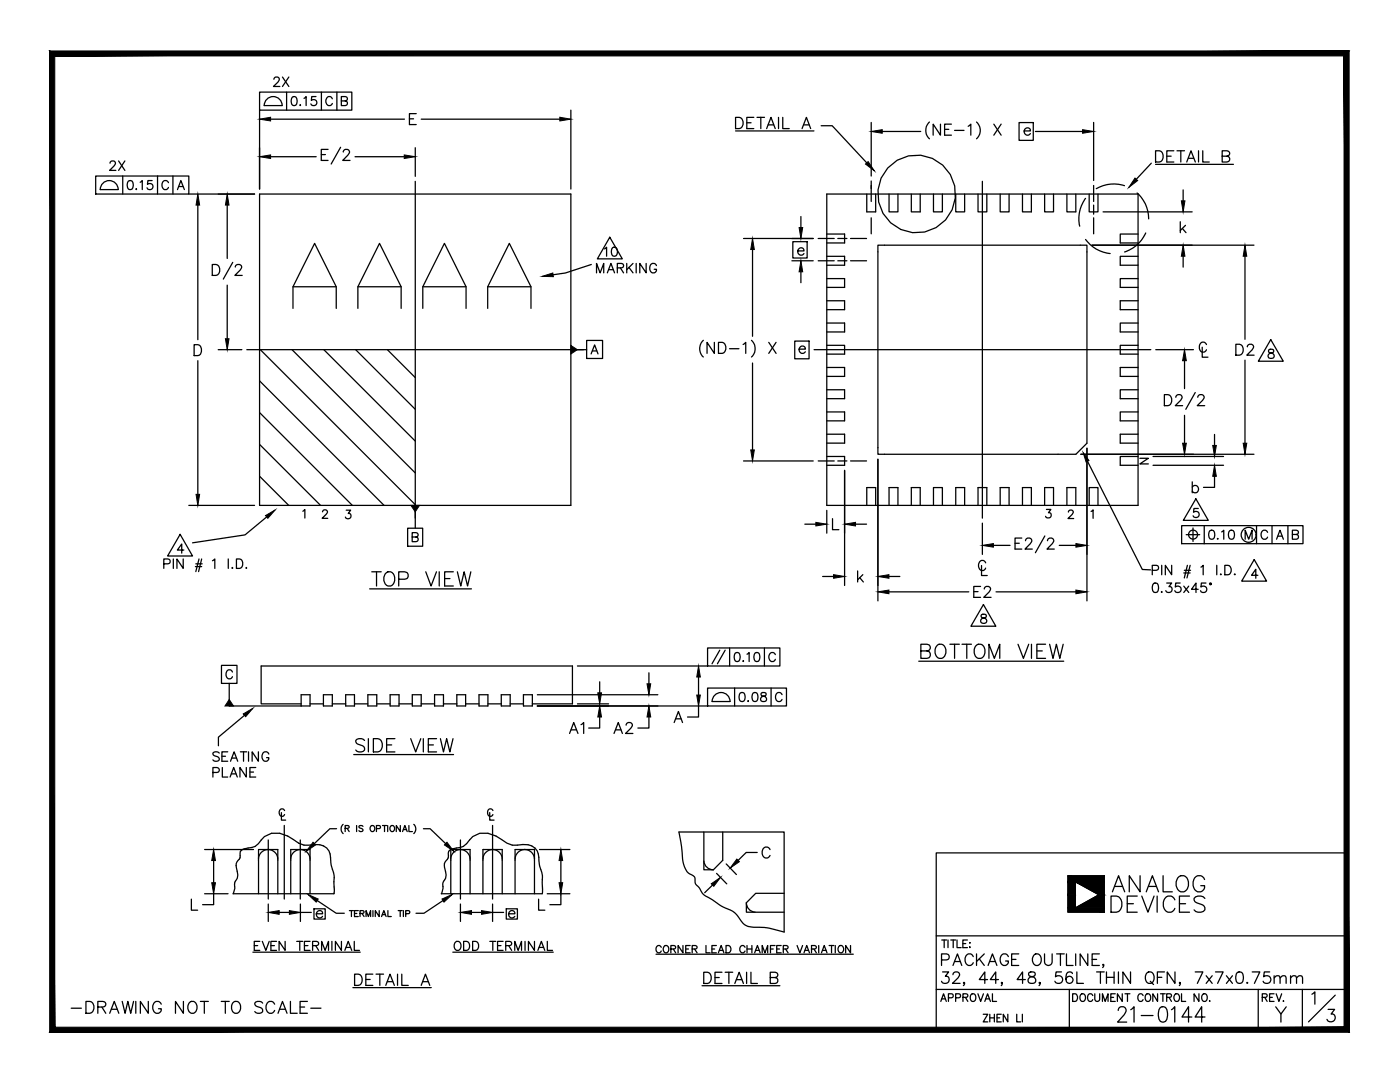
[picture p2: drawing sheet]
<svg xmlns="http://www.w3.org/2000/svg" width="279mm" height="216mm" viewBox="0 0 279 216" stroke-linecap="round" stroke-linejoin="round" font-family="sans-serif">
<defs><g id="words">
<text font-size="19" x="57.1" y="62.8">AAAA</text>
<g font-size="6.6">
<text x="220.8" y="179.2">ANALOG</text>
<text x="220.5" y="183.1">DEVICES</text>
<text x="221.9" y="205.3">21-0144</text>
</g>
<g font-size="5.7">
<text x="229.3" y="33.9">DETAIL B</text>
<text x="13.1" y="203.6">-DRAWING NOT TO SCALE-</text>
</g>
<text font-size="5.3" x="117.8" y="55.7">MARKING</text>
<g font-size="4.9">
<text x="53.3" y="18.3">2X</text>
<text x="20.8" y="35.3">2X</text>
<text x="119.2" y="52.2">10</text>
</g>
<text font-size="4.4" x="186.6" y="201.1">APPROVAL</text>
<text font-size="4" x="226.1" y="93.8">N</text>
</g></defs>
<!-- layer: 2 -->
<g fill="none" stroke="#000" stroke-width=".25">
<path d="M51.8 18.4h18.4v3.6h-18.4zM53.3 19.8a1.79 1.79 0 0 1 1.9-.4 1.79 1.79 0 0 1 1.1 1.7h-3.6l.1-.5zM57.2 18.4v3.6M58.4 19.4a.57 .57 0 0 1 .8 .2 .9 .9 0 0 1-.6 1.5 1.15 1.15 0 0 1-.2-1.7zM60.7 19.6l.4-.3v1.8M63.1 19.3h-.9l-.1 .8a.63 .63 0 0 1 1-.1 .63 .63 0 0 1-.1 1 .63 .63 0 0 1-1-.3M64.1 18.4v3.6M66.3 19.7a.66 .66 0 0 0-.7-.4 .66 .66 0 0 0-.6 .7 .74 .74 0 0 0 .3 .9 .74 .74 0 0 0 .9-.1l.1-.2M67.2 18.4v3.6M19.1 35.1h18.6v3.6h-18.6zM20.5 36.6a1.79 1.79 0 0 1 2-.4 1.79 1.79 0 0 1 1.1 1.6h-3.6l.1-.5zM24.5 35.1v3.6"/>
<path d="M25.6 36.1a.6 .6 0 0 1 .9 .3 .92 .92 0 0 1-.6 1.4 .98 .98 0 0 1-.4-1.4zM27.2 37.6l-.1 .1h.2M28 36.4l.4-.4v1.8M30.4 36h-.9l-.1 .8a.63 .63 0 0 1 1 0 .63 .63 0 0 1-.1 .9 .63 .63 0 0 1-1-.2M31.4 35.1v3.6M33.6 36.5a.67 .67 0 0 0-.7-.5 .67 .67 0 0 0-.6 .7v.4a.66 .66 0 0 0 .6 .7 .66 .66 0 0 0 .7-.4M34.5 35.1v3.6M35.4 37.8l.7-1.8 .7 1.8M35.7 37.2h.8M59.9 20.9v.2l.1-.1M68.1 20.1h1.1l.1-.3-.1-.4-.3-.1h-.8v1.8h.8a.47 .47 0 0 0 .4-.5 .47 .47 0 0 0-.4-.5M82.9 36.2v69.2"/>
<path d="M146.8 23.4h.7a1.19 1.19 0 0 1 .8 1.1 1.19 1.19 0 0 1-.8 1.2h-.7zM146.8 26.1h15.6M149 24.5h.9M150.4 23.4h-1.4v2.3h1.4M151.1 23.4h1.5M151.8 23.4v2.3M153 25.7l.9-2.3 .8 2.3M153.3 24.9h1.1M155.4 23.4v2.3M156.2 23.4v2.3h1.3M160.1 25.7l.8-2.3 .9 2.3M160.4 24.9h1.1"/>
<path d="M163.9 25.1h2.2l6.9 7.4M173.9 36.1v4.1M196.1 36.2v67.2M216.6 39.6a6.7 6.7 0 0 0-1.1 5.5M218.3 37v3.2M224.4 37a7 7 0 0 0-5.6 .6M226.9 38.5a6.8 6.8 0 0 1 2.3 5.2M229.8 32.6l-3 3.2M230.6 32.8h15.6M118 52.8l-5.2 1.7-2.4 .3M167.2 47.6h1.8M167.2 52h1.8"/>
<path d="M169.7 47.6h3.2M169.7 52h3.2M173.9 43.5v3.2M216.6 47.8a6.9 6.9 0 0 0 5 2.8M218.3 40.9v1.8M218.3 43.5v3.2M228.6 46.5a6.9 6.9 0 0 1-4.2 3.8M49.3 69.8h67.8M51.8 76l24.9 24.8M52 69.8l30.9 30.9M58.3 69.8l24.6 24.6M64.6 69.8l18.3 18.2"/>
<path d="M71 69.8l11.9 11.9M77.3 69.8l5.6 5.5M117.1 67.9h3.2v3.6h-3.2zM118 70.6l.7-1.8 .6 1.8M118.2 70h.9M158.6 68.1h2.9v3.5h-2.9zM162.5 69.8h67.2M239.9 69.3v2h1.2M240.8 68.8a.73 .73 0 0 0-.9-.5 .73 .73 0 0 0-.5 .7 .87 .87 0 0 0 .1 1 .87 .87 0 0 0 1 .2l.3-.4M253.2 69.8a.37 .37 0 0 0 .2 .6 .67 .67 0 0 1 .7 .2 .67 .67 0 0 1 .1 .7l-.7 .2a.52 .52 0 0 1-.4-.6 .52 .52 0 0 1 .5-.4l.3-.1a.37 .37 0 0 0 .2-.6zM253.6 67.8l2.5 4.3h-5zM51.8 95l5.8 5.8"/>
<path d="M51.8 88.7l12.2 12.1M51.8 82.3l18.5 18.5M163.3 92h3.2M167.2 92h1.8M169.7 92h3.2M217 92l11 21.6 1.6 .1M238.7 99.5l2.4 4.3h-4.9zM32.7 112.5h.8a.49 .49 0 0 0 .5-.5 .49 .49 0 0 0-.5-.5h-.8v1.9M34.6 111.5v1.9M35.9 106.6l2.5 4.3h-4.9zM36.6 111.5v1.9l-1.3-1.9v1.9M36.7 109.8h-1.3l.9-1.3v1.9"/>
<path d="M39 113.1h1.2M39.1 112.5h1.3M39.7 111.5l-.6 2.6M40.2 111.5l-.6 2.6M42.4 111.9l.5-.4v1.9M45.6 111.5v1.9M46.4 113.2v.2l.1-.1M47.2 111.5h.6a1 1 0 0 1 .7 1 1 1 0 0 1-.7 .9h-.6zM49.2 113.2l-.1 .1h.1M53.2 103.2l-4.3 3.5-10.5 1.6M60.4 102l.4-.3v1.7M64.4 102.1l.3-.4 .6 .2a.5 .5 0 0 1-.2 .7l-.8 .8h1.1"/>
<path d="M69.1 101.8h.9l-.5 .7a.57 .57 0 0 1 .4 .9 .57 .57 0 0 1-1-.2M73.8 117.5h20.3M74.2 114.1h1.9M75.1 114.1v2.8M76.9 114.5a1.04 1.04 0 0 1 1.2-.4 1.04 1.04 0 0 1 .7 1.1 1.25 1.25 0 0 1-.3 1.3 1.25 1.25 0 0 1-1.3 .3 1.75 1.75 0 0 1-.3-2.3zM79.6 115.6l1.6-.1a.76 .76 0 0 0 .3-.9 .76 .76 0 0 0-.7-.5h-1.2v2.8M81.4 105.4h3v3.6h-3zM82.3 107.2l1-.1 .1-.3-.1-.4-1-.1v1.8h.7a.47 .47 0 0 0 .5-.5 .47 .47 0 0 0-.5-.4M85 114.1l1 2.8 1.1-2.8M87.7 114.1v2.8M88.7 115.5h1.1M90.5 114.1h-1.8v2.8h1.8"/>
<path d="M91.3 114.1l.7 2.8 .6-2.8 .7 2.8 .7-2.8M195.9 112.8v2h1.1M196.7 112.3a.73 .73 0 0 0-.8-.5 .73 .73 0 0 0-.6 .8 .88 .88 0 0 0 .2 .9 .88 .88 0 0 0 .9 .2l.3-.3M208.8 101.6h.9l-.5 .7a.57 .57 0 0 1 .5 .9 .57 .57 0 0 1-1-.2M213.2 102.2l.4-.4 .5 .1a.52 .52 0 0 1-.1 .8l-.9 .8h1.2M217.7 102.1l.5-.4v1.7M230 113.8l1-.1 .2-.3-.1-.4-.3-.2h-.8v1.9M230.2 116.4a.61 .61 0 0 1 .9 .3 1.64 1.64 0 0 1-.1 1.4 .63 .63 0 0 1-1-.2 1.57 1.57 0 0 1 .2-1.5zM231.8 118v.1h.1M231.8 112.8v1.9M232.8 116.3h1l-.5 .8a.63 .63 0 0 1 .5 .9 .63 .63 0 0 1-1 0l-.2-.1M233.8 112.8v1.9l-1.2-1.9v1.9"/>
<path d="M235.5 116.3h-.9v.8a.67 .67 0 0 1 1 0 .67 .67 0 0 1-.2 1 .67 .67 0 0 1-1-.2M235.8 104.9h24.2v3.6h-24.2zM236.2 114.3h1.3M236.2 117l1 1.2M236.4 113.8h1.2M236.7 106.7h2.7M237 112.8l-.6 2.5M237.2 117l-1 1.2M237.5 112.8l-.6 2.5M238.1 105.4v2.6M239.1 117.6h-1.3l.9-1.3v1.9M239.1 101.5h-.8l-.1 .7a.64 .64 0 0 1 1 0 .64 .64 0 0 1-.2 1 .64 .64 0 0 1-.9-.3"/>
<path d="M239.7 113.2l.4-.4v1.9M240.3 104.9v3.6M240.7 116.3h-.9l-.1 .8a.66 .66 0 0 1 1 0 .66 .66 0 0 1-.1 1 .66 .66 0 0 1-1-.2M241.5 105.9a.6 .6 0 0 1 .8 .2 1.18 1.18 0 0 1-.4 1.5h-.1a.96 .96 0 0 1-.5-1.5zM242.8 112.8v1.9M243 107.4l-.1 .1h.2M243.6 114.5v.1h.1M243.8 106.1l.4-.3v1.8M244.4 112.8h.7a1 1 0 0 1 .6 .9 1 1 0 0 1-.6 1h-.7zM245.4 105.9a.58 .58 0 0 1 .9 .2 1.18 1.18 0 0 1-.4 1.5h-.2a1.12 1.12 0 0 1-.3-1.7zM246.4 114.5l-.1 .1h.2M248.5 107.6v-1.8l.7 1.8 .7-1.8v1.8"/>
<path d="M250.3 111.7l2.5 4.3h-5zM250.8 104.9v3.6M251 114.8h-1.2l.8-1.2v1.8M253 106.2a.67 .67 0 0 0-.8-.4 .67 .67 0 0 0-.5 .7 .75 .75 0 0 0 .2 .9 .75 .75 0 0 0 1-.1l.1-.1M253.9 104.9v3.6M254.8 107.6l.6-1.8 .7 1.8M255 107h.9M257 104.9v3.6M257.9 106.6h1.1l.1-.3-.1-.3-.3-.2h-.8v1.8h.8a.48 .48 0 0 0 .4-.5 .48 .48 0 0 0-.4-.5M44.2 132.8h3.1v3.6h-3.1zM45.7 136.4v4.5h14.4M46.4 134.1a.65 .65 0 0 0-.8-.4 .65 .65 0 0 0-.5 .7v.4a.65 .65 0 0 0 .5 .7 .65 .65 0 0 0 .8-.5"/>
<path d="M141.2 129.3h14.4v3.6h-14.4zM141.2 137.3h15.8v3.6h-15.8zM142.1 140h3.6M142.1 140a1.79 1.79 0 0 1 1.8-1.8 1.79 1.79 0 0 1 1.8 1.8M143.6 129.7l-1.5 2.7M144.7 129.7l-1.5 2.7M145.6 129.3v3.6M146.6 137.3v3.6M146.8 130.3a.58 .58 0 0 1 .8 .2 .92 .92 0 0 1-.6 1.5 1.16 1.16 0 0 1-.2-1.7zM147.8 138.3a.6 .6 0 0 1 .8 .2 .9 .9 0 0 1-.6 1.5 1.15 1.15 0 0 1-.2-1.7zM148.3 131.8l-.1 .1h.2M149.1 130.5l.4-.3v1.8"/>
<path d="M149.3 139.8l-.1 .1h.2M150.3 138.3a.58 .58 0 0 1 .9 .2 .91 .91 0 0 1-.6 1.5 1.15 1.15 0 0 1-.3-1.7zM150.7 130.3a.58 .58 0 0 1 .9 .2 .92 .92 0 0 1-.6 1.5 1.16 1.16 0 0 1-.3-1.7zM152 138.3a.36 .36 0 0 0 .1 .6 .65 .65 0 0 1 .7 .2 .65 .65 0 0 1 0 .8l-.6 .1a.52 .52 0 0 1-.4-.6 .52 .52 0 0 1 .5-.5h.3a.36 .36 0 0 0 .2-.6zM152.6 129.3v3.6M153.9 137.3v3.6M154.7 130.6a.67 .67 0 0 0-.7-.4 .67 .67 0 0 0-.6 .7v.4a.66 .66 0 0 0 .6 .7 .66 .66 0 0 0 .7-.4M156.1 138.6a.67 .67 0 0 0-.8-.4 .67 .67 0 0 0-.5 .7v.4a.67 .67 0 0 0 .5 .7 .67 .67 0 0 0 .8-.4M183.4 131.9h28.9M183.8 129.9l1.6-.1a.68 .68 0 0 0 0-1.1l-1.6-.1v2.8h1.2a.74 .74 0 0 0 .7-.8 .74 .74 0 0 0-.7-.7M187.1 128.7a1.3 1.3 0 0 1 1.5 .4 1.3 1.3 0 0 1 0 1.6 1.03 1.03 0 0 1-1.2 .7 1.03 1.03 0 0 1-.8-1.1 1.67 1.67 0 0 1 .5-1.6zM189.6 128.6h1.9"/>
<path d="M190.5 128.6v2.8M192 128.6h1.9M192.9 128.6v2.8M195 128.7a1.07 1.07 0 0 1 1.6 .9 1.24 1.24 0 0 1-.3 1.4 1.24 1.24 0 0 1-1.3 .2 1.74 1.74 0 0 1 0-2.5zM195.9 122.6a.37 .37 0 0 0 .2 .7 .64 .64 0 0 1 .7 .2 .64 .64 0 0 1 0 .8 .71 .71 0 0 1-1.1-.3 .89 .89 0 0 1 1.1-.8v-.4a.69 .69 0 0 0-.9-.2zM196.3 120.6l2.4 4.4h-4.9zM197.4 131.4v-2.8l1 2.8 1.1-2.8v2.8M203.2 128.6l1 2.8 1.1-2.8M205.9 128.6v2.8M206.9 129.9h1.1M208.7 128.6h-1.8v2.8h1.8M209.5 128.6l.6 2.8 .7-2.8 .7 2.8 .7-2.8"/>
<path d="M42.5 154.1h.8a.49 .49 0 0 0 .5-.3 .49 .49 0 0 0-.2-.5l-1.1-.2v2M43.8 150.3a.73 .73 0 0 0-1.3 .2l.3 .3a.99 .99 0 0 1 1 .5v.3a.84 .84 0 0 1-1.3 0M44.3 150.9h.7M44.4 153.1v2h1.1M45.5 150h-1.2v1.9h1.2M45.9 155.1l.7-2 .8 2M46 151.9l.7-1.9 .7 1.9M46.2 154.4h.9M46.3 151.3h.9M48 150h1.2M48.6 150v1.9M48.8 142.7l-5.2 4.4v1.7"/>
<path d="M49.2 153.1v2l-1.3-2v2M49.6 150v1.9M49.9 154.1h.7M51 153.1h-1.1v2h1.1M51.6 150v1.9l-1.3-1.9v1.9M53.6 150.5a.7 .7 0 0 0-.8-.5 .7 .7 0 0 0-.5 .7v.5a.68 .68 0 0 0 .7 .7 .68 .68 0 0 0 .6-.7h-.4M70.6 150.6h19.9M72.8 147.8a1.19 1.19 0 0 0-1.8 0 .69 .69 0 0 0 .5 .7l.7 .3a.65 .65 0 0 1 .5 .5 .65 .65 0 0 1-.2 .6 1.19 1.19 0 0 1-1.5-.2M73.5 147.4v2.6M74.5 147.4h.9a1.41 1.41 0 0 1 .9 1.3 1.41 1.41 0 0 1-.9 1.3h-.9zM77.2 148.6h1M78.8 147.4h-1.6v2.6h1.6"/>
<path d="M82 147.4l1 2.6 1-2.6M84.5 147.4v2.6M85.5 148.6h1M87.1 147.4h-1.6v2.6h1.6M87.9 147.4l.6 2.6 .6-2.6 .7 2.6 .6-2.6M51.6 171.4a1.93 1.93 0 0 1 1.9-1.9 1.93 1.93 0 0 1 1.9 1.9M53.5 167.6v11.8M56.2 162.1v1.5h.8M56.7 164.7v14.7M56.8 161.7a.56 .56 0 0 0-.6-.3 .56 .56 0 0 0-.5 .6v.3a.56 .56 0 0 0 .5 .6 .56 .56 0 0 0 .6-.4M58 171.4a1.94 1.94 0 0 1 1.9-1.9 1.94 1.94 0 0 1 2 1.9M59.9 167.6v11.8"/>
<path d="M63.3 179.7l3.8 2.5h1.6M66.7 178.2v-1.6a8.1 8.1 0 0 0-.6-4.1l-.1-.7a2.77 2.77 0 0 0-3.3-3.3 4.1 4.1 0 0 1-4.1-1 4.9 4.9 0 0 0-5.8-.6l-.7 .7a2.78 2.78 0 0 1-2.6 1.6 1.44 1.44 0 0 0-1.6 1.1 1.51 1.51 0 0 1-.6 1.7 2.41 2.41 0 0 0 0 1.8 1.83 1.83 0 0 1-.3 2.1l-.2 .6a2.44 2.44 0 0 1-.3 1.8M67.2 165.4h-1.4l-3.1 2.9M68.5 164.5a1.24 1.24 0 0 0 0 1.8M68.9 165.3l.7-.1v-.4l-.7-.1v1.2M69.3 165.3l.4 .6M71.2 164.7v1.2M72.4 164.9l-.3-.2-.4 .1v.3l.6 .3 .1 .3-.3 .2-.5-.2M74.1 164.8a.57 .57 0 0 1 .7 .5 .57 .57 0 0 1-.7 .6l-.2-.4zM75.1 165.3h.7l.1-.2v-.3l-.8-.1v1.2M76.3 164.7h.8M76.7 164.7v1.2"/>
<path d="M77.4 164.7v1.2M78 164.8a.57 .57 0 0 1 .8 .5 .57 .57 0 0 1-.8 .6l-.2-.4zM79.9 164.7v1.2l-.8-1.2v1.2M80.3 165.9l.5-1.2 .5 1.2M80.5 165.5h.6M81.6 164.7v1.2h.7M82.6 164.5a1.24 1.24 0 0 1 0 1.8M84.5 165.4h1.3l3.1 2.9M88.4 179.7l-3.8 2.5h-1.6M89.9 171.4a1.94 1.94 0 0 1 2-1.9 1.94 1.94 0 0 1 1.9 1.9M91.9 167.6v11.8M96.4 171.4a1.93 1.93 0 0 1 1.9-1.9 1.93 1.93 0 0 1 1.9 1.9"/>
<path d="M97.7 162.1v1.5h.9M98.3 164.7v14.7M98.4 161.7a.55 .55 0 0 0-.7-.3 .55 .55 0 0 0-.4 .6v.3a.54 .54 0 0 0 .4 .6 .54 .54 0 0 0 .7-.4M102.8 171.4a1.94 1.94 0 0 1 1.9-1.9 1.94 1.94 0 0 1 2 1.9M108.2 178.3v-1.7a8.8 8.8 0 0 0-.6-4.1v-.7a2.74 2.74 0 0 0-3.3-3.3 4.2 4.2 0 0 1-4.2-1 4.8 4.8 0 0 0-5.8-.6l-.6 .7a2.83 2.83 0 0 1-2.6 1.6 1.44 1.44 0 0 0-1.6 1.1 1.51 1.51 0 0 1-.7 1.7 2.31 2.31 0 0 0 .1 1.8 2.35 2.35 0 0 1-.5 2.4v.3a2.44 2.44 0 0 1-.3 1.8M135.5 166l.6 4a5.8 5.8 0 0 0 1.3 4.3 1.45 1.45 0 0 1 1.3 1.3v.3a1.37 1.37 0 0 0 .8 1.2 3.6 3.6 0 0 0 2.3 2.2 14.8 14.8 0 0 0 4.4 2.5 6.8 6.8 0 0 1 2 2.4 2.87 2.87 0 0 0 2.2 .8l2.7 .1 3.4 .9M140.5 171.8a1.87 1.87 0 0 0 1.9 1.8M50.5 190h21.4M50.7 188.7h.7M51.8 187.8h-1.1v1.8h1.1M52.4 187.8l.7 1.8 .6-1.8M54.1 188.7h.7"/>
<path d="M55.2 187.8h-1.1v1.8h1.1M56.9 187.8v1.8l-1.2-1.8v1.8M59.2 187.8h1.2M59.8 187.8v1.8M60.8 188.7h.7M61.9 187.8h-1.1v1.8h1.1M62.4 188.7l1-.1 .2-.3-.1-.3-.3-.2h-.8v1.8M63 188.7l.6 .9M64.2 189.6v-1.8l.7 1.8 .7-1.8v1.8M66.2 187.8v1.8M68.1 187.8v1.8l-1.2-1.8v1.8M68.8 189.6l.7-1.8 .7 1.8"/>
<path d="M69.1 189h.8M69.7 181.7h.8M70.1 181.7v1.2M70.4 197.1h15.7M70.7 187.8v1.8h1M70.7 182.3h.5M70.8 194.4h.7a1.19 1.19 0 0 1 .8 1.1 1.19 1.19 0 0 1-.8 1.1h-.7zM71.5 181.7h-.8v1.2h.8M71.8 182.3l.7-.1 .2-.3-.2-.2h-.7v1.2M72.2 182.3l.5 .6M73 195.4h.9M73.1 182.9v-1.2l.4 1.2 .5-1.2v1.2"/>
<path d="M74.4 194.4h-1.4v2.2h1.4M74.4 181.7v1.2M75 194.4h1.5M75.7 181.7v1.2l-.8-1.2v1.2M75.8 194.4v2.2M76.1 182.9l.5-1.2 .5 1.2M76.3 182.5h.6M77 196.6l.8-2.2 .9 2.2M77.3 195.9h1.1M77.4 181.7v1.2h.7M79.3 194.4v2.2M79.5 181.7h.8"/>
<path d="M79.9 181.7v1.2M80.2 194.4v2.2h1.3M80.5 181.7v1.2M81 182.3h.6l.2-.4-.2-.2h-.6v1.2M84.1 196.6l.8-2.2 .9 2.2M84.4 195.9h1M90.4 190h20M90.8 188.1a.66 .66 0 0 1 .8-.2 .66 .66 0 0 1 .4 .6v.5a.68 .68 0 0 1-.7 .7 .68 .68 0 0 1-.7-.7zM92.5 187.8h.6a.96 .96 0 0 1 .6 .9 .96 .96 0 0 1-.6 .9h-.6zM94.3 187.8h.6a.96 .96 0 0 1 .6 .9 .96 .96 0 0 1-.6 .9h-.6zM97.8 187.8h1.1M98.3 187.8v1.8"/>
<path d="M99.3 188.7h.7M100.4 187.8h-1.1v1.8h1.1M100.9 188.7l1-.1 .2-.3-.1-.3-.3-.2h-.8v1.8M101.5 188.7l.6 .9M102.7 189.6v-1.8l.7 1.8 .7-1.8v1.8M104.8 187.8v1.8M106.7 187.8v1.8l-1.2-1.8v1.8M107.3 189.6l.7-1.8 .7 1.8M107.6 189h.9M109.2 187.8v1.8h1.1M130.9 190.4h39.4M132 189a.53 .53 0 0 0-.6-.3 .53 .53 0 0 0-.5 .5v.4a.53 .53 0 0 0 .5 .5 .53 .53 0 0 0 .6-.3"/>
<path d="M132.5 188.9l.1-.1a.55 .55 0 0 1 .9 .4v.4a.55 .55 0 0 1-.6 .5 .55 .55 0 0 1-.5-.5zM133.9 189.4l.8-.1 .1-.5-.3-.1h-.6v1.4M134.4 189.4l.4 .7M136.3 188.7v1.4l-1-1.4v1.4M136.8 189.4h.6M137.7 188.7h-.9v1.4h.9M138.1 189.4l.9-.1 .1-.2v-.3l-.3-.1h-.7v1.4M138.6 189.4l.5 .7M140.1 196.7h15.5M140.4 194h.8a1.2 1.2 0 0 1 .8 1.1 1.2 1.2 0 0 1-.8 1.1h-.8zM140.9 188.7v1.4h.8M142.1 189.4h.5"/>
<path d="M142.7 195.1h.8M143 188.7h-.9v1.4h.9M143.4 190.1l.5-1.4 .6 1.4M143.6 189.6h.7M144.1 194h-1.4v2.2h1.4M144.7 194h1.5M144.9 188.7h.5a.78 .78 0 0 1 .5 .7 .78 .78 0 0 1-.5 .7h-.5zM145.5 194v2.2M146.6 196.2l.9-2.2 .9 2.2M147 195.5h1M148.7 189a.53 .53 0 0 0-.6-.3 .53 .53 0 0 0-.5 .5v.4a.53 .53 0 0 0 .5 .5 .53 .53 0 0 0 .6-.3M149 180.1a1.87 1.87 0 0 0 1.7 1.9"/>
<path d="M149 194v2.2M149.1 189.4h1M149.1 188.7v1.4M149.9 194v2.2h1.3M150.1 188.7v1.4M150.6 190.1l.6-1.4 .5 1.4M150.8 189.6h.7M152.1 190.1v-1.4l.6 1.4 .5-1.4v1.4M153.7 195.1l1.3-.1a.51 .51 0 0 0 0-.9l-1.3-.1v2.2h1a.59 .59 0 0 0 .5-.5 .59 .59 0 0 0-.5-.6M153.8 189.4h.5M154.7 188.7h-.9v1.4M155 189.4h.6"/>
<path d="M155.9 188.7h-.9v1.4h.9M156.3 189.4l.8-.1 .1-.5-.3-.1h-.6v1.4M156.8 189.4l.5 .7M159.1 188.7l.5 1.4 .6-1.4M160.5 190.1l.5-1.4 .6 1.4M160.6 189.6h.7M162 189.4l.8-.1 .1-.4-.3-.2h-.6v1.4M162.4 189.4l.5 .7M163.4 188.7v1.4M163.9 190.1l.6-1.4 .5 1.4M164.2 189.6h.7M165.5 188.7h.9"/>
<path d="M166 188.7v1.4M166.7 188.7v1.4M167.4 188.9a.54 .54 0 0 1 .6-.2 .54 .54 0 0 1 .4 .5v.4a.56 .56 0 0 1-.6 .5 .56 .56 0 0 1-.6-.5zM169.7 188.7v1.4l-.9-1.4v1.4"/>
<circle cx="182.9" cy="38.7" r="7.8"/>
<circle cx="238.1" cy="106.7" r=".9"/>
<circle cx="241.6" cy="116.5" r=".18"/>
<circle cx="249.2" cy="106.7" r="1.49"/>
</g>
<path d="M172.7 32.7l.6-.5 1.2 1.9zM226.5 35.5l.5 .5-1.7 1.4zM113.9 68.9l1.3 .9-1.3 .8zM216.2 90.3l1.1 1.6-.5 .3zM53 102.9l1.9-1.1-1.4 1.6zM82 100.8h1.7l-.8 1.3zM45.7 139.6l.9 1.3h-1.7zM48.5 142.5l2-1.2-1.5 1.7zM62.5 168.1l.5 .5-1.9 1.2zM89.2 168.1l1.3 1.7-1.8-1.2zM61.5 178.5l2 .9-.4 .6zM88.2 179.4l2-.9-1.6 1.5z" fill="#000" stroke="#000" stroke-width=".2"/>
<!-- layer: 1 -->
<g fill="none" stroke="#000" stroke-width=".25">
<path d="M51.8 38.7h62.1v62.1h-62.1zM165 38.7h62.1v62.1h-62.1zM173 38.7v3.6h1.8v-3.6M177.4 38.7v3.6h1.8v-3.6M181.9 38.7v3.6h1.7v-3.6M186.3 38.7v3.6h1.8v-3.6M190.7 38.7v3.6h1.8v-3.6M195.2 38.7v3.6h1.7v-3.6M199.6 38.7v3.6h1.8v-3.6M204.1 38.7v3.6h1.7v-3.6M208.5 38.7v3.6h1.8v-3.6M212.9 38.7v3.6h1.8v-3.6"/>
<path d="M217.4 38.7v3.6h1.7v-3.6M165 46.7h3.6v1.8h-3.6M165 51.1h3.6v1.8h-3.6M165 55.6h3.6v1.7h-3.6M175.2 48.9h41.7v39.5l-2.2 2.2h-39.5zM227.1 46.7h-3.5v1.8h3.5M227.1 55.6h-3.5v1.7h3.5M227.1 51.1h-3.5v1.8h3.5M165 68.9h3.6v1.8h-3.6M165 60h3.6v1.8h-3.6M165 64.5h3.6v1.7h-3.6M165 73.3h3.6v1.8h-3.6"/>
<path d="M165 77.8h3.6v1.8h-3.6M227.1 68.9h-3.5v1.8h3.5M227.1 64.5h-3.5v1.7h3.5M227.1 77.8h-3.5v1.8h3.5M227.1 60h-3.5v1.8h3.5M227.1 73.3h-3.5v1.8h3.5M165 82.2h3.6v1.8h-3.6M165 86.6h3.6v1.8h-3.6M165 91.1h3.6v1.7h-3.6M227.1 82.2h-3.5v1.8h3.5M227.1 91.1h-3.5v1.7h3.5M227.1 86.6h-3.5v1.8h3.5"/>
<path d="M173 100.8v-3.5h1.8v3.5M177.4 100.8v-3.5h1.8v3.5M181.9 100.8v-3.5h1.7v3.5M186.3 100.8v-3.5h1.8v3.5M190.7 100.8v-3.5h1.8v3.5M195.2 100.8v-3.5h1.7v3.5M199.6 100.8v-3.5h1.8v3.5M204.1 100.8v-3.5h1.7v3.5M208.5 100.8v-3.5h1.8v3.5M212.9 100.8v-3.5h1.8v3.5M217.4 100.8v-3.5h1.7v3.5M60.1 138.6h1.8v2.3h-1.8z"/>
<path d="M64.5 138.6h1.8v2.3h-1.8zM69 138.6h1.7v2.3h-1.7zM73.4 138.6h1.8v2.3h-1.8zM77.9 138.6h1.7v2.3h-1.7zM82.3 138.6h1.8v2.3h-1.8zM86.7 138.6h1.8v2.3h-1.8zM91.2 138.6h1.7v2.3h-1.7zM95.6 138.6h1.8v2.3h-1.8zM100 138.6h1.8v2.3h-1.8zM104.5 138.6h1.7v2.3h-1.7zM60.1 140.4h-8v-7.5h62.1v7.5h-8M61.9 140.4h2.6"/>
<path d="M66.3 140.4h2.7M70.7 140.4h2.7M75.2 140.4h2.7M79.6 140.4h2.7M84.1 140.4h2.6M88.5 140.4h2.7M92.9 140.4h2.7M97.4 140.4h2.6M101.8 140.4h2.7M55.4 178.3v-8.8h-3.8v8.8M61.9 178.3v-8.8h-3.9v8.8M66.7 178.2l-.1 .1h-20.1"/>
<path d="M88.1 178.3h20.1M93.8 178.3v-8.8h-3.8v8.8M100.2 178.3v-8.8h-3.8v8.8M102.8 169.5v8.8M102.8 169.5h3.9v8.8M135.5 166h21v20M140.5 166v7.6h1.9M144.2 166v5.7l-1.8 1.9M156.5 178.3h-5.7l-1.8 1.8v1.9h7.5"/>
</g>
<!-- layer: DIM -->
<g fill="none" stroke="#000" stroke-width=".25">
<path d="M37.7 38.7h13.1M51.8 22v15.7M54 31.3h9.1M54 23.8h26.7M64.1 30.8h.8M65.5 29.8h-1.4v2.2h1.4M68 29.4l-1.9 3.3M68.5 30.3l.1-.3 .3-.2 .6 .1a.49 .49 0 0 1 .1 .7l-1.2 1.4h1.5M70.9 31.3h9.8M81.7 23.7h.8M82.9 29.5v5.7M83.1 22.7h-1.4v2.2h1.4"/>
<path d="M84.1 23.8h27.6M113.9 22v15.7M173.9 24.4v10.7M176.1 26.2h7.7M185.5 24.3a2.28 2.28 0 0 0 0 3.4M187.7 24.8v2.2l-1.5-2.2v2.2M188.5 25.8h.9M189.9 24.8h-1.4v2.2h1.4M190.5 26h1.9M193.2 25.2l.5-.4v2.2M194.9 24.3a2.24 2.24 0 0 1 0 3.4M198.3 24.8l1.5 2.2"/>
<path d="M199.8 24.8l-1.5 2.2M203.4 24.5h2.8v3.5h-2.8zM204.4 26.1h1.2a.67 .67 0 0 0-.9-.5 .67 .67 0 0 0-.2 1.1 .66 .66 0 0 0 1.1 0M206.6 26.2h9.5M218.3 24.4v11.6M236.1 37.9v2.2M39.5 40.9v26.9M42.4 52.8h.7a1.16 1.16 0 0 1 .8 1.1 1.16 1.16 0 0 1-.8 1.1h-.7zM45.3 40.9v10.7M45.3 56.9v10.7M46.4 52.4l-1.8 3.3M47 53.3l.1-.3a.74 .74 0 0 1 1 0 .69 .69 0 0 1-.2 .9l-1 1.1h1.4"/>
<path d="M148.4 47.6h13.9M150.2 49.8v17.3M158 52h4.3M158.2 48.2h2.9v3.3h-2.9zM159.2 50.1h1.3a.67 .67 0 0 0-1-.6 .67 .67 0 0 0-.2 1.1 .66 .66 0 0 0 1.2 0M159.8 43.2v2.2M159.8 54.2v2.2M163.3 47.6h3.2M163.3 52h3.2M217.9 48.9h32.4M220.1 42.3h17.8M235.5 44.2v2.2"/>
<path d="M236 45.6l.7 .8M236.1 51.1v2.2M236.6 45l-1.1 1M248.5 51.1v16.6M38.7 68.8h.8a1.17 1.17 0 0 1 .7 1.1 1.17 1.17 0 0 1-.7 1.1h-.8zM39.5 72v26.6M43.5 69.8h4.8M140.4 67.9a2.26 2.26 0 0 0 0 3.3M142.6 68.3v2.2l-1.5-2.2v2.2M143.4 68.3h.7a1.18 1.18 0 0 1 .8 1.1 1.18 1.18 0 0 1-.8 1.1h-.7zM145.6 69.6h1.9M148.3 68.7l.5-.4v2.2"/>
<path d="M150 67.9a2.26 2.26 0 0 1 0 3.3M150.2 72.4v17.4M153.4 68.3l1.5 2.2M154.9 68.3l-1.5 2.2M159.5 69.7h1.2a.67 .67 0 0 0-.9-.6 .67 .67 0 0 0-.2 1.1 .65 .65 0 0 0 1.1 0M230.7 69.8h7.5M232.4 78.7h.7a1.17 1.17 0 0 1 .8 1.1 1.17 1.17 0 0 1-.8 1.1h-.7zM234.7 79.3l.1-.3 .3-.3 .6 .2a.51 .51 0 0 1 .1 .7l-1.2 1.3h1.4M236.4 72v5.5M238.5 78.3l-1.8 3.4M239 79.3l.1-.3 .4-.3 .6 .2a.49 .49 0 0 1 .1 .7l-1.3 1.3h1.5M246.6 68.7h.8a1.16 1.16 0 0 1 .7 1.1 1.16 1.16 0 0 1-.7 1.1h-.8z"/>
<path d="M248.5 71.9v16.5M248.9 69.2l.1-.3 .4-.2 .6 .1a.48 .48 0 0 1 .1 .7l-1.3 1.4h1.5M148.4 92h13.9M168.6 93.9v22.9M175.2 91.6v28.3M215.7 90.6h34.6M216.9 89.4v30.5M230.1 91.1h14.1M230.1 92.8h14.1M236.4 82.9v5.5M237.9 97.2a.7 .7 0 0 1 1.1-.1 .7 .7 0 0 1 0 1 .7 .7 0 0 1-1.1-.1M237.9 96.1v2.2"/>
<path d="M242.4 95v2.2h-2.2M242.4 86.7v2.2M37.7 100.8h13.1M160.6 104.6h2.2M164.2 115h2.2M165 101.8v4.6M166.1 103.5v2.2h1.3M170.7 104.6h2.2M171.2 113.9v2.2M171.6 115.3l.7 .8M172.2 114.7l-1 1M177.4 115h2.2"/>
<path d="M177.4 118.1h15.9M194.3 118.1h.9M195.7 117h-1.4v2.2h1.4M196.1 104.4v6.2M196.4 117.5l.2-.4a.72 .72 0 0 1 1 .1 .69 .69 0 0 1-.2 1l-1.1 1h1.5M198.3 108.8h3.3M198.8 118.1h15.9M202.6 108.4h.8M203.9 107.4h-1.3v2.2h1.3M204.7 107.9l.1-.3 .3-.2 .6 .1a.49 .49 0 0 1 .1 .7l-1.2 1.4h1.4M208.5 106.9l-1.9 3.4M209 107.9l.2-.3 .3-.2 .6 .1a.49 .49 0 0 1 .1 .7l-1.3 1.4h1.5"/>
<path d="M211.4 108.8h3.3M107.2 138.6h24.1M115.2 132.9h26M119.7 136v2.2M129.5 134.2v2.2M139.4 135.1v3.6M107.2 140.9h34M113.7 146.4l.8-2.2 .8 2.2M114 145.6h1M115.2 140.4h6.3M116 144.6l.5-.4v2.2M119.7 143.1v2.2h-2.2"/>
<path d="M122.5 146.4l.9-2.2 .8 2.2M122.9 145.6h1M125 144.7l.1-.3 .3-.2 .6 .1a.49 .49 0 0 1 .1 .7l-1.3 1.4h1.5M129.5 143.1v2.2h-2.2M134.5 144.2l.9-2.2 .8 2.2M134.9 143.4h1M139.4 140.9v2.2h-2.2M38.2 179.4v2.2h1.2M40.8 178.3h4.7M40.8 169.5h9.8M42.6 178.3v2.2h-2.2M42.6 171.7v4.4"/>
<path d="M107.5 179.4v2.2h1.2M107.7 169.5h6M109.2 178.3h4.5M111.9 178.3v2.2h-2.2M111.9 171.7v4.4M142.2 176.6l-1.6 1.5M143 174.3l2 2.1M144.9 172.4l2.1 2.1M151.1 170.1h-2.2l-1.6 1.6M153.7 169.5a.81 .81 0 0 0-.9-.5 .81 .81 0 0 0-.7 .8 .96 .96 0 0 0 .2 1.1 .96 .96 0 0 0 1.1 .2l.3-.4M53.5 180.4v3.5M55.7 182.1h2"/>
<path d="M60 180.4v3.5M60 182.1h2.1M62.7 181.3h2.2v2.1h-2.2zM63.1 182.3h1.3a.67 .67 0 0 0-1-.5 .67 .67 0 0 0-.2 1 .66 .66 0 0 0 1.2 0M91.9 180.4v3.5M94.1 182.1h2M98.3 182.1h2.2M98.3 180.4v3.5M101 181.3h2.3v2.1h-2.3zM101.5 182.3h1.3a.67 .67 0 0 0-1-.5 .67 .67 0 0 0-.2 1 .65 .65 0 0 0 1.2 0"/>
</g>
<g fill="#000" stroke="#000" stroke-width=".2">
<path d="M51.8 31.3l2.2-.4v.7zM51.8 23.8l2.2-.4v.7zM80.7 30.9l2.2 .4-2.2 .3zM111.7 23.4l2.2 .4-2.2 .3zM173.9 26.2l2.2-.3v.7zM216.1 25.9l2.2 .3-2.2 .4zM39.5 38.7l.3 2.2h-.7zM45.3 38.7l.4 2.2h-.7zM150.2 47.6l.3 2.2h-.7zM159.5 45.4h.7l-.4 2.2zM159.8 52l.4 2.2h-.7zM236.1 48.9l.4 2.2h-.7z"/>
<path d="M235.8 40.1h.7l-.4 2.2zM248.5 48.9l.3 2.2h-.7zM45 67.6h.7l-.4 2.2zM236.4 69.8l.4 2.2h-.8zM39.1 98.6h.7l-.3 2.2zM149.8 89.8h.7l-.3 2.2zM236 88.4h.8l-.4 2.2zM242 88.9h.7l-.3 2.2zM242.4 92.8l.3 2.2h-.7zM248.1 88.4h.7l-.3 2.2zM162.8 104.2l2.2 .4-2.2 .4zM166.4 114.7l2.2 .3-2.2 .4z"/>
<path d="M168.6 104.6l2.1-.4v.8zM175.2 115l2.2-.3v.7zM175.2 118.1l2.2-.4v.8zM196.1 108.8l2.2-.3v.7zM214.7 108.5l2.2 .3-2.2 .4zM214.7 117.7l2.2 .4-2.2 .4zM119.3 138.2h.7l-.3 2.2zM129.1 136.4h.8l-.4 2.2zM139.4 132.9l.4 2.2h-.7zM139.1 138.7h.7l-.4 2.2zM119.7 140.9l.3 2.2h-.7zM129.5 140.9l.4 2.2h-.8z"/>
<path d="M42.6 169.5l.4 2.2h-.7zM42.3 176.1h.7l-.4 2.2zM111.9 169.5l.4 2.2h-.7zM111.6 176.1h.7l-.4 2.2zM142 176.3l1.8-1.2-1.3 1.8zM147.1 171.4l.5 .5-1.9 1.3zM53.5 182.1l2.2-.4v.7zM57.7 181.7l2.3 .4-2.3 .3zM91.9 182.1l2.2-.4v.7zM96.1 181.7l2.2 .4-2.2 .3z"/>
</g>
<!-- layer: 1 -->
<path d="M91.9 169.5h.1" fill="none" stroke="#000" stroke-width=".2"/>
<!-- layer: 0 -->
<g fill="#000" stroke="#000" stroke-width=".2">
<path d="M9.9 10.2l1 1 258.3-1zM10.9 11.2l258.3-1-1 1z"/>
<path d="M268.2 11.2l1 194.8v-195.8zM268.2 11.2l1 194.8-1-1zM9.9 206h259.3l-1-1zM9.9 206l1-1h257.3zM9.9 10.2v195.8l1-1zM9.9 10.2l1 1v193.8zM9.9 10.2l1 1z"/>
<path d="M213.1 176l1.5 2.5v-2.5zM213.1 176l1.5 2.5h-1.5z"/>
<path d="M213.1 178.5l1.5 2.6v-2.6zM213.1 178.5l1.5 2.6h-1.5z"/>
<path d="M213.1 174.7l7.3 1.3v-1.3zM213.1 174.7l7.3 1.3h-7.3z"/>
<path d="M214.6 176l5.8 2.5v-2.5zM214.6 176l5.8 2.5h-1.1z"/>
<path d="M219.3 178.5l1.1 2.6v-2.6zM214.6 181.1l4.7-2.6 1.1 2.6z"/>
<path d="M213.1 181.1l7.3 .9v-.9zM213.1 181.1l7.3 .9h-7.3z"/>
</g>
<g fill="none" stroke="#000" stroke-width=".25">
<path d="M268.7 170.2h-81.9v35.3M186.8 186.7h81.9M186.8 197.4h81.9M187.9 191.5l1.3-.1a.62 .62 0 0 0 .2-.6 .62 .62 0 0 0-.5-.5h-1v2.3M187.9 187.6h1M188.1 193.9h1.2l-.6 .9a.73 .73 0 0 1 .7 .8 .73 .73 0 0 1-.9 .6l-.4-.1-.2-.3M188.4 187.6v1.5M189.2 187.6v1.5M189.7 187.6h1M190.2 192.6l.9-2.3 .8 2.3M190.2 194.5l.1-.4a.76 .76 0 0 1 1-.1 .53 .53 0 0 1 .1 .8l-1.3 1.4h1.5M190.2 187.6v1.5"/>
<path d="M190.5 191.9h1.1M191 187.6v1.5h.8M192.2 188.3h.5M192.5 196.1l-.1 .1-.1-.1 .1-.1 .1 .1-.2 .6M193.1 187.6h-.9v1.5h.9M193.6 188.1v.1zM193.6 188.9v.2zM194.2 190.9a.84 .84 0 0 0-.9-.6 .84 .84 0 0 0-.7 .9 1 1 0 0 0 .2 1.1 1 1 0 0 0 1.1 .2l.3-.4M194.9 190.3v2.3M195.4 191.3l1 1.3M196.4 190.3l-1.5 1.6M197.1 195.5h-1.7l1.1-1.6v2.3"/>
<path d="M197.2 192.6l.9-2.3 .9 2.3M197.5 191.9h1.1M199.3 195.5h-1.7l1.1-1.6v2.3M200 196.1l-.1 .1-.1-.1 .1-.1 .1 .1-.2 .6M201.2 190.9a.84 .84 0 0 0-.9-.6 .84 .84 0 0 0-.7 .9 1 1 0 0 0 .2 1.1 1 1 0 0 0 1.1 .2l.3-.4v-.3h-.5M201.9 191.4h.9M203.3 190.3h-1.4v2.3h1.4M204.6 195.5h-1.6l1.1-1.6v2.3M205.4 194a.46 .46 0 0 0 .2 .8 .93 .93 0 0 1 1.1 1 .8 .8 0 0 1-.9 .4 .8 .8 0 0 1-.6-.7 1.06 1.06 0 0 1 1.1-.7 .46 .46 0 0 0 .2-.8l-.3-.1zM206.5 190.4a1.06 1.06 0 0 1 1.2 .4 1.06 1.06 0 0 1 0 1.3 .85 .85 0 0 1-1 .5 .85 .85 0 0 1-.7-.8 1.51 1.51 0 0 1 .5-1.4zM207.6 196.1l-.1 .1-.1-.1 .1-.1 .1 .1-.2 .6M208.5 190.3v1.7a.77 .77 0 0 0 .7 .7 .77 .77 0 0 0 .8-.7v-1.7"/>
<path d="M210.9 190.3h1.5M211.6 190.3v2.3M211.8 193.9h-1l-.2 1a.82 .82 0 0 1 1.3 0 .82 .82 0 0 1-.2 1.2 .82 .82 0 0 1-1.2-.3M212.8 190.3v2.3h1.4M213.4 197.4v8.1M214 194.3a.65 .65 0 0 0-.6-.4 .65 .65 0 0 0-.6 .5 1.7 1.7 0 0 0 .2 1.7 .71 .71 0 0 0 1.1-.3 .71 .71 0 0 0-.5-1 .71 .71 0 0 0-.9 .7M214.1 198.3a.83 .83 0 0 1 .9 .4 .83 .83 0 0 1-.2 1.1h-.7zM214.7 190.3v2.3M214.9 193.9v2.3h1.3M215.7 198.5a.54 .54 0 0 1 .6-.2 .54 .54 0 0 1 .3 .6v.3a.55 .55 0 0 1-.5 .6 .55 .55 0 0 1-.6-.6zM217.1 190.3v2.3l-1.5-2.3v2.3M218 191.4h.8"/>
<path d="M218.1 198.7a.53 .53 0 0 0-.6-.4 .53 .53 0 0 0-.4 .6v.3a.53 .53 0 0 0 .4 .6 .53 .53 0 0 0 .6-.3M218.5 198.3v1.1a.49 .49 0 0 0 .5 .4 .49 .49 0 0 0 .5-.4v-1.1M218.8 193.9h1.6M219.4 190.3h-1.4v2.3h1.4M219.6 193.9v2.3M220.3 192.5l-.1 .1-.1-.1 .1-.1a.43 .43 0 0 1-.1 .7M220.8 193.9v2.3M220.8 195h1.5M222.3 193.9v2.3M223.2 193.9v2.3M225.6 193.9v2.3l-1.5-2.3v2.3M228.8 194.3a.85 .85 0 0 1 1-.3 .85 .85 0 0 1 .5 .8 1 1 0 0 1-.2 1.1 1 1 0 0 1-1.1 .2 1.46 1.46 0 0 1-.2-1.8z"/>
<path d="M229.6 195.8l.6 .7M231 195h.9M232.4 193.9h-1.4v2.3M234.5 193.9v2.3l-1.6-2.3v2.3M235.6 196.1l-.1 .1-.1-.1 .1-.1 .1 .1-.2 .6M238.5 193.9h1.6l-1.1 2.3M240.7 194.7l1.2 1.5M241.9 194.7l-1.2 1.5M242.6 193.9h1.5l-1.1 2.3M244.8 194.7l1.2 1.5M246 194.7l-1.2 1.5M246.9 194a.77 .77 0 0 1 1.1 .4 1.96 1.96 0 0 1-.2 1.7 .77 .77 0 0 1-1.1-.3 1.96 1.96 0 0 1 .2-1.8z"/>
<path d="M248.9 196l-.1 .1 .1 .1 .1-.1M249.9 193.9h1.5l-1.1 2.3M251.1 197.4v8.1M251.9 199h.8l.2-.3-.1-.3-.3-.1h-.6v1.5M252.4 199l.5 .8M253.4 199h.5M253.4 193.9h-1.1l-.1 1a.82 .82 0 0 1 1.2 0 .82 .82 0 0 1-.1 1.2 .82 .82 0 0 1-1.2-.3M254.3 198.3h-.9v1.5h.9M254.3 195.1l.5-.4 .6 .1 .1 1.4M254.3 194.7v1.5M254.7 198.3l.5 1.5 .6-1.5M255.5 195.1l.5-.4 .6 .1 .1 1.4"/>
<path d="M256.1 199.7v.1h.1M257.6 195.1l.5-.4 .5 .1 .1 1.4M257.6 194.7v1.5M258.7 195.1l.6-.4 .5 .1 .2 1.4M259.9 197.4v8.1M261.8 198.4l.6-.5v2.5M266.5 198.6l-5.4 5.3M196.2 202.4h.9l-.9 1.5h.9M197.5 202.4v1.5M197.5 203.1h.9M198.4 202.4v1.5M199 203.1h.5"/>
<path d="M199.8 202.4h-.8v1.5h.8M201.1 202.4v1.5l-.9-1.5v1.5M202.9 202.4v1.5h.8M204 202.4v1.5M254.6 200.9l1 1.4 1.1-1.4M255.6 202.3v1.6M265.1 201.4h1.2l-.7 .9a.8 .8 0 0 1 .9 1 .8 .8 0 0 1-1.1 .6l-.3-.1-.3-.4"/>
</g>
<path d="M213.1 174.7h7.3v7.3h-7.3zM214.6 176l4.7 2.5-4.7 2.6z" fill="none" stroke="#000" stroke-width=".2"/>
<use href="#words"/>
</svg>
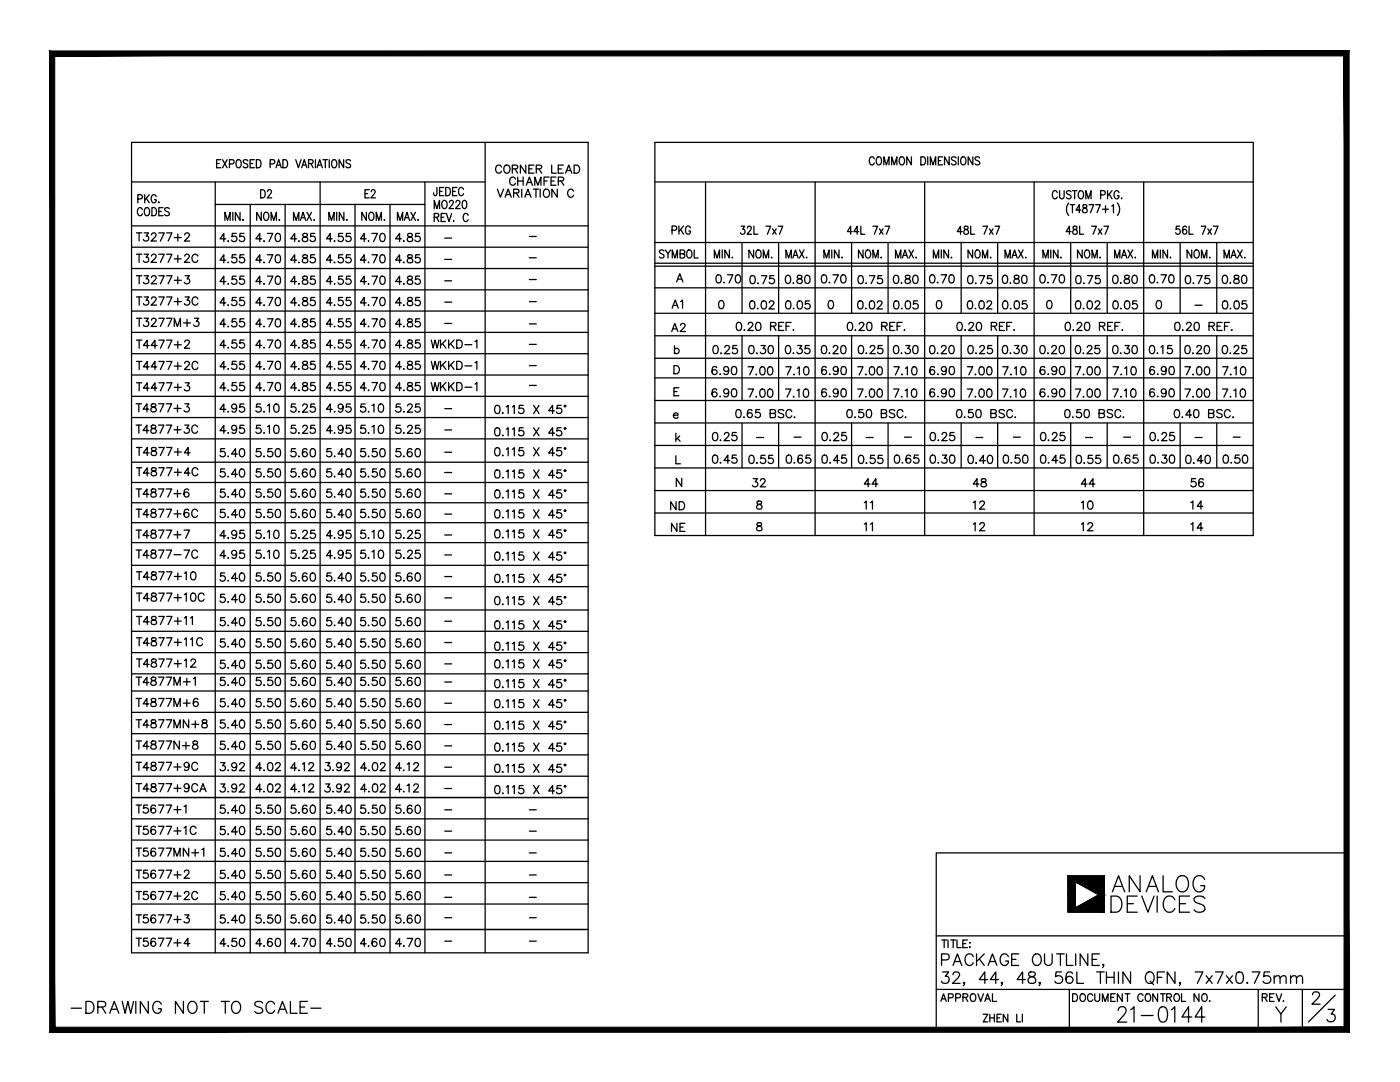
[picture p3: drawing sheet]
<svg xmlns="http://www.w3.org/2000/svg" width="279mm" height="216mm" viewBox="0 0 279 216" stroke-linecap="round" stroke-linejoin="round" font-family="sans-serif">
<defs><g id="words">
<g font-size="6.6">
<text x="220.8" y="179.2">ANALOG</text>
<text x="220.5" y="183.1">DEVICES</text>
<text x="221.9" y="205.3">21-0144</text>
</g>
<text font-size="5.7" x="13.1" y="203.6">-DRAWING NOT TO SCALE-</text>
<g font-size="4.9">
<text x="133" y="48">PKG</text>
<text x="26.1" y="49.4">T3277+2</text>
<text x="26.1" y="53.6">T3277+2C</text>
<text x="26.1" y="57.9">T3277+3</text>
<text x="141.8" y="57.9">0.70</text>
<text x="148.5" y="57.9">0.75</text>
<text x="155.6" y="57.9">0.80</text>
<text x="162.6" y="57.9">0.70</text>
<text x="170" y="57.9">0.75</text>
<text x="177.1" y="57.9">0.80</text>
<text x="184.1" y="57.9">0.70</text>
<text x="191.9" y="57.9">0.75</text>
<text x="199" y="57.9">0.80</text>
<text x="206.4" y="57.9">0.70</text>
<text x="213.4" y="57.9">0.75</text>
<text x="220.8" y="57.9">0.80</text>
<text x="228.2" y="57.9">0.70</text>
<text x="235.3" y="57.9">0.75</text>
<text x="242.7" y="57.9">0.80</text>
<text x="26.1" y="62.1">T3277+3C</text>
<text x="133" y="62.8">A1</text>
<text x="133" y="67.4">A2</text>
<text x="141.1" y="72">0.25</text>
<text x="148.2" y="72">0.30</text>
<text x="155.6" y="72">0.35</text>
<text x="162.6" y="72">0.20</text>
<text x="170" y="72">0.25</text>
<text x="177.1" y="72">0.30</text>
<text x="184.1" y="72">0.20</text>
<text x="191.9" y="72">0.25</text>
<text x="199" y="72">0.30</text>
<text x="206.4" y="72">0.20</text>
<text x="213.4" y="72">0.25</text>
<text x="220.8" y="72">0.30</text>
<text x="235.3" y="72">0.20</text>
<text x="242.7" y="72">0.25</text>
<text x="148.2" y="76.2">7.00</text>
<text x="170" y="76.2">7.00</text>
<text x="191.9" y="76.2">7.00</text>
<text x="213.4" y="76.2">7.00</text>
<text x="235.3" y="76.2">7.00</text>
<text x="26.1" y="79.4">T4477+3</text>
<text x="42.7" y="83.6">4.95</text>
<text x="56.8" y="83.6">5.25</text>
<text x="63.9" y="83.6">4.95</text>
<text x="70.6" y="83.6">5.10</text>
<text x="77.6" y="83.6">5.25</text>
<text x="140.8" y="80.4">6.90</text>
<text x="162.6" y="80.4">6.90</text>
<text x="184.1" y="80.4">6.90</text>
<text x="206.4" y="80.4">6.90</text>
<text x="228.2" y="80.4">6.90</text>
<text x="26.1" y="87.8">T4877+3C</text>
<text x="42.7" y="87.8">4.95</text>
<text x="56.8" y="87.8">5.25</text>
<text x="63.9" y="87.8">4.95</text>
<text x="70.6" y="87.8">5.10</text>
<text x="77.6" y="87.8">5.25</text>
<text x="141.1" y="89.3">0.25</text>
<text x="162.6" y="89.3">0.25</text>
<text x="184.5" y="89.3">0.25</text>
<text x="206.4" y="89.3">0.25</text>
<text x="228.2" y="89.3">0.25</text>
<text x="42.7" y="92.4">5.40</text>
<text x="49.7" y="92.4">5.50</text>
<text x="56.8" y="92.4">5.60</text>
<text x="63.9" y="92.4">5.40</text>
<text x="70.6" y="92.4">5.50</text>
<text x="77.6" y="92.4">5.60</text>
<text x="148.2" y="93.8">0.55</text>
<text x="170" y="93.8">0.55</text>
<text x="191.9" y="93.8">0.40</text>
<text x="213.4" y="93.8">0.55</text>
<text x="235.3" y="93.8">0.40</text>
<text x="26.1" y="96.3">T4877+4C</text>
<text x="26.1" y="100.5">T4877+6</text>
<text x="42.7" y="100.5">5.40</text>
<text x="49.7" y="100.5">5.50</text>
<text x="56.8" y="100.5">5.60</text>
<text x="63.9" y="100.5">5.40</text>
<text x="70.6" y="100.5">5.50</text>
<text x="77.6" y="100.5">5.60</text>
<text x="148.9" y="98.4">32</text>
<text x="171.1" y="98.4">44</text>
<text x="193" y="98.4">48</text>
<text x="214.5" y="98.4">44</text>
<text x="236.4" y="98.4">56</text>
<text x="132.6" y="107.2">NE</text>
<text x="132.6" y="103">ND</text>
<text x="171.1" y="107.2">11</text>
<text x="193" y="107.2">12</text>
<text x="214.5" y="107.2">12</text>
<text x="236.4" y="107.2">14</text>
<text x="26.1" y="108.7">T4877+7</text>
<text x="42.7" y="108.7">4.95</text>
<text x="56.8" y="108.7">5.25</text>
<text x="63.9" y="108.7">4.95</text>
<text x="70.6" y="108.7">5.10</text>
<text x="77.6" y="108.7">5.25</text>
<text x="42.7" y="130.5">5.40</text>
<text x="49.7" y="130.5">5.50</text>
<text x="56.8" y="130.5">5.60</text>
<text x="63.9" y="130.5">5.40</text>
<text x="70.6" y="130.5">5.50</text>
<text x="77.6" y="130.5">5.60</text>
<text x="42.7" y="134.8">5.40</text>
<text x="49.7" y="134.8">5.50</text>
<text x="56.8" y="134.8">5.60</text>
<text x="70.6" y="134.8">5.50</text>
<text x="77.6" y="134.8">5.60</text>
<text x="42.7" y="163.7">5.40</text>
<text x="42.7" y="167.9">5.40</text>
<text x="49.7" y="163.7">5.50</text>
<text x="49.7" y="167.9">5.50</text>
<text x="56.8" y="163.7">5.60</text>
<text x="56.8" y="167.9">5.60</text>
<text x="63.9" y="163.7">5.40</text>
<text x="63.9" y="167.9">5.40</text>
<text x="70.6" y="163.7">5.50</text>
<text x="70.6" y="167.9">5.50</text>
<text x="77.6" y="163.7">5.60</text>
<text x="77.6" y="167.9">5.60</text>
<text x="42.7" y="172.2">5.40</text>
<text x="49.7" y="172.2">5.50</text>
<text x="56.8" y="172.2">5.60</text>
<text x="63.9" y="172.2">5.40</text>
<text x="70.6" y="172.2">5.50</text>
<text x="77.6" y="172.2">5.60</text>
<text x="26.1" y="185.6">T5677+3</text>
<text x="42.7" y="185.6">5.40</text>
<text x="49.7" y="185.6">5.50</text>
<text x="56.8" y="185.6">5.60</text>
<text x="63.9" y="185.6">5.40</text>
<text x="70.6" y="185.6">5.50</text>
<text x="77.6" y="185.6">5.60</text>
<text x="26.1" y="190.1">T5677+4</text>
<text x="42.7" y="190.1">4.50</text>
<text x="49.7" y="190.1">4.60</text>
<text x="56.8" y="190.1">4.70</text>
<text x="63.9" y="190.1">4.50</text>
<text x="70.6" y="190.1">4.60</text>
<text x="77.6" y="190.1">4.70</text>
</g>
<g font-size="4.4">
<text x="97.7" y="35.6">CORNER LEAD</text>
<text x="26.1" y="41.6">PKG.</text>
<text x="50.8" y="40.6">D2</text>
<text x="71.6" y="40.6">E2</text>
<text x="85.4" y="40.2">JEDEC</text>
<text x="100.5" y="38.1">CHAMFER</text>
<text x="50.1" y="45.2">NOM.</text>
<text x="70.9" y="45.2">NOM.</text>
<text x="78" y="45.2">MAX.</text>
<text x="85.4" y="42.7">MO220</text>
<text x="42.7" y="49.4">4.55</text>
<text x="42.7" y="53.6">4.55</text>
<text x="49.7" y="49.4">4.70</text>
<text x="49.7" y="53.6">4.70</text>
<text x="56.8" y="49.4">4.85</text>
<text x="56.8" y="53.6">4.85</text>
<text x="63.9" y="49.4">4.55</text>
<text x="63.9" y="53.6">4.55</text>
<text x="70.6" y="49.4">4.70</text>
<text x="70.6" y="53.6">4.70</text>
<text x="77.6" y="49.4">4.85</text>
<text x="77.6" y="53.6">4.85</text>
<text x="130.5" y="52.6">SYMBOL</text>
<text x="148.2" y="52.6">NOM.</text>
<text x="155.6" y="52.6">MAX.</text>
<text x="170" y="52.6">NOM.</text>
<text x="177.4" y="52.6">MAX.</text>
<text x="191.9" y="52.6">NOM.</text>
<text x="199.3" y="52.6">MAX.</text>
<text x="213.8" y="52.6">NOM.</text>
<text x="221.2" y="52.6">MAX.</text>
<text x="235.7" y="52.6">NOM.</text>
<text x="243.1" y="52.6">MAX.</text>
<text x="42.7" y="57.9">4.55</text>
<text x="49.7" y="57.9">4.70</text>
<text x="56.8" y="57.9">4.85</text>
<text x="63.9" y="57.9">4.55</text>
<text x="70.6" y="57.9">4.70</text>
<text x="77.6" y="57.9">4.85</text>
<text x="42.7" y="62.1">4.55</text>
<text x="49.7" y="62.1">4.70</text>
<text x="56.8" y="62.1">4.85</text>
<text x="63.9" y="62.1">4.55</text>
<text x="70.6" y="62.1">4.70</text>
<text x="77.6" y="62.1">4.85</text>
<text x="148.5" y="62.8">0.02</text>
<text x="155.6" y="62.8">0.05</text>
<text x="170" y="62.8">0.02</text>
<text x="177.1" y="62.8">0.05</text>
<text x="191.9" y="62.8">0.02</text>
<text x="199" y="62.8">0.05</text>
<text x="213.4" y="62.8">0.02</text>
<text x="220.8" y="62.8">0.05</text>
<text x="242.7" y="62.8">0.05</text>
<text x="26.1" y="70.6">T4477+2</text>
<text x="26.1" y="66.3">T3277M+3</text>
<text x="42.7" y="70.6">4.55</text>
<text x="42.7" y="66.3">4.55</text>
<text x="49.7" y="70.6">4.70</text>
<text x="49.7" y="66.3">4.70</text>
<text x="56.8" y="70.6">4.85</text>
<text x="56.8" y="66.3">4.85</text>
<text x="63.9" y="70.6">4.55</text>
<text x="63.9" y="66.3">4.55</text>
<text x="70.6" y="70.6">4.70</text>
<text x="70.6" y="66.3">4.70</text>
<text x="77.6" y="70.6">4.85</text>
<text x="77.6" y="66.3">4.85</text>
<text x="84.7" y="70.6">WKKD-1</text>
<text x="26.1" y="74.8">T4477+2C</text>
<text x="42.7" y="74.8">4.55</text>
<text x="49.7" y="74.8">4.70</text>
<text x="56.8" y="74.8">4.85</text>
<text x="63.9" y="74.8">4.55</text>
<text x="70.6" y="74.8">4.70</text>
<text x="77.6" y="74.8">4.85</text>
<text x="84.7" y="74.8">WKKD-1</text>
<text x="140.8" y="75.8">6.90</text>
<text x="162.6" y="75.8">6.90</text>
<text x="184.1" y="75.8">6.90</text>
<text x="206.4" y="75.8">6.90</text>
<text x="228.2" y="75.8">6.90</text>
<text x="26.1" y="83.3">T4877+3</text>
<text x="42.7" y="79">4.55</text>
<text x="49.7" y="79">4.70</text>
<text x="56.8" y="79">4.85</text>
<text x="63.9" y="79">4.55</text>
<text x="70.6" y="79">4.70</text>
<text x="77.6" y="79">4.85</text>
<text x="84.7" y="79">WKKD-1</text>
<text x="148.2" y="80.4">7.00</text>
<text x="155.6" y="80.4">7.10</text>
<text x="170" y="80.4">7.00</text>
<text x="177.1" y="80.4">7.10</text>
<text x="191.9" y="80.4">7.00</text>
<text x="199" y="80.4">7.10</text>
<text x="213.4" y="80.4">7.00</text>
<text x="220.8" y="80.4">7.10</text>
<text x="235.3" y="80.4">7.00</text>
<text x="242.7" y="80.4">7.10</text>
<text x="26.1" y="92.1">T4877+4</text>
<text x="141.1" y="93.5">0.45</text>
<text x="155.6" y="93.5">0.65</text>
<text x="162.6" y="93.5">0.45</text>
<text x="177.1" y="93.5">0.65</text>
<text x="184.5" y="93.5">0.30</text>
<text x="199" y="93.5">0.50</text>
<text x="206.4" y="93.5">0.45</text>
<text x="220.8" y="93.5">0.65</text>
<text x="228.2" y="93.5">0.30</text>
<text x="242.7" y="93.5">0.50</text>
<text x="42.7" y="96.3">5.40</text>
<text x="49.7" y="96.3">5.50</text>
<text x="56.8" y="96.3">5.60</text>
<text x="63.9" y="96.3">5.40</text>
<text x="70.6" y="96.3">5.50</text>
<text x="77.6" y="96.3">5.60</text>
<text x="26.1" y="104.4">T4877+6C</text>
<text x="42.7" y="104.4">5.40</text>
<text x="49.7" y="104.4">5.50</text>
<text x="56.8" y="104.4">5.60</text>
<text x="63.9" y="104.4">5.40</text>
<text x="70.6" y="104.4">5.50</text>
<text x="77.6" y="104.4">5.60</text>
<text x="171.1" y="102.7">11</text>
<text x="193" y="102.7">12</text>
<text x="214.5" y="102.7">10</text>
<text x="236.4" y="102.7">14</text>
<text x="26.1" y="112.5">T4877-7C</text>
<text x="42.7" y="112.5">4.95</text>
<text x="49.7" y="112.5">5.10</text>
<text x="56.8" y="112.5">5.25</text>
<text x="63.9" y="112.5">4.95</text>
<text x="70.6" y="112.5">5.10</text>
<text x="77.6" y="112.5">5.25</text>
<text x="26.1" y="116.8">T4877+10</text>
<text x="42.7" y="117.1">5.40</text>
<text x="49.7" y="117.1">5.50</text>
<text x="56.8" y="117.1">5.60</text>
<text x="63.9" y="117.1">5.40</text>
<text x="70.6" y="117.1">5.50</text>
<text x="77.6" y="117.1">5.60</text>
<text x="42.7" y="121.4">5.40</text>
<text x="42.7" y="125.9">5.40</text>
<text x="49.7" y="121.4">5.50</text>
<text x="49.7" y="125.9">5.50</text>
<text x="56.8" y="121.4">5.60</text>
<text x="56.8" y="125.9">5.60</text>
<text x="63.9" y="121.4">5.40</text>
<text x="63.9" y="125.9">5.40</text>
<text x="70.6" y="121.4">5.50</text>
<text x="70.6" y="125.9">5.50</text>
<text x="77.6" y="121.4">5.60</text>
<text x="77.6" y="125.9">5.60</text>
<text x="42.7" y="137.9">5.40</text>
<text x="49.7" y="137.9">5.50</text>
<text x="56.8" y="137.9">5.60</text>
<text x="63.9" y="137.9">5.40</text>
<text x="70.6" y="137.9">5.50</text>
<text x="77.6" y="137.9">5.60</text>
<text x="26.1" y="142.2">T4877M+6</text>
<text x="42.7" y="142.2">5.40</text>
<text x="49.7" y="142.2">5.50</text>
<text x="56.8" y="142.2">5.60</text>
<text x="63.9" y="142.2">5.40</text>
<text x="70.6" y="142.2">5.50</text>
<text x="77.6" y="142.2">5.60</text>
<text x="26.1" y="146.4">T4877MN+8</text>
<text x="42.7" y="146.4">5.40</text>
<text x="49.7" y="146.4">5.50</text>
<text x="56.8" y="146.4">5.60</text>
<text x="63.9" y="146.4">5.40</text>
<text x="70.6" y="146.4">5.50</text>
<text x="77.6" y="146.4">5.60</text>
<text x="26.1" y="150.6">T4877N+8</text>
<text x="26.1" y="154.9">T4877+9C</text>
<text x="42.7" y="150.6">5.40</text>
<text x="42.7" y="154.9">3.92</text>
<text x="49.7" y="150.6">5.50</text>
<text x="49.7" y="154.9">4.02</text>
<text x="56.8" y="150.6">5.60</text>
<text x="56.8" y="154.9">4.12</text>
<text x="63.5" y="154.9">3.92</text>
<text x="63.9" y="150.6">5.40</text>
<text x="70.6" y="150.6">5.50</text>
<text x="70.9" y="154.9">4.02</text>
<text x="77.6" y="150.6">5.60</text>
<text x="77.6" y="154.9">4.12</text>
<text x="26.1" y="159.1">T4877+9CA</text>
<text x="42.7" y="159.1">3.92</text>
<text x="49.7" y="159.1">4.02</text>
<text x="56.8" y="159.1">4.12</text>
<text x="63.5" y="159.1">3.92</text>
<text x="70.9" y="159.1">4.02</text>
<text x="77.6" y="159.1">4.12</text>
<text x="26.1" y="163.3">T5677+1</text>
<text x="26.1" y="167.6">T5677+1C</text>
<text x="26.1" y="176.4">T5677+2</text>
<text x="42.7" y="176.4">5.40</text>
<text x="49.7" y="176.4">5.50</text>
<text x="56.8" y="176.4">5.60</text>
<text x="63.9" y="176.4">5.40</text>
<text x="70.6" y="176.4">5.50</text>
<text x="77.6" y="176.4">5.60</text>
<text x="26.1" y="180.6">T5677+2C</text>
<text x="42.7" y="180.6">5.40</text>
<text x="49.7" y="180.6">5.50</text>
<text x="56.8" y="180.6">5.60</text>
<text x="63.9" y="180.6">5.40</text>
<text x="70.6" y="180.6">5.50</text>
<text x="77.6" y="180.6">5.60</text>
<text x="186.6" y="201.1">APPROVAL</text>
</g>
<text font-size="4" x="133" y="84.7">e</text>
<g font-size="2.6">
<text x="87.5" y="48.7">-</text>
<text x="87.5" y="52.9">-</text>
<text x="104.4" y="48.3">-</text>
<text x="104.4" y="52.6">-</text>
<text x="87.5" y="57.2">-</text>
<text x="104.4" y="57.2">-</text>
<text x="87.5" y="65.6">-</text>
<text x="87.5" y="61.4">-</text>
<text x="104.4" y="61.4">-</text>
<text x="104.4" y="66">-</text>
<text x="237.4" y="62.1">-</text>
<text x="104.4" y="69.8">-</text>
<text x="104.4" y="74.1">-</text>
<text x="104.4" y="78">-</text>
<text x="87.5" y="82.9">-</text>
<text x="87.5" y="87.1">-</text>
<text x="149.9" y="88.5">-</text>
<text x="157.3" y="88.5">-</text>
<text x="171.8" y="88.5">-</text>
<text x="179.2" y="88.5">-</text>
<text x="193.7" y="88.5">-</text>
<text x="201.1" y="88.5">-</text>
<text x="215.5" y="88.5">-</text>
<text x="223" y="88.5">-</text>
<text x="237.4" y="88.5">-</text>
<text x="244.8" y="88.5">-</text>
<text x="87.5" y="95.6">-</text>
<text x="87.5" y="91.4">-</text>
<text x="87.5" y="99.8">-</text>
<text x="87.5" y="107.9">-</text>
<text x="87.5" y="103.7">-</text>
<text x="87.5" y="111.8">-</text>
<text x="87.5" y="116.4">-</text>
<text x="87.5" y="120.6">-</text>
<text x="87.5" y="125.2">-</text>
<text x="87.5" y="129.5">-</text>
<text x="87.5" y="137.2">-</text>
<text x="87.5" y="133.7">-</text>
<text x="87.5" y="141.5">-</text>
<text x="87.5" y="145.7">-</text>
<text x="87.5" y="149.9">-</text>
<text x="87.5" y="154.2">-</text>
<text x="87.5" y="158.4">-</text>
<text x="87.5" y="163">-</text>
<text x="87.5" y="167.2">-</text>
<text x="104.4" y="163">-</text>
<text x="104.4" y="167.2">-</text>
<text x="87.5" y="171.4">-</text>
<text x="104.4" y="171.4">-</text>
<text x="87.5" y="175.7">-</text>
<text x="104.4" y="175.7">-</text>
<text x="87.5" y="180.3">-</text>
<text x="87.5" y="184.5">-</text>
<text x="104.4" y="180.3">-</text>
<text x="104.4" y="184.5">-</text>
<text x="87.5" y="189.1">-</text>
<text x="104.4" y="189.1">-</text>
</g>
</g></defs>
<!-- layer: 0 -->
<g fill="none" stroke="#000" stroke-width=".25">
<path d="M26.3 36.3h70.5M26.3 28.4h91.1v161.7h-91.1zM43 36.3v153.8M43.2 32.6h.6M44.1 31.9h-.9v1.6h.9M44.4 31.9l.9 1.6M45.3 31.9l-.9 1.6M45.8 32.7h.6a.44 .44 0 0 0 .3-.4 .44 .44 0 0 0-.3-.4h-.6v1.6M47.4 31.9a.72 .72 0 0 1 .7 .3 .72 .72 0 0 1 0 .9 .5 .5 0 0 1-.6 .4 .5 .5 0 0 1-.4-.6v-.4zM49.5 32.1a.49 .49 0 0 0-.6-.3 .49 .49 0 0 0-.4 .4l.2 .3 .6 .3 .2 .4a.54 .54 0 0 1-1 0M49.9 32.6h.5M50.8 31.9h-.9v1.6h.9"/>
<path d="M51.2 31.9a.87 .87 0 0 1 .9 .5 .87 .87 0 0 1-.3 1l-.6 .1zM53.9 32.7h.6a.44 .44 0 0 0 .3-.4 .44 .44 0 0 0-.3-.4h-.6v1.6M55.1 33.5l.5-1.6 .5 1.6M55.3 32.9h.7M56.5 31.9a.82 .82 0 0 1 .9 .8 .82 .82 0 0 1-.9 .8zM59 31.9l.5 1.6 .6-1.6M60.2 33.5l.5-1.6 .5 1.6M60.4 32.9h.7M61.6 32.6h.8l.1-.3-.1-.4h-.8v1.6M62 32.6l.5 .9M63 31.9v1.6M63.3 33.5l.5-1.6 .5 1.6"/>
<path d="M63.5 32.9h.6M63.9 36.3v153.8M64.5 31.9h.9M64.9 31.9v1.6M65.7 31.9v1.6M66.4 31.9a.72 .72 0 0 1 .8 .3 .72 .72 0 0 1-.1 .9 .5 .5 0 0 1-.6 .4 .5 .5 0 0 1-.3-.6v-.4zM68.6 31.9v1.6l-.9-1.6v1.6M70 32.1a.49 .49 0 0 0-.5-.3 .49 .49 0 0 0-.4 .4l.1 .3 .6 .3 .2 .4a.54 .54 0 0 1-.9 0M84.8 36.3v153.8M96.8 28.4v161.7M130.7 28.4h119.4v78.5h-119.4zM130.7 36.3h119.4"/>
<path d="M140.8 36.3v70.6M162.7 36.3v70.6M174.5 31.7a.51 .51 0 0 0-.6-.4 .51 .51 0 0 0-.4 .6v.4a.51 .51 0 0 0 .4 .6 .51 .51 0 0 0 .6-.4M175.1 31.4a.72 .72 0 0 1 .8 .3 .72 .72 0 0 1 0 .8 .51 .51 0 0 1-.7 .4 .51 .51 0 0 1-.3-.6v-.6zM176.4 32.9v-1.6l.5 1.6 .5-1.6v1.6M178 32.9v-1.6l.5 1.6 .5-1.6v1.6M179.7 31.4a.76 .76 0 0 1 .8 .4 .76 .76 0 0 1-.1 .9l-.2 .1a.72 .72 0 0 1-.7-.3 .72 .72 0 0 1 0-.8zM181.9 31.3v1.6l-.9-1.6v1.6M183.8 31.3a.82 .82 0 0 1 .9 .8 .82 .82 0 0 1-.9 .8zM184.5 36.3v70.6M185.2 31.3v1.6M185.7 32.9v-1.6l.5 1.6 .5-1.6v1.6"/>
<path d="M187.3 32.1h.5M188.1 31.3h-.8v1.6h.8M189.4 31.3v1.6l-.9-1.6v1.6M190.8 31.5a.46 .46 0 0 0-.6-.2 .46 .46 0 0 0-.3 .5l.8 .4 .1 .5a.56 .56 0 0 1-.9 0M191.2 31.3v1.6M192 31.4a.76 .76 0 0 1 .8 .4 .76 .76 0 0 1-.2 .9l-.1 .1a.72 .72 0 0 1-.8-.3 .72 .72 0 0 1 .1-.8zM194.1 31.3v1.6l-.9-1.6v1.6M195.5 31.5a.46 .46 0 0 0-.5-.2 .46 .46 0 0 0-.3 .5l.7 .4a.39 .39 0 0 1 .1 .4 .39 .39 0 0 1-.3 .3l-.5-.1-.1-.1M206.4 36.3v70.6M211 38.4a.46 .46 0 0 0-.7-.3 .9 .9 0 0 0 .4 1.6l.3-.4M211.5 38v1.2a.46 .46 0 0 0 .4 .5 .46 .46 0 0 0 .5-.5v-1.2M213.7 38.3a.48 .48 0 0 0-.5-.3 .48 .48 0 0 0-.4 .4l.2 .3 .6 .3 .1 .4a.54 .54 0 0 1-.9 0"/>
<path d="M214 38h.9M214.5 38v1.7M215.5 38.1l.1-.1a.83 .83 0 0 1 .7 .9 .83 .83 0 0 1-.7 .8 1.02 1.02 0 0 1-.1-1.6zM216.7 39.7v-1.7l.5 1.7 .5-1.7v1.7M219.7 38.9l.7-.1 .2-.2-.2-.5-.7-.1v1.7M221 38v1.7M221.3 38.7l.6 1M221.9 38l-.9 1.1M223.3 38.4a.46 .46 0 0 0-.7-.3 .9 .9 0 0 0 .4 1.6l.3-.4v-.2h-.3M223.8 39.6h.1zM228.2 36.3v70.6M26.3 45.1h91.1"/>
<path d="M26.3 49.3h91.1M26.3 57.8h91.1M26.3 53.6h91.1M43 40.8h41.8M44.9 44v-1.6l.5 1.6 .5-1.6v1.6M46.5 42.4v1.6M47.9 42.4v1.6l-.9-1.6v1.6M48.4 43.9h.2zM49.9 40.8v149.3M56.9 40.8v149.3M58.6 44v-1.6l.5 1.6 .5-1.6v1.6M60 44l.5-1.6 .5 1.6"/>
<path d="M60.1 43.4h.7M61.3 42.4l.9 1.6M62.2 42.4l-.9 1.6M62.7 43.8v.2zM65.6 44v-1.6l.6 1.6 .5-1.6v1.6M67.2 42.4v1.6M68.6 42.4v1.6l-.9-1.6v1.6M69.2 43.8v.2zM70.9 40.8v149.3M77.8 40.8v149.3M130.7 57.4h119.4M130.7 53.1h119.4"/>
<path d="M130.7 52.5h119.4M130.7 48.4h119.4M135 56.2l.7-1.6 .6 1.6M135.3 55.7h.7M142.6 51.5v-1.6l.5 1.6 .5-1.6v1.6M144.1 49.9v1.6M145.6 49.9v1.6l-.9-1.6v1.6M146.2 51.3v.2zM147.9 45.1h.7l-.4 .6a.49 .49 0 0 1 .4 .8 .49 .49 0 0 1-.8-.1M148.1 48.4v14.1M149.1 45.5l.3-.4 .4 .1 .1 .2-.2 .6-.6 .7h.9M150.5 45.1v1.6h.7"/>
<path d="M152.9 45.1h.9l-.7 1.6M154.2 45.7l.7 1M154.9 45.7l-.7 1M155.3 45.1h.9l-.6 1.6M155.4 48.4v14.1M164.4 51.5v-1.6l.5 1.6 .6-1.6v1.6M166 49.9v1.6M167.4 49.9v1.6l-.9-1.6v1.6M168 51.3v.2zM170 48.4v14.1M170.1 46.2h-1l.7-1.1v1.6M171.4 46.2h-1l.7-1.1v1.6"/>
<path d="M171.8 45.1v1.6h.8M174.2 45.1h.9l-.6 1.6M175.5 45.7l.7 1M176.2 45.7l-.7 1M176.6 45.1h1l-.7 1.6M177.2 48.4v14.1M186.3 51.5v-1.6l.5 1.6 .5-1.6v1.6M187.9 49.9v1.6M189.3 49.9v1.6l-.9-1.6v1.6M189.8 51.4h.2zM191.8 48.4v14.1M192 46.2h-1l.7-1.1v1.6"/>
<path d="M192.5 45.2a.34 .34 0 0 0 .1 .5 .52 .52 0 0 1 .7 .7 .52 .52 0 0 1-.9 .2l-.1-.2a.76 .76 0 0 1 .8-.7l.1-.3a.49 .49 0 0 0-.7-.2zM193.7 45.1v1.6h.8M196.2 45.1h.9l-.7 1.6M197.5 45.7l.7 1M198.2 45.7l-.7 1M198.6 45.1h.9l-.7 1.6M199.1 48.4v14.1M208.1 51.5v-1.6l.6 1.6 .5-1.6v1.6M209.7 49.9v1.6M211.1 49.9v1.6l-.9-1.6v1.6M211.7 51.3v.2zM213.3 40.5a1.93 1.93 0 0 0 0 2.5"/>
<path d="M213.6 40.8h.9M213.7 48.4v14.1M213.7 46.2h-.9l.6-1.1v1.6M214 40.8v1.6M214.2 45.2v.5a.65 .65 0 0 1 .7 .3 .65 .65 0 0 1 0 .7 .53 .53 0 0 1-.8-.4 .53 .53 0 0 1 .6-.6l.2-.3a.49 .49 0 0 0-.7-.2zM215.5 45.1v1.6h.7M215.7 41.9h-1l.7-1.1v1.6M216.2 40.9v.5a.64 .64 0 0 1 .6 .2 .64 .64 0 0 1 0 .8 .52 .52 0 0 1-.8-.4 .52 .52 0 0 1 .7-.5l.2-.5a.51 .51 0 0 0-.7-.1zM217.3 40.8h1l-.7 1.6M217.9 45.1h.9l-.6 1.6M218.7 40.8h.9l-.7 1.6M219.2 45.7l.7 1"/>
<path d="M219.9 45.7l-.7 1M220 41.7h1.2M220.3 45.1h.9l-.6 1.6M220.6 41v1.4M221 48.4v14.1M221.9 41.1l.3-.3v1.6M223 40.5a1.93 1.93 0 0 1 0 2.5M230 51.5v-1.6l.5 1.6 .5-1.6v1.6M231.6 49.9v1.6M233 49.9v1.6l-.9-1.6v1.6M233.6 51.3v.2zM235.4 45.1h-.6l-.1 .7a.51 .51 0 0 1 .7 .1 .51 .51 0 0 1-.1 .7 .51 .51 0 0 1-.7-.2"/>
<path d="M235.5 48.4v14.1M236.8 45.4l-.1-.2-.3-.1a.91 .91 0 0 0 .1 1.6 .46 .46 0 0 0 .4-.4 .46 .46 0 0 0-.4-.5 .46 .46 0 0 0-.5 .4M237.3 45.1v1.6h.8M239.7 45.1h1l-.7 1.6M241.1 45.7l.7 1M241.8 45.7l-.7 1M242.2 45.1h.9l-.7 1.6M242.8 48.4v14.1M26.3 74.8h91.1M26.3 79.1h91.1M26.3 70.6h91.1M26.3 66.3h91.1"/>
<path d="M26.3 62.1h91.1M130.7 67h119.4M130.7 75.4h119.4M130.7 71.5h119.4M130.7 79.9h119.4M130.7 62.5h119.4M134.5 72.9h.5a.87 .87 0 0 1 .6 .9 .87 .87 0 0 1-.6 .8h-.5zM134.5 78.1h.6M134.6 69.7a.52 .52 0 0 1 .8 0 .52 .52 0 0 1 0 .7 .52 .52 0 0 1-.8-.1M134.6 69v1.6M135.5 77.4h-1v1.6h1M143.6 60.1a.5 .5 0 0 1 .8 .2 .76 .76 0 0 1 .1 .9 .76 .76 0 0 1-.9 .3l-.2-.6 .1-.6z"/>
<path d="M147.2 64.4a.54 .54 0 0 1 .7 .2 .81 .81 0 0 1-.5 1.3 1.03 1.03 0 0 1-.2-1.5zM148.1 67v12.9M148.6 65.8l-.1 .1h.1M149.3 64.7l.3-.4 .6 .2a.49 .49 0 0 1-.2 .7l-.8 .7h1.1M151 64.4a.57 .57 0 0 1 .8 .2v1a.51 .51 0 0 1-.5 .3 .51 .51 0 0 1-.4-.3 1.32 1.32 0 0 1 .1-1.2zM153.8 65.1l.9-.1 .2-.2-.1-.3-.3-.2h-.7v1.6M154.3 65.1l.6 .8M155.4 67v12.9M155.4 65.1h.6M156.4 64.3h-1v1.6h1M156.8 73.2h1.1l-.8 1.6M156.9 65.1h.6"/>
<path d="M157.9 64.3h-1v1.6M158.3 65.8v.1h.1M158.4 74.6v.1h.1M159.1 73.5l.4-.3v1.6M160.6 73.3a.5 .5 0 0 1 .8 .2 .76 .76 0 0 1 0 .9 .76 .76 0 0 1-.8 .3 1.24 1.24 0 0 1 0-1.4zM165.5 60.1a.5 .5 0 0 1 .8 .2 .76 .76 0 0 1 0 .9 .76 .76 0 0 1-.8 .3l-.2-.6v-.6zM169.3 64.4a.56 .56 0 0 1 .8 .2l.1 .4a.71 .71 0 0 1-.5 .9h-.1a1.03 1.03 0 0 1-.3-1.5zM170 67v12.9M170.7 65.8l-.1 .1h.2M171.5 64.7l.3-.4 .5 .2a.49 .49 0 0 1-.1 .7l-.8 .7h1.1M173.2 64.4a.56 .56 0 0 1 .8 .2v.4a.71 .71 0 0 1-.4 .9h-.2a.87 .87 0 0 1-.4-1.3zM176 65.1l.9-.1 .1-.4-.1-.2-.9-.1v1.6"/>
<path d="M176.5 65.1l.5 .8M177.2 67v12.9M177.6 65.1h.6M178.4 73.2h1.1l-.8 1.6M178.6 64.3h-1v1.6h1M179 65.1h.6M180 74.6l-.1 .1h.2M180.1 64.3h-1.1v1.6M180.5 65.8v.1h.1M180.7 73.5l.4-.3v1.6M182.2 73.3a.5 .5 0 0 1 .7 .2 .76 .76 0 0 1 .1 .9 .76 .76 0 0 1-.8 .3 1.24 1.24 0 0 1 0-1.4zM187.1 60.1a.5 .5 0 0 1 .8 .2 .76 .76 0 0 1 0 .9 .76 .76 0 0 1-.8 .3l-.2-.6v-.6z"/>
<path d="M191.2 64.4a.54 .54 0 0 1 .8 .2 .81 .81 0 0 1-.6 1.3 1.03 1.03 0 0 1-.2-1.5zM191.8 67v12.9M192.6 65.8l-.1 .1h.2M193.4 64.7l.3-.4 .5 .2a.49 .49 0 0 1-.1 .7l-.8 .7h1.1M195.1 64.4a.54 .54 0 0 1 .7 .2 .81 .81 0 0 1-.5 1.3 1.03 1.03 0 0 1-.2-1.5zM197.8 65.1l1-.1 .1-.2-.1-.3-.3-.2h-.7v1.6M198.4 65.1l.5 .8M199.1 67v12.9M199.5 65.1h.6M200.1 73.2h1.1l-.8 1.6M200.5 64.3h-1v1.6h1M200.9 65.1h.6"/>
<path d="M201.7 74.6v.1h.1M201.9 64.3h-1v1.6M202.4 65.8l-.1 .1h.2M202.4 73.5l.4-.3v1.6M203.9 73.3a.5 .5 0 0 1 .8 .2 .76 .76 0 0 1 0 .9 .76 .76 0 0 1-.8 .3 1.24 1.24 0 0 1 0-1.4zM209.1 60.1a.5 .5 0 0 1 .8 .2 .76 .76 0 0 1 0 .9 .76 .76 0 0 1-.8 .3l-.2-.6v-.6zM212.8 64.4a.54 .54 0 0 1 .8 .2 .81 .81 0 0 1-.6 1.3 1.03 1.03 0 0 1-.2-1.5zM213.7 67v12.9M214.2 65.8l-.1 .1h.2M215 64.7l.3-.4 .5 .2a.49 .49 0 0 1-.1 .7l-.8 .7h1M216.6 64.4a.57 .57 0 0 1 .8 .2v1a.51 .51 0 0 1-.4 .3 .51 .51 0 0 1-.5-.3 1.32 1.32 0 0 1 .1-1.2zM219.4 65.1l1-.1 .1-.2-.1-.3-.3-.2h-.7v1.6"/>
<path d="M220 65.1l.5 .8M221 67v12.9M221.1 65.1h.6M222 64.3h-.9v1.6h.9M222.1 73.2h1.1l-.8 1.6M222.5 65.1h.6M223.5 64.3h-1v1.6M223.8 74.6l-.1 .1h.1M224 65.8l-.1 .1h.2M224.5 73.5l.3-.3v1.6M225.9 73.3a.5 .5 0 0 1 .8 .2 .76 .76 0 0 1 .1 .9 .76 .76 0 0 1-.9 .3 1.24 1.24 0 0 1 0-1.4zM229.6 69a.53 .53 0 0 1 .8 .3v.3a.69 .69 0 0 1-.6 1 1.03 1.03 0 0 1-.2-1.6z"/>
<path d="M231 60.1a.52 .52 0 0 1 .7 .2l.1 .4a.69 .69 0 0 1-.6 .9 1.03 1.03 0 0 1-.2-1.5zM231 70.4l-.1 .1h.2M231.7 69.3l.4-.4v1.7M233.9 68.9h-.8l-.1 .7a.57 .57 0 0 1 .9 0 .57 .57 0 0 1-.1 .9 .57 .57 0 0 1-.9-.2M234.7 64.4a.54 .54 0 0 1 .7 .2 .81 .81 0 0 1-.5 1.3l-.4-.3-.1-.4 .1-.6zM235.5 67v12.9M236 65.8v.1h.1M236.8 64.7l.3-.4 .5 .1 .1 .2-.2 .6-.8 .7h1.1M238.5 64.4a.54 .54 0 0 1 .8 .2 .81 .81 0 0 1-.6 1.3 1.03 1.03 0 0 1-.2-1.5zM241.3 65.1l.9-.1 .2-.4-.2-.2-.9-.1v1.6M241.8 65.1l.6 .8M242.8 67v12.9"/>
<path d="M242.9 65.1h.6M243.9 64.3h-1v1.6h1M244 73.2h1.1l-.8 1.6M244.4 65.1h.6M245.4 64.3h-1v1.6M245.6 74.6l-.1 .1h.2M245.8 65.8v.1h.1M246.3 73.5l.4-.3v1.6M247.8 73.3a.5 .5 0 0 1 .7 .2 .76 .76 0 0 1 .1 .9 .76 .76 0 0 1-.8 .3l-.2-.6v-.6zM26.3 96.3h91.1M26.3 83.3h91.1M26.3 92.2h91.1"/>
<path d="M26.3 87.6h91.1M52 80.6h-.8l-.1 .7a.57 .57 0 0 1 .9 0 .57 .57 0 0 1-.1 .9 .57 .57 0 0 1-.8-.3M52 84.9h-.8l-.1 .7a.57 .57 0 0 1 .9 0 .57 .57 0 0 1-.1 .8 .57 .57 0 0 1-.8-.2M52.7 82.1l-.1 .1h.2M52.7 86.3l-.1 .1h.2M53.4 80.9l.4-.3v1.6M53.4 85.2l.4-.3v1.6M54.8 80.7a.5 .5 0 0 1 .8 .2 .76 .76 0 0 1 .1 .9 .76 .76 0 0 1-.9 .4 1.24 1.24 0 0 1 0-1.5zM54.8 84.9a.54 .54 0 0 1 .8 .3 .81 .81 0 0 1-.5 1.3 1.03 1.03 0 0 1-.3-1.6zM98.9 89.4a.52 .52 0 0 1 .8 .2l.1 .4a.69 .69 0 0 1-.6 1 1.03 1.03 0 0 1-.3-1.6zM98.9 93.8a.56 .56 0 0 1 .8 .3v1a.51 .51 0 0 1-.4 .3 .51 .51 0 0 1-.5-.3 1.34 1.34 0 0 1 .1-1.3zM98.9 85.4a.53 .53 0 0 1 .8 .2l.1 .4a.7 .7 0 0 1-.5 1h-.1a1.01 1.01 0 0 1-.3-1.6z"/>
<path d="M98.9 97.8a.52 .52 0 0 1 .8 .3l.1 .4a.69 .69 0 0 1-.6 .9 1.03 1.03 0 0 1-.3-1.6zM98.9 81a.52 .52 0 0 1 .8 .2l.1 .4a.69 .69 0 0 1-.6 .9 1.03 1.03 0 0 1-.3-1.5zM100.3 90.8v.1h.1M100.3 95.2v.1h.1M100.3 86.8v.1h.1M100.3 99.2v.1h.1M100.3 82.3v.1h.1M101 89.6l.4-.3v1.7M101 94.1l.4-.3v1.6M101 85.6l.4-.2v1.6M101 98.1l.4-.3v1.6M101 81.2l.4-.3v1.6"/>
<path d="M102.3 89.6l.3-.3v1.7M102.3 94.1l.3-.3v1.6M102.3 85.6l.3-.2v1.6M102.3 98.1l.3-.3v1.6M102.3 81.2l.3-.3v1.6M104.4 89.3h-.7l-.1 .7a.57 .57 0 0 1 .8 0 .57 .57 0 0 1-.1 .9 .57 .57 0 0 1-.8-.3M104.4 93.8h-.7l-.1 .7a.57 .57 0 0 1 .8 0 .57 .57 0 0 1-.1 .8 .57 .57 0 0 1-.8-.2M104.4 85.4h-.7l-.1 .6a.57 .57 0 0 1 .8 0 .57 .57 0 0 1-.1 .9 .57 .57 0 0 1-.8-.2M104.4 97.8h-.7l-.1 .7a.57 .57 0 0 1 .8 0 .57 .57 0 0 1-.1 .8 .57 .57 0 0 1-.8-.2M104.4 80.9h-.7l-.1 .7a.57 .57 0 0 1 .8 0 .57 .57 0 0 1-.1 .8 .57 .57 0 0 1-.8-.2M106.5 89.3l1.1 1.7M106.5 93.8l1.1 1.6"/>
<path d="M106.5 85.4l1.1 1.6M106.5 97.8l1.1 1.6M106.5 80.9l1.1 1.6M107.6 89.3l-1.1 1.7M107.6 93.8l-1.1 1.6M107.6 85.4l-1.1 1.6M107.6 97.8l-1.1 1.6M107.6 80.9l-1.1 1.6M110.7 90.4h-1.2l.8-1.1v1.7M110.7 94.9h-1.2l.8-1.1v1.6M110.7 86.4h-1.2l.8-1v1.6M110.7 98.8h-1.2l.8-1v1.6"/>
<path d="M110.7 82h-1.2l.8-1.1v1.6M112 89.3h-.8l-.1 .7a.57 .57 0 0 1 .9 0 .57 .57 0 0 1-.1 .9 .57 .57 0 0 1-.9-.3M112 93.8h-.8l-.1 .7a.57 .57 0 0 1 .9 0 .57 .57 0 0 1-.1 .8 .57 .57 0 0 1-.9-.2M112 85.4h-.8l-.1 .6a.57 .57 0 0 1 .9 0 .57 .57 0 0 1-.1 .9 .57 .57 0 0 1-.9-.2M112 97.8h-.8l-.1 .7a.57 .57 0 0 1 .9 0 .57 .57 0 0 1-.1 .8 .57 .57 0 0 1-.9-.2M112 80.9h-.8l-.1 .7a.57 .57 0 0 1 .9 0 .57 .57 0 0 1-.1 .8 .57 .57 0 0 1-.9-.2M130.7 88.9h119.4M130.7 84.4h119.4M130.7 93.4h119.4M130.7 97.9h119.4M134.9 90.9v1.6h.9M134.9 86.5v1.6"/>
<path d="M135.2 87.4l.5 .7M135.6 87l-.7 .8M136 95.4v1.7l-1-1.7v1.7M147.1 81.8a.57 .57 0 0 1 .8 .2v1a.51 .51 0 0 1-.5 .3 .51 .51 0 0 1-.5-.3 1.32 1.32 0 0 1 .2-1.2zM148.1 84.4v9M148.5 83.2l-.1 .1h.1M150.1 82a.46 .46 0 0 0-.5-.3 .46 .46 0 0 0-.4 .3 .93 .93 0 0 0 .4 1.3 .5 .5 0 0 0 .6-.4 .5 .5 0 0 0-.5-.6 .5 .5 0 0 0-.6 .5M151.6 81.7h-.7l-.1 .7a.57 .57 0 0 1 .8 0 .57 .57 0 0 1-.1 .9 .57 .57 0 0 1-.8-.3M153.7 82.5l.9-.1 .2-.2-.1-.3-.3-.2h-.7v1.6h.7l.3-.1v-.6l-.3-.1M155.4 84.4v9M156.4 82a.61 .61 0 0 0-.6-.3 .61 .61 0 0 0-.5 .4l.2 .2 .8 .3a.38 .38 0 0 1 0 .7 .73 .73 0 0 1-1-.2M158 82.1a.59 .59 0 0 0-.7-.4 .59 .59 0 0 0-.4 .6v.4a.59 .59 0 0 0 .4 .6 .59 .59 0 0 0 .7-.3"/>
<path d="M158.6 83.2l-.1 .1h.1M169.2 81.8a.56 .56 0 0 1 .8 .2l.1 .4a.71 .71 0 0 1-.5 .9h-.1a1.03 1.03 0 0 1-.3-1.5zM170 84.4v9M170.6 83.2v.1h.1M172.2 81.7h-.7l-.1 .7a.58 .58 0 0 1 .9 0 .58 .58 0 0 1-.1 .8 .58 .58 0 0 1-.9-.2M173.1 81.8a.54 .54 0 0 1 .8 .2 .81 .81 0 0 1-.6 1.3 1.05 1.05 0 0 1-.2-1.5zM175.9 82.5l1-.2 .1-.3-.2-.2-.9-.1v1.6h.7l.4-.3a.43 .43 0 0 0-.4-.5M177.2 84.4v9M178.6 82a.61 .61 0 0 0-.6-.3 .61 .61 0 0 0-.5 .4l.1 .2 .8 .3a.38 .38 0 0 1 0 .7 .73 .73 0 0 1-.9-.2M180.2 82.1a.6 .6 0 0 0-.7-.4 .6 .6 0 0 0-.5 .6v.4a.6 .6 0 0 0 .5 .6 .6 .6 0 0 0 .7-.3M180.7 83.2v.1h.1M191.1 81.8a.54 .54 0 0 1 .8 .2 .81 .81 0 0 1-.5 1.3 1.03 1.03 0 0 1-.3-1.5z"/>
<path d="M191.8 84.4v9M192.5 83.2l-.1 .1h.2M194.1 81.7h-.7l-.1 .7a.57 .57 0 0 1 .8 0 .57 .57 0 0 1-.1 .9 .57 .57 0 0 1-.8-.3M195 81.8a.57 .57 0 0 1 .8 .2v1a.51 .51 0 0 1-.5 .3 .51 .51 0 0 1-.5-.3 1.32 1.32 0 0 1 .2-1.2zM197.7 82.5l1-.1 .1-.2v-.3l-.4-.2h-.7v1.6h.7l.4-.1v-.6l-.4-.1M199.1 84.4v9M200.5 82a.61 .61 0 0 0-.6-.3 .61 .61 0 0 0-.5 .4l.1 .2 .8 .3 .2 .5a.71 .71 0 0 1-1.1 0M202.1 82.1a.59 .59 0 0 0-.7-.4 .59 .59 0 0 0-.5 .6v.4a.59 .59 0 0 0 .5 .6 .59 .59 0 0 0 .7-.3M202.6 83.2l-.1 .1h.2M212.7 81.8a.54 .54 0 0 1 .8 .2 .81 .81 0 0 1-.6 1.3 1.03 1.03 0 0 1-.2-1.5zM213.7 84.4v9M214.1 83.2l-.1 .1h.2"/>
<path d="M215.7 81.7h-.7l-.1 .7a.57 .57 0 0 1 .8 0 .57 .57 0 0 1-.1 .9 .57 .57 0 0 1-.8-.3M216.6 81.8a.57 .57 0 0 1 .7 .2v1a.51 .51 0 0 1-.4 .3 .51 .51 0 0 1-.5-.3 1.32 1.32 0 0 1 .2-1.2zM219.3 82.5l1-.1 .1-.2v-.3l-.4-.2h-.7v1.6h.7l.4-.1v-.6l-.4-.1M221 84.4v9M222 82a.61 .61 0 0 0-.5-.3 .61 .61 0 0 0-.5 .4l.1 .2 .8 .3 .1 .5a.71 .71 0 0 1-1 0M223.7 82.1a.59 .59 0 0 0-.7-.4 .59 .59 0 0 0-.5 .6v.4a.59 .59 0 0 0 .5 .6 .59 .59 0 0 0 .7-.3M224.2 83.2l-.1 .1h.2M234.6 81.8a.54 .54 0 0 1 .7 .2 .81 .81 0 0 1-.5 1.3 1.03 1.03 0 0 1-.2-1.5zM235.5 84.4v9M236 83.2v.1M237.8 82.8h-1.1l.7-1.1v1.6M238.4 81.8a.54 .54 0 0 1 .8 .2 .81 .81 0 0 1-.5 1.3 1.03 1.03 0 0 1-.3-1.5z"/>
<path d="M241.2 82.5l.9-.1 .2-.2-.2-.4-.9-.1v1.6h.7a.42 .42 0 0 0 .4-.4 .42 .42 0 0 0-.4-.4M242.8 84.4v9M243.9 82a.61 .61 0 0 0-.6-.3 .61 .61 0 0 0-.5 .4l.2 .2 .7 .3 .2 .5a.71 .71 0 0 1-1.1 0M245.5 82.1a.6 .6 0 0 0-.7-.4 .6 .6 0 0 0-.4 .6v.4a.6 .6 0 0 0 .4 .6 .6 .6 0 0 0 .7-.3M246.1 83.2l-.1 .1h.1M26.3 112.8h91.1M26.3 104.3h91.1M26.3 100.3h91.1M26.3 117.1h91.1M26.3 108.3h91.1M27.2 118.3h1.1M27.8 118.3v1.7"/>
<path d="M29.8 119.4h-1.2l.8-1.1v1.7M30.3 118.4a.33 .33 0 0 0 .2 .6 .58 .58 0 0 1 .6 .2 .58 .58 0 0 1 0 .7l-.5 .1-.4-.3a.78 .78 0 0 1 .9-.8l.1-.3a.63 .63 0 0 0-.9-.2zM31.7 118.3h1.1l-.8 1.7M33.2 118.3h1.1l-.7 1.7M34.8 119.3h1.4M35.5 118.6v1.4M36.8 118.6l.4-.3v1.7M38.3 118.4a.54 .54 0 0 1 .7 .2 .81 .81 0 0 1-.5 1.4 1.03 1.03 0 0 1-.2-1.6zM40.7 118.7a.6 .6 0 0 0-.7-.4 .6 .6 0 0 0-.4 .7v.3a.6 .6 0 0 0 .4 .7 .6 .6 0 0 0 .7-.4M52 105.8h-.8l-.1 .7a.57 .57 0 0 1 .9 0 .57 .57 0 0 1-.1 .9 .57 .57 0 0 1-.8-.3M52.7 107.3l-.1 .1h.2M53.4 106.1l.4-.3v1.6"/>
<path d="M54.8 105.9a.5 .5 0 0 1 .8 .2 .76 .76 0 0 1 .1 .9 .76 .76 0 0 1-.9 .4 1.24 1.24 0 0 1 0-1.5zM98.9 101.8a.52 .52 0 0 1 .8 .3l.1 .3a.69 .69 0 0 1-.6 1 1.03 1.03 0 0 1-.3-1.6zM98.9 114.7a.52 .52 0 0 1 .8 .2l.1 .4a.7 .7 0 0 1-.5 .9h-.1a1.01 1.01 0 0 1-.3-1.5zM98.9 119.1a.56 .56 0 0 1 .8 .2l.1 .4a.69 .69 0 0 1-.6 1 1.03 1.03 0 0 1-.3-1.6zM98.9 110.2a.52 .52 0 0 1 .8 .3l.1 .4a.69 .69 0 0 1-.6 .9 1.03 1.03 0 0 1-.3-1.6zM98.9 105.8a.56 .56 0 0 1 .8 .2l.1 .4a.7 .7 0 0 1-.5 .9h-.1a1.03 1.03 0 0 1-.3-1.5zM100.3 103.2v.2l.1-.1M100.3 116.1h.1M100.3 111.6v.2l.1-.1M100.3 107.2v.1h.1M101 102.1l.4-.4v1.7M101 114.9l.4-.3v1.6"/>
<path d="M101 119.3l.4-.3v1.7M101 110.5l.4-.3v1.6M101 106l.4-.3v1.6M102.3 102.1l.3-.4v1.7M102.3 114.9l.3-.3v1.6M102.3 119.3l.3-.3v1.7M102.3 110.5l.3-.3v1.6M102.3 106l.3-.3v1.6M104.4 101.7h-.7l-.1 .7a.57 .57 0 0 1 .8 0 .57 .57 0 0 1-.1 .9 .57 .57 0 0 1-.8-.3M104.4 114.6h-.7l-.1 .7a.57 .57 0 0 1 .8 0 .57 .57 0 0 1-.1 .9 .57 .57 0 0 1-.8-.3M104.4 119h-.7l-.1 .7a.57 .57 0 0 1 .8 0 .57 .57 0 0 1-.1 .9 .57 .57 0 0 1-.8-.3M104.4 110.2h-.7l-.1 .7a.57 .57 0 0 1 .8 0 .57 .57 0 0 1-.1 .8 .57 .57 0 0 1-.8-.2"/>
<path d="M104.4 105.7h-.7l-.1 .7a.57 .57 0 0 1 .8 0 .57 .57 0 0 1-.1 .9 .57 .57 0 0 1-.8-.3M106.5 101.7l1.1 1.7M106.5 114.6l1.1 1.6M106.5 119l1.1 1.7M106.5 110.2l1.1 1.6M106.5 105.7l1.1 1.6M107.6 101.7l-1.1 1.7M107.6 114.6l-1.1 1.6M107.6 119l-1.1 1.7M107.6 110.2l-1.1 1.6M107.6 105.7l-1.1 1.6M110.7 102.8h-1.2l.8-1.1v1.7"/>
<path d="M110.7 115.7h-1.2l.8-1.1v1.6M110.7 111.2h-1.2l.8-1v1.6M110.7 106.8h-1.2l.8-1.1v1.6M112 101.7h-.8l-.1 .7a.57 .57 0 0 1 .9 0 .57 .57 0 0 1-.1 .9 .57 .57 0 0 1-.9-.3M112 114.6h-.8l-.1 .7a.57 .57 0 0 1 .9 0 .57 .57 0 0 1-.1 .9 .57 .57 0 0 1-.9-.3M112 119h-.8l-.1 .7a.57 .57 0 0 1 .9 0 .57 .57 0 0 1-.1 .9 .57 .57 0 0 1-.9-.3M112 110.2h-.8l-.1 .7a.57 .57 0 0 1 .9 0 .57 .57 0 0 1-.1 .8 .57 .57 0 0 1-.9-.2M112 105.7h-.8l-.1 .7a.57 .57 0 0 1 .9 0 .57 .57 0 0 1-.1 .9 .57 .57 0 0 1-.9-.3M130.7 102.4h119.4M151.1 104.4a.33 .33 0 0 0 .2 .5 .59 .59 0 0 1 .6 .3 .59 .59 0 0 1 0 .6l-.5 .1a.46 .46 0 0 1-.4-.5 .46 .46 0 0 1 .5-.4l.3-.1a.33 .33 0 0 0 .1-.5zM151.1 100.1a.33 .33 0 0 0 .2 .5 .59 .59 0 0 1 .6 .2 .59 .59 0 0 1 0 .7l-.5 .1a.46 .46 0 0 1-.4-.5 .46 .46 0 0 1 .5-.4l.3-.1a.33 .33 0 0 0 .1-.5zM26.3 126h91.1"/>
<path d="M26.3 137.9h91.1M26.3 130.2h91.1M26.3 134.5h91.1M26.3 121.7h91.1M27.2 135.1h1M27.2 127.3h1.1M27.2 131.5h1.1M27.2 123h1.1M27.7 135.1v1.6M27.8 123v1.6M27.8 127.3v1.6M27.8 131.5v1.6"/>
<path d="M29.7 136.2h-1.1l.7-1.1v1.6M29.8 128.3h-1.2l.8-1v1.6M29.8 132.6h-1.2l.8-1.1v1.6M29.8 124.1h-1.2l.8-1.1v1.6M30.3 135.2a.31 .31 0 0 0 .1 .5l.3 .1a.47 .47 0 0 1 .5 .4 .47 .47 0 0 1-.4 .5h-.3a.47 .47 0 0 1-.4-.5 .47 .47 0 0 1 .5-.4l.3-.1a.31 .31 0 0 0 .1-.5zM30.3 127.3a.33 .33 0 0 0 .2 .6 .6 .6 0 0 1 .6 .2 .6 .6 0 0 1 .1 .6l-.6 .2-.4-.3a.78 .78 0 0 1 .9-.8l.1-.3a.63 .63 0 0 0-.9-.2zM30.3 131.6a.33 .33 0 0 0 .2 .5l.3 .1a.47 .47 0 0 1 .5 .4 .47 .47 0 0 1-.5 .5l-.5-.1-.1-.2a.78 .78 0 0 1 .9-.8l.1-.3a.6 .6 0 0 0-.9-.1zM30.3 123.1a.31 .31 0 0 0 .2 .5 .58 .58 0 0 1 .6 .3 .58 .58 0 0 1 0 .7h-.5l-.4-.3a.78 .78 0 0 1 .9-.8l.1-.3a.6 .6 0 0 0-.9-.1zM31.7 135.1h1l-.8 1.6M31.7 127.3h1.1l-.8 1.6M31.7 131.5h1.1l-.8 1.6M31.7 123h1.1l-.8 1.6"/>
<path d="M33.2 135.1h1.1l-.8 1.6M33.2 127.3h1.1l-.7 1.6M33.2 131.5h1.1l-.7 1.6M33.2 123h1.1l-.7 1.6M34.7 136.7v-1.6l.6 1.6 .7-1.6v1.6M34.8 128.2h1.4M34.8 132.4h1.4M34.8 123.9h1.4M35.5 123.2v1.4M35.5 127.5v1.4M35.5 131.7v1.4M36.6 136h1.4"/>
<path d="M36.8 127.6l.4-.3v1.6M36.8 131.8l.4-.3v1.6M36.8 123.3l.4-.3v1.6M37.3 135.3v1.4M38 127.6l.4-.3v1.6M38 123.3l.4-.3v1.6M38.1 131.9l.3-.4h.3l.3 .3-.2 .6-.8 .7h1.1M38.6 135.4l.4-.3v1.6M40.4 127.6a.6 .6 0 0 0-.7-.3 .6 .6 0 0 0-.4 .6v.4a.6 .6 0 0 0 .4 .6 .6 .6 0 0 0 .7-.4M66.1 131.7h-.8l-.1 .7a.58 .58 0 0 1 .9 0 .58 .58 0 0 1-.1 .9 .58 .58 0 0 1-.8-.2M68.6 132.8h-1.1l.7-1.1v1.7M98.9 131.7a.52 .52 0 0 1 .8 .3l.1 .4a.69 .69 0 0 1-.6 .9 1.03 1.03 0 0 1-.3-1.6z"/>
<path d="M98.9 135.7a.52 .52 0 0 1 .8 .2l.1 .4a.69 .69 0 0 1-.6 .9 1.03 1.03 0 0 1-.3-1.5zM98.9 128.2a.52 .52 0 0 1 .8 .2l.1 .4a.69 .69 0 0 1-.6 1 1.03 1.03 0 0 1-.3-1.6zM98.9 139.7a.56 .56 0 0 1 .8 .2l.1 .4a.71 .71 0 0 1-.5 .9h-.1a1.03 1.03 0 0 1-.3-1.5zM98.9 124a.56 .56 0 0 1 .8 .2l.1 .4a.69 .69 0 0 1-.6 .9 1.03 1.03 0 0 1-.3-1.5zM100.3 133.1v.2l.1-.1M100.3 137.1h.1M100.3 120.5v.2l.1-.1M100.3 129.6v.2l.1-.1M100.3 125.4v.1l.1-.1M101 132l.4-.3v1.6M101 135.9l.4-.3v1.6M101 128.4l.4-.3v1.7"/>
<path d="M101 139.9l.4-.3v1.6M101 124.2l.4-.3v1.6M102.3 132l.3-.3v1.6M102.3 135.9l.3-.3v1.6M102.3 128.4l.3-.3v1.7M102.3 139.9l.3-.3v1.6M102.3 124.2l.3-.3v1.6M104.4 131.7h-.7l-.1 .7a.57 .57 0 0 1 .8 0 .57 .57 0 0 1-.1 .8 .57 .57 0 0 1-.8-.2M104.4 135.6h-.7l-.1 .7a.57 .57 0 0 1 .8 0 .57 .57 0 0 1-.1 .8 .57 .57 0 0 1-.8-.2M104.4 128.1h-.7l-.1 .7a.57 .57 0 0 1 .8 0 .57 .57 0 0 1-.1 .9 .57 .57 0 0 1-.8-.3M104.4 139.6h-.7l-.1 .7a.57 .57 0 0 1 .8 0 .57 .57 0 0 1-.1 .8 .57 .57 0 0 1-.8-.2M104.4 123.9h-.7l-.1 .7a.57 .57 0 0 1 .8 0 .57 .57 0 0 1-.1 .8 .57 .57 0 0 1-.8-.2"/>
<path d="M106.5 131.7l1.1 1.6M106.5 135.6l1.1 1.6M106.5 128.1l1.1 1.7M106.5 139.6l1.1 1.6M106.5 123.9l1.1 1.6M107.6 131.7l-1.1 1.6M107.6 135.6l-1.1 1.6M107.6 128.1l-1.1 1.7M107.6 139.6l-1.1 1.6M107.6 123.9l-1.1 1.6M110.7 132.7h-1.2l.8-1v1.6M110.7 136.7h-1.2l.8-1.1v1.6"/>
<path d="M110.7 120.1h-1.2l.8-1.1v1.7M110.7 129.2h-1.2l.8-1.1v1.7M110.7 125h-1.2l.8-1.1v1.6M112 131.7h-.8l-.1 .7a.57 .57 0 0 1 .9 0 .57 .57 0 0 1-.1 .8 .57 .57 0 0 1-.9-.2M112 135.6h-.8l-.1 .7a.57 .57 0 0 1 .9 0 .57 .57 0 0 1-.1 .8 .57 .57 0 0 1-.9-.2M112 128.1h-.8l-.1 .7a.57 .57 0 0 1 .9 0 .57 .57 0 0 1-.1 .9 .57 .57 0 0 1-.9-.3M112 139.6h-.8l-.1 .7a.57 .57 0 0 1 .9 0 .57 .57 0 0 1-.1 .8 .57 .57 0 0 1-.9-.2M112 123.9h-.8l-.1 .7a.57 .57 0 0 1 .9 0 .57 .57 0 0 1-.1 .8 .57 .57 0 0 1-.9-.2M26.3 142.1h91.1M26.3 146.4h91.1M26.3 150.6h91.1M26.3 154.9h91.1"/>
<path d="M26.3 159.1h91.1M98.9 152.6a.56 .56 0 0 1 .8 .2l.1 .4a.71 .71 0 0 1-.5 .9h-.1a1.03 1.03 0 0 1-.3-1.5zM98.9 144a.52 .52 0 0 1 .8 .2l.1 .4a.69 .69 0 0 1-.6 .9 1.03 1.03 0 0 1-.3-1.5zM98.9 148.4a.52 .52 0 0 1 .8 .2l.1 .4a.69 .69 0 0 1-.6 .9 1.03 1.03 0 0 1-.3-1.5zM98.9 156.8a.52 .52 0 0 1 .8 .3l.1 .3a.69 .69 0 0 1-.6 1 1.03 1.03 0 0 1-.3-1.6zM100.3 154v.1h.1M100.3 141.1h.1M100.3 145.4v.1l.1-.1M100.3 149.7v.1h.1M100.3 158.2v.2l.1-.1M101 152.8l.4-.3v1.6M101 144.2l.4-.3v1.6"/>
<path d="M101 148.6l.4-.3v1.6M101 157.1l.4-.4v1.7M102.3 152.8l.3-.3v1.6M102.3 144.2l.3-.3v1.6M102.3 148.6l.3-.3v1.6M102.3 157.1l.3-.4v1.7M104.4 152.5h-.7l-.1 .7a.57 .57 0 0 1 .8 0 .57 .57 0 0 1-.1 .8 .57 .57 0 0 1-.8-.2M104.4 143.9h-.7l-.1 .7a.57 .57 0 0 1 .8 0 .57 .57 0 0 1-.1 .8 .57 .57 0 0 1-.8-.2M104.4 148.3h-.7l-.1 .7a.57 .57 0 0 1 .8 0 .57 .57 0 0 1-.1 .8 .57 .57 0 0 1-.8-.2M104.4 156.7h-.7l-.1 .7a.57 .57 0 0 1 .8 0 .57 .57 0 0 1-.1 .9 .57 .57 0 0 1-.8-.2M106.5 152.5l1.1 1.6M106.5 143.9l1.1 1.6"/>
<path d="M106.5 148.3l1.1 1.6M106.5 156.7l1.1 1.7M107.6 152.5l-1.1 1.6M107.6 143.9l-1.1 1.6M107.6 148.3l-1.1 1.6M107.6 156.7l-1.1 1.7M110.7 153.6h-1.2l.8-1.1v1.6M110.7 140.7h-1.2l.8-1.1v1.6M110.7 145h-1.2l.8-1.1v1.6M110.7 149.4h-1.2l.8-1.1v1.6M110.7 157.8h-1.2l.8-1.1v1.7M112 152.5h-.8l-.1 .7a.57 .57 0 0 1 .9 0 .57 .57 0 0 1-.1 .8 .57 .57 0 0 1-.9-.2"/>
<path d="M112 143.9h-.8l-.1 .7a.57 .57 0 0 1 .9 0 .57 .57 0 0 1-.1 .8 .57 .57 0 0 1-.9-.2M112 148.3h-.8l-.1 .7a.57 .57 0 0 1 .9 0 .57 .57 0 0 1-.1 .8 .57 .57 0 0 1-.9-.2M112 156.7h-.8l-.1 .7a.57 .57 0 0 1 .9 0 .57 .57 0 0 1-.1 .9 .57 .57 0 0 1-.9-.2M26.3 167.6h91.1M26.3 171.9h91.1M26.3 163.4h91.1M26.3 176.1h91.1M27.2 169.2h1M27.7 169.2v1.6M29.5 169.2h-.8l-.1 .7a.58 .58 0 0 1 .9 0 .58 .58 0 0 1-.1 .9 .58 .58 0 0 1-.8-.3M31 169.5a.45 .45 0 0 0-.7-.2 .91 .91 0 0 0 .3 1.5 .5 .5 0 0 0 .5-.5 .5 .5 0 0 0-.5-.4 .5 .5 0 0 0-.5 .4M31.6 169.2h1.1l-.8 1.6"/>
<path d="M33.2 169.2h1.1l-.8 1.6M34.7 170.8v-1.6l.6 1.6 .6-1.6v1.6M37.7 169.2v1.6l-1.1-1.6v1.6M38.3 170.2h1.4M39 169.5v1.3M40.3 169.5l.4-.3v1.6M268.7 170.2h-81.9v35.3M26.3 185.5h91.1M26.3 180.4h91.1M186.8 186.7h81.9M186.8 197.4h81.9M187.9 191.5l1.3-.1a.62 .62 0 0 0 .2-.6 .62 .62 0 0 0-.5-.5h-1v2.3"/>
<path d="M187.9 187.6h1M188.1 193.9h1.2l-.6 .9a.73 .73 0 0 1 .7 .8 .73 .73 0 0 1-.9 .6l-.4-.1-.2-.3M188.4 187.6v1.5M189.2 187.6v1.5M189.7 187.6h1M190.2 192.6l.9-2.3 .8 2.3M190.2 194.5l.1-.4a.76 .76 0 0 1 1-.1 .53 .53 0 0 1 .1 .8l-1.3 1.4h1.5M190.2 187.6v1.5M190.5 191.9h1.1M191 187.6v1.5h.8M192.2 188.3h.5M192.5 196.1l-.1 .1-.1-.1 .1-.1 .1 .1-.2 .6"/>
<path d="M193.1 187.6h-.9v1.5h.9M193.6 188.1v.1zM193.6 188.9v.2zM194.2 190.9a.84 .84 0 0 0-.9-.6 .84 .84 0 0 0-.7 .9 1 1 0 0 0 .2 1.1 1 1 0 0 0 1.1 .2l.3-.4M194.9 190.3v2.3M195.4 191.3l1 1.3M196.4 190.3l-1.5 1.6M197.1 195.5h-1.7l1.1-1.6v2.3M197.2 192.6l.9-2.3 .9 2.3M197.5 191.9h1.1M199.3 195.5h-1.7l1.1-1.6v2.3M200 196.1l-.1 .1-.1-.1 .1-.1 .1 .1-.2 .6"/>
<path d="M201.2 190.9a.84 .84 0 0 0-.9-.6 .84 .84 0 0 0-.7 .9 1 1 0 0 0 .2 1.1 1 1 0 0 0 1.1 .2l.3-.4v-.3h-.5M201.9 191.4h.9M203.3 190.3h-1.4v2.3h1.4M204.6 195.5h-1.6l1.1-1.6v2.3M205.4 194a.46 .46 0 0 0 .2 .8 .93 .93 0 0 1 1.1 1 .8 .8 0 0 1-.9 .4 .8 .8 0 0 1-.6-.7 1.06 1.06 0 0 1 1.1-.7 .46 .46 0 0 0 .2-.8l-.3-.1zM206.5 190.4a1.06 1.06 0 0 1 1.2 .4 1.06 1.06 0 0 1 0 1.3 .85 .85 0 0 1-1 .5 .85 .85 0 0 1-.7-.8 1.51 1.51 0 0 1 .5-1.4zM207.6 196.1l-.1 .1-.1-.1 .1-.1 .1 .1-.2 .6M208.5 190.3v1.7a.77 .77 0 0 0 .7 .7 .77 .77 0 0 0 .8-.7v-1.7M210.9 190.3h1.5M211.6 190.3v2.3M211.8 193.9h-1l-.2 1a.82 .82 0 0 1 1.3 0 .82 .82 0 0 1-.2 1.2 .82 .82 0 0 1-1.2-.3M212.8 190.3v2.3h1.4"/>
<path d="M213.4 197.4v8.1M214 194.3a.65 .65 0 0 0-.6-.4 .65 .65 0 0 0-.6 .5 1.7 1.7 0 0 0 .2 1.7 .71 .71 0 0 0 1.1-.3 .71 .71 0 0 0-.5-1 .71 .71 0 0 0-.9 .7M214.1 198.3a.83 .83 0 0 1 .9 .4 .83 .83 0 0 1-.2 1.1h-.7zM214.7 190.3v2.3M214.9 193.9v2.3h1.3M215.7 198.5a.54 .54 0 0 1 .6-.2 .54 .54 0 0 1 .3 .6v.3a.55 .55 0 0 1-.5 .6 .55 .55 0 0 1-.6-.6zM217.1 190.3v2.3l-1.5-2.3v2.3M218 191.4h.8M218.1 198.7a.53 .53 0 0 0-.6-.4 .53 .53 0 0 0-.4 .6v.3a.53 .53 0 0 0 .4 .6 .53 .53 0 0 0 .6-.3M218.5 198.3v1.1a.49 .49 0 0 0 .5 .4 .49 .49 0 0 0 .5-.4v-1.1M218.8 193.9h1.6M219.4 190.3h-1.4v2.3h1.4"/>
<path d="M219.6 193.9v2.3M220.3 192.5l-.1 .1-.1-.1 .1-.1a.43 .43 0 0 1-.1 .7M220.8 193.9v2.3M220.8 195h1.5M222.3 193.9v2.3M223.2 193.9v2.3M225.6 193.9v2.3l-1.5-2.3v2.3M228.8 194.3a.85 .85 0 0 1 1-.3 .85 .85 0 0 1 .5 .8 1 1 0 0 1-.2 1.1 1 1 0 0 1-1.1 .2 1.46 1.46 0 0 1-.2-1.8zM229.6 195.8l.6 .7M231 195h.9M232.4 193.9h-1.4v2.3M234.5 193.9v2.3l-1.6-2.3v2.3"/>
<path d="M235.6 196.1l-.1 .1-.1-.1 .1-.1 .1 .1-.2 .6M238.5 193.9h1.6l-1.1 2.3M240.7 194.7l1.2 1.5M241.9 194.7l-1.2 1.5M242.6 193.9h1.5l-1.1 2.3M244.8 194.7l1.2 1.5M246 194.7l-1.2 1.5M246.9 194a.77 .77 0 0 1 1.1 .4 1.96 1.96 0 0 1-.2 1.7 .77 .77 0 0 1-1.1-.3 1.96 1.96 0 0 1 .2-1.8zM248.9 196l-.1 .1 .1 .1 .1-.1M249.9 193.9h1.5l-1.1 2.3M251.1 197.4v8.1M251.9 199h.8l.2-.3-.1-.3-.3-.1h-.6v1.5"/>
<path d="M252.4 199l.5 .8M253.4 199h.5M253.4 193.9h-1.1l-.1 1a.82 .82 0 0 1 1.2 0 .82 .82 0 0 1-.1 1.2 .82 .82 0 0 1-1.2-.3M254.3 198.3h-.9v1.5h.9M254.3 195.1l.5-.4 .6 .1 .1 1.4M254.3 194.7v1.5M254.7 198.3l.5 1.5 .6-1.5M255.5 195.1l.5-.4 .6 .1 .1 1.4M256.1 199.7v.1h.1M257.6 195.1l.5-.4 .5 .1 .1 1.4M257.6 194.7v1.5M258.7 195.1l.6-.4 .5 .1 .2 1.4"/>
<path d="M259.9 197.4v8.1M261.9 198.5l.2-.4a.79 .79 0 0 1 1.1 0 .8 .8 0 0 1-.2 1.1l-1.2 1.2h1.7M266.5 198.6l-5.4 5.3M196.2 202.4h.9l-.9 1.5h.9M197.5 202.4v1.5M197.5 203.1h.9M198.4 202.4v1.5M199 203.1h.5M199.8 202.4h-.8v1.5h.8M201.1 202.4v1.5l-.9-1.5v1.5M202.9 202.4v1.5h.8M204 202.4v1.5"/>
<path d="M254.6 200.9l1 1.4 1.1-1.4M255.6 202.3v1.6M265.1 201.4h1.2l-.7 .9a.8 .8 0 0 1 .9 1 .8 .8 0 0 1-1.1 .6l-.3-.1-.3-.4"/>
<circle cx="112.8" cy="81" r=".16"/>
<circle cx="112.8" cy="85.5" r=".16"/>
<circle cx="112.8" cy="89.5" r=".16"/>
<circle cx="112.8" cy="97.9" r=".16"/>
<circle cx="112.8" cy="93.9" r=".16"/>
<circle cx="112.8" cy="105.9" r=".16"/>
<circle cx="112.8" cy="114.7" r=".16"/>
<circle cx="112.8" cy="101.9" r=".16"/>
<circle cx="112.8" cy="119.2" r=".16"/>
<circle cx="112.8" cy="110.3" r=".16"/>
<circle cx="112.8" cy="135.8" r=".16"/>
<circle cx="112.8" cy="139.7" r=".16"/>
<circle cx="112.8" cy="124" r=".16"/>
<circle cx="112.8" cy="128.3" r=".16"/>
<circle cx="112.8" cy="131.8" r=".16"/>
<circle cx="112.8" cy="144.1" r=".16"/>
<circle cx="112.8" cy="148.4" r=".16"/>
<circle cx="112.8" cy="152.7" r=".16"/>
<circle cx="112.8" cy="156.9" r=".16"/>
</g>
<g fill="#000" stroke="#000" stroke-width=".2">
<path d="M9.9 10.2l1 1 258.3-1zM10.9 11.2l258.3-1-1 1z"/>
<path d="M268.2 11.2l1 194.8v-195.8zM268.2 11.2l1 194.8-1-1zM9.9 206h259.3l-1-1zM9.9 206l1-1h257.3zM9.9 10.2v195.8l1-1zM9.9 10.2l1 1v193.8zM9.9 10.2l1 1z"/>
<path d="M213.1 176l1.5 2.5v-2.5zM213.1 176l1.5 2.5h-1.5z"/>
<path d="M213.1 178.5l1.5 2.6v-2.6zM213.1 178.5l1.5 2.6h-1.5z"/>
<path d="M213.1 174.7l7.3 1.3v-1.3zM213.1 174.7l7.3 1.3h-7.3z"/>
<path d="M214.6 176l5.8 2.5v-2.5zM214.6 176l5.8 2.5h-1.1z"/>
<path d="M219.3 178.5l1.1 2.6v-2.6zM214.6 181.1l4.7-2.6 1.1 2.6z"/>
<path d="M213.1 181.1l7.3 .9v-.9zM213.1 181.1l7.3 .9h-7.3z"/>
</g>
<path d="M213.1 174.7h7.3v7.3h-7.3zM214.6 176l4.7 2.5-4.7 2.6z" fill="none" stroke="#000" stroke-width=".2"/>
<use href="#words"/>
</svg>
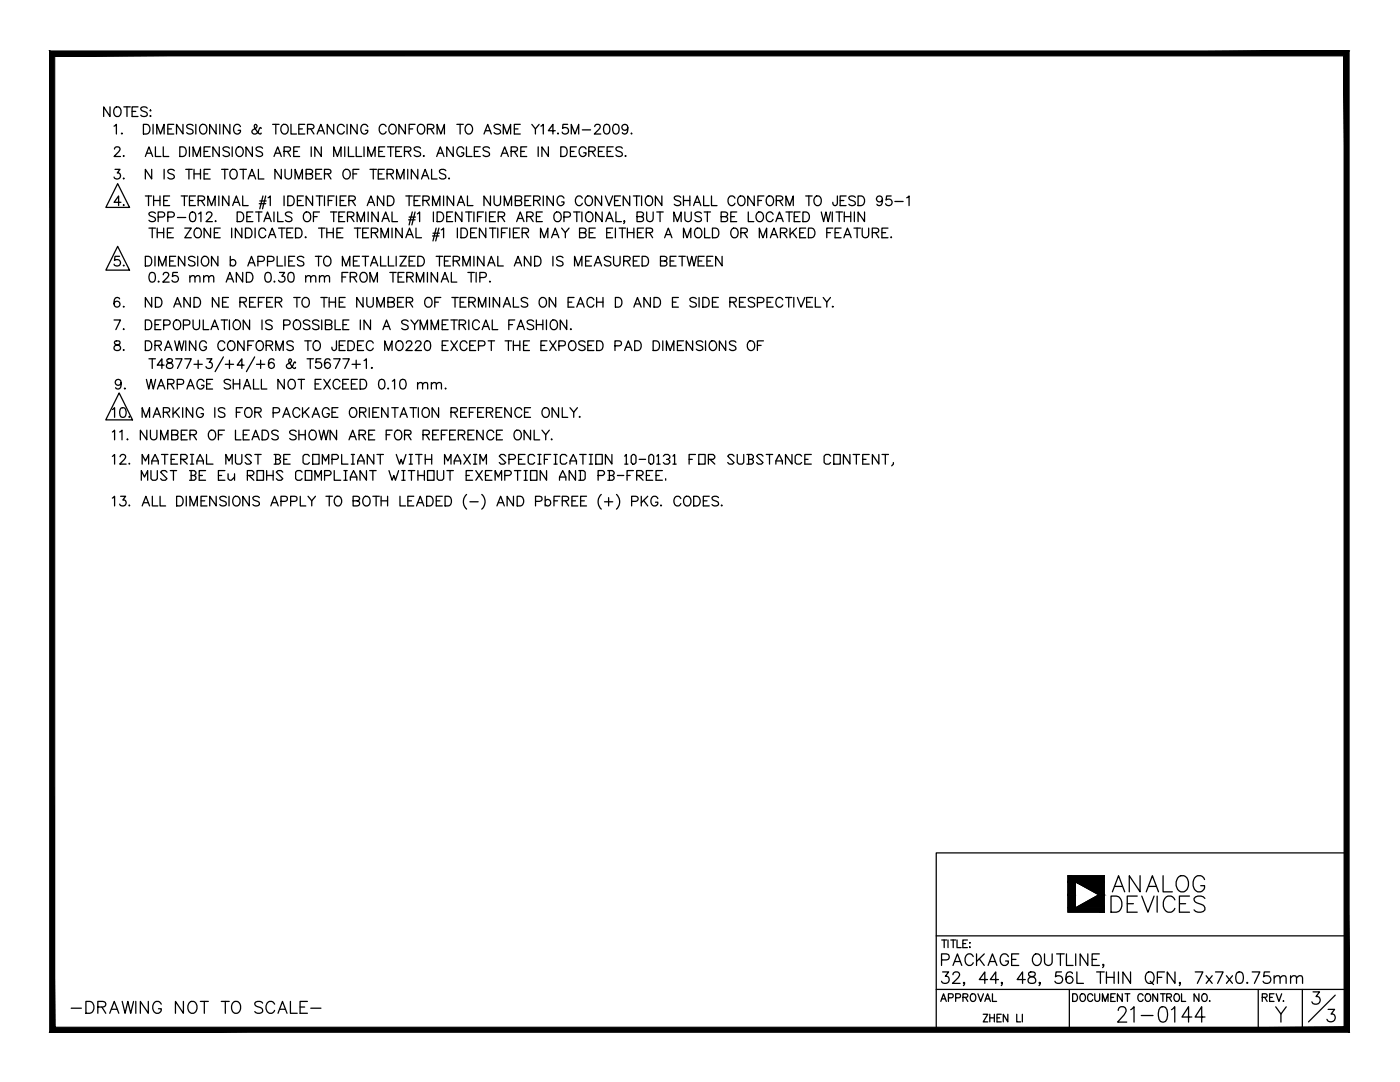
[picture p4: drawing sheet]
<svg xmlns="http://www.w3.org/2000/svg" width="279mm" height="216mm" viewBox="0 0 279 216" stroke-linecap="round" stroke-linejoin="round" font-family="sans-serif">
<defs><g id="words">
<g font-size="6.6">
<text x="220.8" y="179.2">ANALOG</text>
<text x="220.5" y="183.1">DEVICES</text>
<text x="221.9" y="205.3">21-0144</text>
</g>
<text font-size="5.7" x="13.1" y="203.6">-DRAWING NOT TO SCALE-</text>
<g font-size="4.9">
<text x="19.4" y="24.3">NOTES:</text>
<text x="21.5" y="27.9">1. DIMENSIONING &amp; TOLERANCING CONFORM TO ASME Y14.5M-2009.</text>
<text x="21.5" y="62.4">6. ND AND NE REFER TO THE NUMBER OF TERMINALS ON EACH D AND E SIDE RESPECTIVELY.</text>
<text x="21.2" y="88.9">11. NUMBER OF LEADS SHOWN ARE FOR REFERENCE ONLY.</text>
</g>
<text font-size="4.4" x="186.6" y="201.1">APPROVAL</text>
</g></defs>
<!-- layer: 0 -->
<g fill="none" stroke="#000" stroke-width=".25">
<path d="M22.8 29.7l.2-.2a.63 .63 0 0 1 .9 0 .61 .61 0 0 1-.2 .8l-.9 .9h1.3M23 33.8h.9l-.5 .7a.64 .64 0 0 1 .5 1 .64 .64 0 0 1-1.1-.2M24.7 31v.2l.1-.1M24.7 35.5v.2l.1-.1M29 31.2l.7-1.9 .8 1.9M29 39.1h1.3M29.3 30.6h.9M29.6 39.1v1.9M30.3 33.8v1.9l-1.3-1.9v1.9M30.7 39.1v1.9M31 29.3v1.9h1.1M31.9 39.1v1.9"/>
<path d="M32.6 29.3v1.9h1.1M32.8 33.8v1.9M33.9 39.1h-1.2v1.9h1.2M34.8 34.1a.74 .74 0 0 0-1.3 .1l.4 .4 .7 .3 .2 .5a.86 .86 0 0 1-1.3 0M35.9 29.3h.6a1.03 1.03 0 0 1 .7 1 1.03 1.03 0 0 1-.7 .9h-.6zM36.2 39.1h1.2M36.8 39.1v1.9M37.1 33.8h1.3M37.7 33.8v1.9M37.8 29.3v1.9M38.5 31.2v-1.9l.8 1.9 .7-1.9v1.9M38.7 33.8v1.9"/>
<path d="M38.7 34.7h1.3M39 39.1h-1.2v1.9h1.2M40 33.8v1.9M40.7 30.2h.8M40.7 34.7h.8M41.9 29.3h-1.2v1.9h1.2M41.9 33.8h-1.2v1.9h1.2M43.7 39.1v1.9M43.8 29.3v1.9l-1.3-1.9v1.9M44.2 33.8h1.3M44.9 33.8v1.9M45.7 39.1v1.9l-1.3-1.9v1.9"/>
<path d="M45.8 29.6a.74 .74 0 0 0-1.3 .1l.4 .4 .7 .3 .2 .6a.86 .86 0 0 1-1.3 0M46.2 33.9a.96 .96 0 0 1 1.2 .6 .96 .96 0 0 1-.6 1.2 1.01 1.01 0 0 1-1-.7 1.01 1.01 0 0 1 .4-1.1zM46.3 29.3v1.9M47.3 29.6a.71 .71 0 0 1 .8-.3 .71 .71 0 0 1 .4 .7 .84 .84 0 0 1-.1 .9 .84 .84 0 0 1-1 .2 1.15 1.15 0 0 1-.1-1.5zM47.9 33.8h1.3M48.4 39.1v1.9h1.1M48.5 33.8v1.9M49.5 35.7l.8-1.9 .7 1.9M49.8 35.1h.9M50.4 29.3v1.9l-1.3-1.9v1.9M51.6 33.8v1.9h1.1M52.4 29.6a.74 .74 0 0 0-1.3 .1l.4 .4 .7 .3 .2 .6a.86 .86 0 0 1-1.3 0"/>
<path d="M52.5 39.1l-.7 2.6M53 39.1l-.6 2.6M53.5 39.5l.4-.4v1.9M54.7 31.2l.7-1.9 .7 1.9M55 30.6h.9M56.1 33.8v1.9l-1.2-1.9v1.9M56.7 30.2l1.1-.1 .2-.2-.1-.4-.4-.2h-.8v1.9M56.7 39.1v1.9M56.9 33.8v1.4a.65 .65 0 0 0 .6 .5 .65 .65 0 0 0 .7-.5v-1.4M57.3 30.2l.7 1M57.4 39.1h.7a1.03 1.03 0 0 1 .6 1 1.03 1.03 0 0 1-.6 .9h-.7zM58.6 30.2h.8"/>
<path d="M58.9 35.7v-1.9l.7 1.9 .8-1.9v1.9M59.8 29.3h-1.2v1.9h1.2M60.5 39.1h-1.1v1.9h1.1M61.1 34.7h.8a.5 .5 0 0 0 .5-.6l-.2-.2-.3-.1h-.8v1.9h.8a.51 .51 0 0 0 .5-.5 .51 .51 0 0 0-.5-.5M62.1 29.3v1.9M62.4 39.1v1.9l-1.3-1.9v1.9M63 34.7h.8M63.1 39.1h1.3M63.8 39.1v1.9M64.1 29.3v1.9l-1.3-1.9v1.9M64.2 33.8h-1.2v1.9h1.2M64.8 34.7l1.1-.1 .1-.3v-.3l-.4-.2h-.8v1.9"/>
<path d="M64.8 39.1v1.9M65.4 34.7l.6 1M66.6 31.2v-1.9l.7 1.9 .8-1.9v1.9M66.7 39.1h-1.2v1.9M67.1 39.1v1.9M68.6 34.1a.71 .71 0 0 1 .8-.3 .71 .71 0 0 1 .5 .7 .84 .84 0 0 1-.2 .9 .84 .84 0 0 1-.9 .2 1.21 1.21 0 0 1-.2-1.5zM68.8 29.3v1.9M69.1 39.1h-1.2v1.9h1.2M69.5 29.3v1.9h1.1M70.4 34.7h.8M71.1 29.3v1.9h1.1M71.6 33.8h-1.2v1.9"/>
<path d="M72.7 29.3v1.9M73.4 31.2v-1.9l.7 1.9 .8-1.9v1.9M73.8 33.8h1.3M74.5 33.8v1.9M75.5 34.7h.7M75.6 30.2h.7M76.6 39.1v1.9l-1.3-1.9v1.9M76.7 33.8h-1.2v1.9h1.2M76.8 29.3h-1.2v1.9h1.2M77.2 34.7l1.1-.1 .2-.3-.1-.3-.3-.2h-.9v1.9M77.3 39.1h.7a1.02 1.02 0 0 1 .6 1 1.02 1.02 0 0 1-.6 .9h-.7zM77.9 34.7l.6 1"/>
<path d="M78 29.3v1.9M79 30.2h.7M79.2 35.7v-1.9l.7 1.9 .7-1.9v1.9M80.2 29.3h-1.2v1.9h1.2M80.7 30.2l1.1-.1 .2-.2-.1-.4-.4-.2h-.8v1.9M81 39.1h1.3M81.4 30.2l.6 1M81.4 33.8v1.9M81.6 39.1v1.9M83.4 33.8v1.9l-1.3-1.9v1.9M83.8 39.1h-1.2v1.9h1.2M83.9 29.6a.74 .74 0 0 0-1.3 .1l.2 .3 .8 .3a.47 .47 0 0 1 .3 .4 .47 .47 0 0 1-.2 .4 .87 .87 0 0 1-1.1-.1"/>
<path d="M84.1 35.7l.7-1.9 .8 1.9M84.4 35.1h.9M84.6 31v.2l.1-.1M86.1 33.8v1.9h1.1M87.2 31.2l.7-1.9 .7 1.9M87.4 30.6h.9M88.5 39.1v1.9M89 34.1a.72 .72 0 0 0-.7-.3 .72 .72 0 0 0-.6 .4l.2 .3 .7 .3a.48 .48 0 0 1 .2 .8 .85 .85 0 0 1-1.1-.2M89.6 35.5l-.1 .1 .1 .1 .1-.1M90.5 29.3v1.9l-1.3-1.9v1.9M90.5 39.1v1.9l-1.3-1.9v1.9M92.5 29.7a.71 .71 0 0 0-.8-.4 .71 .71 0 0 0-.5 .7 .84 .84 0 0 0 .2 .9 .84 .84 0 0 0 .9 .2l.2-.3v-.3h-.4"/>
<path d="M93.1 29.3v1.9h1.1M93.3 39.1v1.9h1.1M94.7 30.2h.7M95.8 29.3h-1.1v1.9h1.1M97.7 29.6a.74 .74 0 0 0-1.3 .1l.2 .3 .7 .3a.47 .47 0 0 1 .4 .4 .47 .47 0 0 1-.2 .4 .87 .87 0 0 1-1.1-.1M97.9 39.1v1.9l-1.3-1.9v1.9M98.6 39.1v1.4a.65 .65 0 0 0 .6 .5 .65 .65 0 0 0 .7-.5v-1.4M100 31.2l.7-1.9 .8 1.9M100.3 30.6h.9M102 30.2l1.1-.1 .2-.2-.1-.4-.4-.2h-.8v1.9M102.6 30.2l.7 1M103.9 30.2h.8"/>
<path d="M105.1 29.3h-1.2v1.9h1.2M105.9 39.1h-1.1v1.9h1.1M107.4 29.3v1.9M108.4 39.1v1.9M109.4 29.3v1.9l-1.3-1.9v1.9M110.4 39.1v1.9l-1.2-1.9v1.9M111.9 29.3h.7a1.03 1.03 0 0 1 .6 1 1.03 1.03 0 0 1-.6 .9h-.7zM112.6 39.5a.71 .71 0 0 0-.9-.4 .71 .71 0 0 0-.5 .7 .84 .84 0 0 0 .2 .9 .84 .84 0 0 0 .9 .2l.3-.3v-.3h-.5M113.8 30.2h.8M115 29.3h-1.2v1.9h1.2M116.2 39.5a.71 .71 0 0 0-.8-.4 .71 .71 0 0 0-.6 .7 .84 .84 0 0 0 .2 .9 .84 .84 0 0 0 .9 .2l.3-.3M117 39.4a.71 .71 0 0 1 .8-.3 .71 .71 0 0 1 .4 .7 .84 .84 0 0 1-.1 .9 .84 .84 0 0 1-1 .2 1.15 1.15 0 0 1-.1-1.5z"/>
<path d="M117 29.7a.71 .71 0 0 0-.9-.4 .71 .71 0 0 0-.5 .7 .84 .84 0 0 0 .2 .9 .84 .84 0 0 0 .9 .2l.3-.3v-.3h-.5M117.5 30.2h.8a.5 .5 0 0 0 .5-.5l-.2-.3-.3-.1h-.8v1.9M118.1 30.2l.7 1M119.4 30.2h.8M120.1 39.1v1.9l-1.3-1.9v1.9M120.6 29.3h-1.2v1.9h1.2M120.8 39.1l.7 1.9 .8-1.9M121.2 30.2h.7M122.4 29.3h-1.2v1.9h1.2M123.8 39.1h-1.2v1.9h1.2M124.2 29.6a.72 .72 0 0 0-.7-.3 .72 .72 0 0 0-.6 .4l.2 .3 .7 .3a.48 .48 0 0 1 .2 .8 .85 .85 0 0 1-1.1-.1M124.8 31l-.1 .1 .1 .1 .1-.1"/>
<path d="M125.7 39.1v1.9l-1.3-1.9v1.9M126.4 39.1h1.3M127 39.1v1.9M128 39.1v1.9M129.1 39.2a.96 .96 0 0 1 1.2 .6 .96 .96 0 0 1-.6 1.2 1.01 1.01 0 0 1-.9-.7 1.01 1.01 0 0 1 .3-1.1zM132.1 39.1v1.9l-1.3-1.9v1.9M135.9 39.4a.74 .74 0 0 0-1.3 .1l.3 .4 .8 .3 .2 .6a.86 .86 0 0 1-1.3 0M136.4 39.1v1.9M137.7 39.1v1.9M140.4 39.1v1.9h1.1M142 39.1v1.9h1.1M146.7 39.5a.71 .71 0 0 0-.8-.4 .71 .71 0 0 0-.6 .7 .84 .84 0 0 0 .2 .9 .84 .84 0 0 0 .9 .2l.3-.3"/>
<path d="M147.6 39.2a.96 .96 0 0 1 1.1 .6 .96 .96 0 0 1-.6 1.2 1.01 1.01 0 0 1-.9-.7 1.01 1.01 0 0 1 .4-1.1zM150.5 39.1v1.9l-1.3-1.9v1.9M152.4 39.1h-1.1v1.9M153.3 39.2a.96 .96 0 0 1 1.1 .6 .96 .96 0 0 1-.6 1.2 1.01 1.01 0 0 1-.9-.7 1.01 1.01 0 0 1 .4-1.1zM160.8 39.1h1.3M161.4 39.1v1.9M162.8 39.2a.96 .96 0 0 1 1.2 .6 .96 .96 0 0 1-.6 1.2 1.01 1.01 0 0 1-1-.7 1.01 1.01 0 0 1 .4-1.1zM167.1 39.1v1.5a.5 .5 0 0 1-.5 .4 .53 .53 0 0 1-.4-.6M168.9 39.1h-1.2v1.9h1.2M170.7 39.4a.74 .74 0 0 0-1.3 .1l.2 .3 .7 .3a.47 .47 0 0 1 .4 .4 .47 .47 0 0 1-.2 .4 .87 .87 0 0 1-1.1-.1M171.2 39.1h.7a1.02 1.02 0 0 1 .7 1 1.02 1.02 0 0 1-.7 .9h-.7zM176.1 39.7a.6 .6 0 0 1-.8 .6 .6 .6 0 0 1-.3-.9 .6 .6 0 0 1 1 0 1.03 1.03 0 0 1-.6 1.6l-.4-.2"/>
<path d="M177.8 39.1h-.9l-.1 .8a.68 .68 0 0 1 1.1 0 .68 .68 0 0 1-.2 1 .68 .68 0 0 1-1-.3M181 39.5l.4-.4v1.9M23.9 51.1h-.9l-.2 .9a.69 .69 0 0 1 1.1-.1 .69 .69 0 0 1-.1 1.1 .69 .69 0 0 1-1-.3M24.1 40.4h-1.3l.9-1.3v1.9M24.7 40.8v.2l.1-.1M24.7 52.9l-.1 .1h.2M29 51.1h.6a1.03 1.03 0 0 1 .7 1 1.03 1.03 0 0 1-.7 1h-.6zM29.7 45.5h1.3M30 54.4a.65 .65 0 0 1 .9 .3 1.65 1.65 0 0 1-.2 1.5 .63 .63 0 0 1-.9-.3 1.56 1.56 0 0 1 .2-1.5zM30.4 45.5v1.9M30.7 40h1.2M30.9 51.1v2"/>
<path d="M31 42.6a.73 .73 0 0 0-.7-.3 .73 .73 0 0 0-.6 .5l.2 .2 .9 .4 .2 .5a.86 .86 0 0 1-1.3 0M31.4 45.5v1.9M31.4 46.4h1.3M31.6 43.3h.8a.51 .51 0 0 0 .5-.5 .51 .51 0 0 0-.5-.5h-.8v1.9M31.7 53.1v-2l.7 2 .7-2v2M31.7 56.1l-.1 .1h.2M32.6 54.8l.1-.2 .2-.2h.6a.43 .43 0 0 1 .1 .7l-1.1 1.2h1.3M32.7 40h.7M32.7 45.5v1.9M33.4 46.4h.7M33.5 43.3h.8a.51 .51 0 0 0 .5-.5 .51 .51 0 0 0-.5-.5h-.8v1.9M33.9 52.1h.7"/>
<path d="M34.6 45.5h-1.2v1.9h1.2M35.1 51.1h-1.2v2h1.2M35.4 54.4h-.9l-.1 .8a.69 .69 0 0 1 1 0 .69 .69 0 0 1-.1 1 .69 .69 0 0 1-1-.3M35.4 43.4h1.7M36.9 51.1v2l-1.3-2v2M36.9 45.5h1.3l-1.3 1.9h1.3M37.8 40h.7M37.9 55.4l.5-.4 .4 .1 .1 1.2M37.9 55v1.3M38.1 42.4a.6 .6 0 0 1 .9 .3 1.62 1.62 0 0 1-.2 1.4 .63 .63 0 0 1-.9-.2 1.6 1.6 0 0 1 .2-1.5zM38.9 51.4a.73 .73 0 0 0-.7-.3 .73 .73 0 0 0-.6 .5l.2 .3 .9 .3 .2 .6a.86 .86 0 0 1-1.3 0M38.9 55.4l.5-.4 .4 .1 .1 1.2"/>
<path d="M39.1 45.6a.89 .89 0 0 1 1 .3 .89 .89 0 0 1 0 1.1 .71 .71 0 0 1-.8 .4 .71 .71 0 0 1-.6-.7 1.19 1.19 0 0 1 .4-1.1zM39.5 51.1v2M39.5 40h.9a.5 .5 0 0 0 .4-.5l-.2-.3-.2-.1h-.9v1.9M39.6 42.7l.5-.4v1.9M40.2 40l.6 1M40.4 51.4l.2-.1a.91 .91 0 0 1 1.1 .3 .91 .91 0 0 1-.2 1.2 .71 .71 0 0 1-.8 .3 .71 .71 0 0 1-.5-.7zM40.6 55.4l.5-.4 .5 .1 .1 1.2M40.6 55v1.3M41.2 42.8l.1-.3 .3-.2h.3l.3 .2a.61 .61 0 0 1-.2 .8l-.9 .9h1.3M41.5 41v-1.9l.7 1.9 .7-1.9v1.9M41.7 55.4l.4-.4 .5 .1 .1 1.2M42 45.5v1.9l-1.3-1.9v1.9"/>
<path d="M42.8 46.4h.7M43 44.1h-.1h.2M43.5 51.1v2l-1.3-2v2M43.9 45.5h-1.1v1.9h1.1M45.1 56.3l.8-1.9 .7 1.9M45.4 55.7h.9M46 52.1a.61 .61 0 0 1 .9-.1 .61 .61 0 0 1 0 .9 .61 .61 0 0 1-.9-.1M46 51.1v2M46.2 45.5v1.9M46.4 41l.8-1.9 .7 1.9M46.7 40.4h.9M47.3 42.3h.7a1.03 1.03 0 0 1 .7 1 1.03 1.03 0 0 1-.7 .9h-.7z"/>
<path d="M48.3 45.5v1.9l-1.3-1.9v1.9M48.4 54.4v1.9l-1.2-1.9v1.9M49 45.5h.6a1.03 1.03 0 0 1 .7 1 1.03 1.03 0 0 1-.7 .9h-.6zM49.2 54.4h.6a1.02 1.02 0 0 1 .7 .9 1.02 1.02 0 0 1-.7 1h-.6zM49.3 43.2h.7M49.5 53.1l.7-2 .7 2M49.7 52.4h.9M50.5 42.3h-1.2v1.9h1.2M50.9 45.5v1.9M51 42.3h1.3M51.5 52.2h.8a.51 .51 0 0 0 .5-.5 .51 .51 0 0 0-.5-.6h-.8v2M51.7 42.3v1.9"/>
<path d="M51.7 40.6h1.3M51.8 40.1h1.3M52.7 44.2l.7-1.9 .7 1.9M52.9 43.6h1M53 46a.71 .71 0 0 0-.8-.5 .71 .71 0 0 0-.5 .8 .8 .8 0 0 0 .2 1 .8 .8 0 0 0 1-.1l.1-.2M53.1 54.4a.65 .65 0 0 1 .9 .3 1.65 1.65 0 0 1-.1 1.5 .63 .63 0 0 1-1-.3 1.56 1.56 0 0 1 .2-1.5zM53.4 52.2h.8a.51 .51 0 0 0 .5-.5 .51 .51 0 0 0-.5-.6h-.8v2M53.6 47.4l.7-1.9 .7 1.9M53.9 46.8h.9M54.7 42.3v1.9M54.8 56.1l-.1 .1h.2M55.3 51.1v2h1.1"/>
<path d="M55.4 42.3v1.9h1.1M55.6 45.5h1.3M55.8 54.4h1l-.6 .7a.64 .64 0 0 1 .6 1 .64 .64 0 0 1-1.1 0l-.1-.2M56.2 45.5v1.9M56.9 51.1v2M57.2 46.4h.8M57.6 52.1h.7M57.7 54.4a.63 .63 0 0 1 .9 .3 1.74 1.74 0 0 1-.2 1.5 .65 .65 0 0 1-.9-.3 1.65 1.65 0 0 1 .2-1.5zM58.3 42.6a.73 .73 0 0 0-.7-.3 .73 .73 0 0 0-.6 .5l.2 .2 .9 .4 .2 .5a.86 .86 0 0 1-1.3 0M58.4 45.5h-1.2v1.9h1.2M58.8 51.1h-1.2v2h1.2M59 45.5h.6a1.03 1.03 0 0 1 .7 1 1.03 1.03 0 0 1-.7 .9h-.6z"/>
<path d="M59.4 40h.7M60.6 51.4a.71 .71 0 0 0-.7-.3 .71 .71 0 0 0-.5 .5l.1 .3 1 .3a.47 .47 0 0 1 0 .8 .89 .89 0 0 1-1.1-.2M60.7 42.6a.7 .7 0 0 1 .8-.3 .7 .7 0 0 1 .5 .7 .84 .84 0 0 1-.2 1 .84 .84 0 0 1-.9 .1 1.2 1.2 0 0 1-.2-1.5zM61 47.3l-.1 .1h.2M61 55.4l.5-.4 .4 .1 .1 1.2M61 55v1.3M62 55.4l.5-.4 .4 .1 .1 1.2M62.6 43.2h.7M62.9 51.1h1.3M63.6 45.5h1.3M63.6 51.1v2M63.8 55.4l.4-.4 .5 .1 .1 1.2"/>
<path d="M63.8 55v1.3M63.8 42.3h-1.2v1.9M64.2 45.5v1.9M64.8 55.4l.4-.4 .5 .1 .1 1.2M64.8 51.4a.71 .71 0 0 1 .8-.2 .71 .71 0 0 1 .4 .7 .85 .85 0 0 1-.1 .9 .85 .85 0 0 1-1 .2 1.23 1.23 0 0 1-.1-1.6zM65.2 46.4h1.3M65.2 45.5v1.9M65.5 40h.7M66 42.3h1.2M66.5 45.5v1.9M66.6 42.3v1.9M67.2 46.4h.8"/>
<path d="M67.6 43.2h.7M67.9 40h.7M68.2 55.3h.8M68.3 53.1v-2l.8 2 .7-2v2M68.4 45.5h-1.2v1.9h1.2M68.8 42.3h-1.2v1.9h1.2M69.3 43.2h.9a.5 .5 0 0 0 .4-.5l-.4-.4h-.9v1.9M69.4 54.4h-1.2v1.9M69.6 40h.8a.5 .5 0 0 0 .5-.5l-.2-.3-.3-.1h-.8v1.9M69.9 55.3l1.1-.1a.44 .44 0 0 0 0-.8h-1.1v1.9M70 43.2l.6 1M70.3 40l.6 1"/>
<path d="M70.5 52.1h.8M70.5 55.3l.7 1M70.7 45.5h1.3M71.3 44.2v-1.9l.7 1.9 .7-1.9v1.9M71.4 45.5v1.9M71.7 51.1h-1.2v2h1.2M72.2 54.4a.89 .89 0 0 1 1 .4 .89 .89 0 0 1 0 1 .71 .71 0 0 1-.8 .5 .71 .71 0 0 1-.6-.8 1.19 1.19 0 0 1 .4-1.1zM72.3 51.1h1.3M72.4 46.4h.7M72.9 51.1v2M73.3 41l.7-1.9 .8 1.9M73.5 42.3v1.9"/>
<path d="M73.6 45.5h-1.2v1.9h1.2M73.6 40.4h.9M73.8 56.3v-1.9l.8 1.9 .7-1.9v1.9M73.9 53.1l.8-2 .7 2M74.1 46.4l1.1-.1 .2-.2-.1-.4-.4-.2h-.8v1.9M74.2 52.4h.9M74.8 46.4l.6 1M75.5 42.3v1.9l-1.3-1.9v1.9M76 51.1v2h1.1M76 47.4v-1.9l.8 1.9 .7-1.9v1.9M76.2 44.2l.8-1.9 .7 1.9M76.5 43.6h.9"/>
<path d="M77.5 51.1v2h1.1M77.8 54.4h1.3M78.2 42.3v1.9h1.1M78.2 45.5v1.9M78.4 54.4v1.9M79.1 51.1v2M79.4 55.3h.8M79.8 51.1h1.3l-1.3 2h1.3M80.3 45.5v1.9l-1.3-1.9v1.9M80.6 54.4h-1.2v1.9h1.2M81 47.4l.7-1.9 .8 1.9M81.2 55.3l1.1-.1a.44 .44 0 0 0 0-.8h-1.1v1.9"/>
<path d="M81.3 46.8h.9M81.5 43.9h1.3M81.6 43.3h1.3M81.6 52.1h.8M81.8 55.3l.7 1M82.3 42.3l-.7 2.6M82.6 40h.8M82.8 42.3l-.6 2.6M82.8 51.1h-1.2v2h1.2M83 45.5v1.9h1.1M83.1 56.3v-1.9l.7 1.9 .8-1.9v1.9M83.3 42.7l.4-.4v1.9"/>
<path d="M83.4 51.1h.6a1.02 1.02 0 0 1 .7 1 1.02 1.02 0 0 1-.7 1h-.6zM84.4 40l1.1-.1 .2-.2-.1-.4-.4-.2h-.8v1.9M85 40l.7 1M85.3 54.4v1.9M86.3 41v-1.9l.7 1.9 .8-1.9v1.9M86.3 47.1h1.3M86.4 46.5h1.3M86.5 42.3v1.9M87 45.5l-.6 2.6M87 51.1h1.3M87.2 42.3h.7a1.02 1.02 0 0 1 .7 1 1.02 1.02 0 0 1-.7 .9h-.7zM87.3 54.4v1.9l-1.3-1.9v1.9"/>
<path d="M87.6 45.5l-.6 2.6M87.7 51.1v2M88.1 45.9l.4-.4v1.9M88.1 56.3l.7-1.9 .7 1.9M88.3 55.7h.9M88.7 52.1h.7M89.2 43.2h.7M89.9 51.1h-1.2v2h1.2M90.1 54.4v1.9h1.1M90.3 42.3h-1.1v1.9h1.1M90.5 52.1l1.1-.1 .1-.3-.1-.4-.3-.2h-.8v2M91.1 52.1l.6 1"/>
<path d="M91.3 41l.7-1.9 .7 1.9M91.3 45.5v1.9M91.6 40.4h.9M92 45.5h.7a1.03 1.03 0 0 1 .6 1 1.03 1.03 0 0 1-.6 .9h-.7zM92.2 42.3v1.9l-1.3-1.9v1.9M92.4 53.1v-2l.7 2 .7-2v2M92.9 42.3h1.3M93.4 54.4h1.3M93.6 42.3v1.9M93.9 46.4h.8M94 54.4v1.9M94.6 42.3v1.9"/>
<path d="M94.6 51.1v2M95 54.4v1.9M95.1 45.5h-1.2v1.9h1.2M95.3 43.2h.7M95.8 55.4h.8a.51 .51 0 0 0 .5-.5 .51 .51 0 0 0-.5-.5h-.8v1.9M96.5 42.3h-1.2v1.9M96.6 51.1v2l-1.3-2v2M97 45.5v1.9l-1.3-1.9v1.9M97 42.3v1.9M97.3 53.1l.8-2 .7 2M97.6 52.4h.9M97.7 43.2h.7"/>
<path d="M97.7 45.5h1.3M97.8 56.1l-.1 .1h.2M98.3 45.5v1.9M98.9 42.3h-1.2v1.9h1.2M99.3 51.1v2h1.1M99.3 45.5v1.9M99.4 43.2l1.1-.1 .2-.3-.1-.3-.3-.2h-.9v1.9M100.1 43.2l.6 1M100.1 46.4h.7M100.6 41v-1.9l.8 1.9 .7-1.9v1.9M101.3 45.5h-1.2v1.9M101.7 45.5v1.9"/>
<path d="M102.5 46.4h.7M102.6 53.1l.8-2 .7 2M102.8 40l1.1-.1 .2-.2-.1-.4-.3-.2h-.9v1.9h.9a.51 .51 0 0 0 .4-.5 .51 .51 0 0 0-.4-.5M102.9 52.4h.9M103.1 44.2l.7-1.9 .8 1.9M103.4 43.6h.9M103.7 45.5h-1.2v1.9h1.2M104.2 46.4l1.1-.1 .2-.2-.1-.4-.4-.2h-.8v1.9M104.8 40h.7M104.8 46.4l.7 1M105.1 43.2h.8a.5 .5 0 0 0 .5-.5l-.5-.4h-.8v1.9M105.8 43.2l.6 1"/>
<path d="M105.9 51.1v2l-1.2-2v2M106.5 40h.8a.5 .5 0 0 0 .5-.5l-.2-.3-.3-.1h-.8v1.9M106.7 51.1h.6a1.03 1.03 0 0 1 .7 1 1.03 1.03 0 0 1-.7 1h-.6zM107 43.2h.8M107.1 40l.7 1M107.9 47.4v-1.9l.7 1.9 .7-1.9v1.9M108.2 42.3h-1.2v1.9h1.2M110.1 47.4l.7-1.9 .7 1.9M110.3 46.8h1M110.3 51.1v2M110.7 42.6a.71 .71 0 0 1 .8-.3 .71 .71 0 0 1 .5 .7 .85 .85 0 0 1-.2 .9 .85 .85 0 0 1-.9 .2 1.23 1.23 0 0 1-.2-1.5zM112.1 45.5l.7 .9 .8-.9"/>
<path d="M112.4 51.4a.71 .71 0 0 0-.7-.3 .71 .71 0 0 0-.6 .5l.2 .3 .9 .3a.47 .47 0 0 1 0 .8 .89 .89 0 0 1-1.1-.2M112.6 43.3h.8a.51 .51 0 0 0 .5-.5 .51 .51 0 0 0-.5-.5h-.8v1.9M112.8 46.4v1M114.5 42.3h1.3M114.7 53.1v-2l.7 2 .7-2v2M115.1 42.3v1.9M115.7 46.4l1.1-.1 .2-.2-.1-.4-.4-.2h-.8v1.9h.8a.51 .51 0 0 0 .5-.5 .51 .51 0 0 0-.5-.5M116.1 42.3v1.9M116.9 52.1h.7M117 42.6a.71 .71 0 0 1 .9-.3 .71 .71 0 0 1 .4 .7 .85 .85 0 0 1-.2 .9 .85 .85 0 0 1-.9 .2 1.23 1.23 0 0 1-.2-1.5zM117.6 46.4h.7M118.1 51.1h-1.2v2h1.2"/>
<path d="M118.6 53.1l.7-2 .8 2M118.8 45.5h-1.2v1.9h1.2M118.9 52.4h.9M120.2 42.3v1.9l-1.3-1.9v1.9M120.9 44.2l.7-1.9 .8 1.9M121.1 46.4h.7M121.2 43.6h.9M121.9 51.4a.73 .73 0 0 0-.7-.3 .73 .73 0 0 0-.6 .5l.2 .3 .9 .3 .2 .6a.86 .86 0 0 1-1.3 0M122.3 45.5h-1.2v1.9h1.2M122.5 51.1v1.4a.65 .65 0 0 0 .6 .6 .65 .65 0 0 0 .6-.6v-1.4M122.6 40h.8M122.8 45.5v1.9"/>
<path d="M122.9 42.3v1.9h1.1M123.6 45.5h1.2M124.2 45.5v1.9M124.5 52.1l1.1-.1 .2-.3-.1-.4-.4-.2h-.8v2M124.7 44.1h-.2h.2l-.2 .5M125.1 52.1l.7 1M125.2 46.4h1.3M125.2 45.5v1.9M126.4 52.1h.7M126.5 45.5v1.9M127.1 43.2h.9a.5 .5 0 0 0 .4-.5l-.4-.4h-.9v1.9h.9a.5 .5 0 0 0 .4-.5 .5 .5 0 0 0-.4-.5M127.2 46.4h.8"/>
<path d="M127.6 51.1h-1.2v2h1.2M128.2 51.1h.6a1.03 1.03 0 0 1 .6 1 1.03 1.03 0 0 1-.6 1h-.6zM128.4 45.5h-1.2v1.9h1.2M129 46.4l1.1-.1 .1-.2v-.4l-.4-.2h-.8v1.9M129.1 42.3v1.4a.65 .65 0 0 0 .6 .5 .65 .65 0 0 0 .7-.5v-1.4M129.6 46.4l.6 1M131.1 42.3h1.3M131.7 42.3v1.9M131.8 52.1h.8a.5 .5 0 0 0 .5-.6l-.5-.4h-.8v2h.8a.5 .5 0 0 0 .5-.5 .5 .5 0 0 0-.5-.5M132.6 47.4l.8-1.9 .7 1.9M132.9 46.8h.9M133.7 52.1h.8"/>
<path d="M134.5 44.2v-1.9l.7 1.9 .7-1.9v1.9M134.9 51.1h-1.2v2h1.2M135.5 51.1h1.3M136.1 51.1v2M136.4 47.4v-1.9l.7 1.9 .8-1.9v1.9M136.4 40h1.3M136.7 42.3v1.4a.64 .64 0 0 0 .6 .5 .64 .64 0 0 0 .7-.5v-1.4M137.1 51.1l.5 2 .5-2 .4 2 .5-2M138.4 41l.8-1.9 .7 1.9M138.7 40.4h.9M139 45.6a.93 .93 0 0 1 1.1 .4 .93 .93 0 0 1-.2 1.2 .79 .79 0 0 1-1.1 .1 .79 .79 0 0 1-.2-1zM139.3 52.1h.8"/>
<path d="M140 42.6a.73 .73 0 0 0-.7-.3 .73 .73 0 0 0-.6 .5l.2 .2 .9 .4 .2 .5a.86 .86 0 0 1-1.3 0M140.5 42.3h1.3M140.5 51.1h-1.2v2h1.2M140.6 45.5v1.9h1.1M141.1 52.1h.7M141.2 42.3v1.9M142.2 45.5h.6a1.03 1.03 0 0 1 .7 1 1.03 1.03 0 0 1-.7 .9h-.6zM142.3 51.1h-1.2v2h1.2M143.9 43.2h.8a.5 .5 0 0 0 .5-.5l-.5-.4h-.8v1.9h.8a.5 .5 0 0 0 .5-.5 .5 .5 0 0 0-.5-.5M144.1 51.1v2l-1.3-2v2M145.8 43.2h.8M146.2 45.6a.89 .89 0 0 1 1 .3 .89 .89 0 0 1 0 1.1 .71 .71 0 0 1-.8 .4 .71 .71 0 0 1-.6-.7 1.19 1.19 0 0 1 .4-1.1z"/>
<path d="M147 42.3h-1.2v1.9h1.2M147.9 46.4l1.1-.1 .1-.2v-.4l-.4-.2h-.8v1.9M148.5 46.4l.6 1M149.3 42.3v1.9h1.1M151.1 42.6l.2-.2a.91 .91 0 0 1 1.1 .4 .91 .91 0 0 1-.2 1.1 .71 .71 0 0 1-.8 .3 .71 .71 0 0 1-.5-.7zM151.3 40h.7M151.5 47.4v-1.9l.8 1.9 .7-1.9v1.9M153.7 47.4l.8-1.9 .7 1.9M154 46.8h.9M154.3 42.8a.71 .71 0 0 0-.8-.5 .71 .71 0 0 0-.6 .7 .84 .84 0 0 0 .2 1 .84 .84 0 0 0 .9 .1l.3-.3M154.8 44.2l.8-1.9 .7 1.9M154.9 40h.9a.5 .5 0 0 0 .4-.5l-.2-.3-.2-.1h-.9v1.9"/>
<path d="M155.1 43.6h.9M155.6 40l.6 1M155.8 46.4l1.1-.1a.44 .44 0 0 0 0-.7l-1.1-.1v1.9M156.4 46.4l.6 1M156.9 41v-1.9l.7 1.9 .7-1.9v1.9M156.9 42.3h1.2M157.5 42.3v1.9M157.7 45.5v1.9M158.1 46.3l.9 1.1M158.5 43.2h.7M159 45.5l-1.3 1.3M159.6 46.4h.7"/>
<path d="M159.7 42.3h-1.2v1.9h1.2M160.2 42.3h.7a1.03 1.03 0 0 1 .7 1 1.03 1.03 0 0 1-.7 .9h-.7zM160.8 45.5h-1.2v1.9h1.2M161.3 45.5h.7a1.02 1.02 0 0 1 .7 1 1.02 1.02 0 0 1-.7 .9h-.7zM163.9 42.3l.5 1.9 .4-1.9 .5 1.9 .4-1.9M165 46.4h.7M166.1 42.3v1.9M166.2 45.5h-1.2v1.9M166.7 46.4h.7M166.8 42.3h1.3M167.5 42.3v1.9M167.7 40h.7"/>
<path d="M167.9 45.5h-1.2v1.9h1.2M168.4 47.4l.7-1.9 .8 1.9M168.5 43.2h1.3M168.5 42.3v1.9M168.7 46.8h.9M169.8 42.3v1.9M170.4 45.5h1.3M170.5 42.3v1.9M171.1 45.5v1.9M172.1 45.5v1.4a.65 .65 0 0 0 .6 .5 .65 .65 0 0 0 .7-.5v-1.4M172.5 42.3v1.9l-1.3-1.9v1.9M174.1 46.4l1.1-.1 .2-.2-.1-.4-.4-.2h-.8v1.9"/>
<path d="M174.7 46.4l.7 1M176 46.4h.7M177.2 45.5h-1.2v1.9h1.2M177.8 47.3v.1h.1M178.6 40.2h1.6M22.8 63.8h1.3l-1 2M23 68.1a.37 .37 0 0 0 .1 .6 .72 .72 0 0 1 .8 .3 .72 .72 0 0 1 0 .8 .68 .68 0 0 1-.7 .1 .68 .68 0 0 1-.4-.6 1.13 1.13 0 0 1 1.1-.6v-.4a.72 .72 0 0 0-.9-.2zM24.2 76.3a.59 .59 0 0 1-.8 .5 .59 .59 0 0 1-.3-.9 .59 .59 0 0 1 1 .1 1.35 1.35 0 0 1-.5 1.6l-.4-.1-.1-.1M24.7 65.6l-.1 .1h.2M24.7 69.8v.1l.1-.1M24.9 77.4l-.1 .1 .1 .1 .1-.1M29 63.8h.6a1.03 1.03 0 0 1 .7 1 1.03 1.03 0 0 1-.7 1h-.6z"/>
<path d="M29 68h.6a1.03 1.03 0 0 1 .7 1 1.03 1.03 0 0 1-.7 .9h-.6zM29.2 75.7l.5 1.9 .4-1.9 .5 1.9 .5-1.9M29.7 71.6h1.3M30.4 71.6v1.9M30.9 68.9l1.1-.1 .2-.2-.1-.4-.3-.2h-.9v1.9M30.9 64.8h.8M31.4 77.6l.8-1.9 .7 1.9M31.6 68.9l.6 1M31.7 77h.9M32.1 63.8h-1.2v2h1.2M32.7 64.9h.8a.51 .51 0 0 0 .5-.5 .51 .51 0 0 0-.5-.6h-.8v2M32.8 72.9h-1.4l.9-1.3v1.9"/>
<path d="M32.9 69.9l.7-1.9 .7 1.9M33.1 69.3h.9M33.4 71.7a.37 .37 0 0 0 .2 .6 .72 .72 0 0 1 .7 .3 .72 .72 0 0 1 .1 .7 .68 .68 0 0 1-.8 .2 .68 .68 0 0 1-.4-.6 1.13 1.13 0 0 1 1.1-.7l.1-.3a.72 .72 0 0 0-1-.2zM33.5 76.6l1.1-.1 .1-.3-.1-.3-.3-.2h-.8v1.9M34.1 76.6l.6 1M34.8 64.1a.7 .7 0 0 1 .8-.2 .7 .7 0 0 1 .5 .7 .84 .84 0 0 1-.2 .9 .84 .84 0 0 1-.9 .2 1.2 1.2 0 0 1-.2-1.6zM34.9 68l.4 1.9 .5-1.9 .4 1.9 .5-1.9M35.1 71.6h1.2l-.9 1.9M35.4 76.7l1.1-.1 .1-.3v-.4l-.4-.2h-.8v1.9M36.6 64.9h.8a.51 .51 0 0 0 .5-.5 .51 .51 0 0 0-.5-.6h-.8v2M36.9 71.6h1.3l-.9 1.9M37.1 68v1.9"/>
<path d="M37.3 77.6l.7-1.9 .8 1.9M37.6 77h.9M38.5 63.8v1.4a.65 .65 0 0 0 .7 .6 .65 .65 0 0 0 .6-.6v-1.4M38.7 72.7h1.7M39.1 68v1.9l-1.3-1.9v1.9M39.5 71.9v1.6M40.6 63.8v2h1.1M40.7 76.1a.71 .71 0 0 0-.8-.4 .71 .71 0 0 0-.6 .7 .84 .84 0 0 0 .2 .9 .84 .84 0 0 0 .9 .2l.3-.3v-.3h-.5M41.2 68.5a.71 .71 0 0 0-.8-.5 .71 .71 0 0 0-.6 .7 .84 .84 0 0 0 .2 1 .84 .84 0 0 0 .9 .1l.3-.3v-.3h-.5M41.2 76.6h.8M41.3 71.6h1l-.6 .7a.64 .64 0 0 1 .5 1 .64 .64 0 0 1-1.1-.2M42.1 65.8l.7-2 .8 2"/>
<path d="M42.4 65.1h.9M42.4 75.7h-1.2v1.9h1.2M44.6 71.2l-1.7 3M44.8 63.8v2M44.9 68.5a.71 .71 0 0 0-.8-.5 .71 .71 0 0 0-.6 .7 .84 .84 0 0 0 .2 1 .84 .84 0 0 0 .9 .1l.3-.3M45 72.7h1.6M45.6 68.3a.71 .71 0 0 1 .8-.3 .71 .71 0 0 1 .5 .7 .84 .84 0 0 1-.2 1 .84 .84 0 0 1-.9 .1 1.15 1.15 0 0 1-.2-1.5zM45.8 63.8v2M45.8 71.9v1.6M46 76a.72 .72 0 0 0-.7-.3 .72 .72 0 0 0-.6 .4l.2 .3 .7 .3a.48 .48 0 0 1 .2 .8 .85 .85 0 0 1-1.1-.1M46.6 76.6h1.2M46.6 75.7v1.9"/>
<path d="M46.7 64.1l.2-.1a.91 .91 0 0 1 1.1 .3 .91 .91 0 0 1-.2 1.2 .71 .71 0 0 1-.8 .3 .71 .71 0 0 1-.5-.7zM47.8 75.7v1.9M48.6 77.6l.7-1.9 .7 1.9M48.7 68v1.9l-1.3-1.9v1.9M48.7 72.9h-1.4l1-1.3v1.9M48.9 77h.9M49.5 68.9h.7M49.8 63.8v2l-1.3-2v2M50.6 75.7v1.9h1.1M50.6 68h-1.1v1.9M50.8 71.2l-1.6 3M51.2 72.7h1.6"/>
<path d="M51.5 68.1a.96 .96 0 0 1 1.1 .7 .96 .96 0 0 1-.6 1.1 1.01 1.01 0 0 1-.9-.7 1.01 1.01 0 0 1 .4-1.1zM52 71.9v1.6M52.2 75.7v1.9h1.1M52.3 63.8v2M53.1 68.9l1.1-.1 .2-.2-.1-.4-.4-.2h-.8v1.9M53.8 68.9l.6 1M54.3 64.1a.73 .73 0 0 0-.7-.3 .73 .73 0 0 0-.6 .5l.2 .3 .9 .3 .2 .6a.86 .86 0 0 1-1.3 0M54.7 71.9a.57 .57 0 0 0-.8-.2 1.48 1.48 0 0 0 0 1.7 .59 .59 0 0 0 .8-.3 .59 .59 0 0 0-.4-.8 .59 .59 0 0 0-.7 .6M55 69.9v-1.9l.8 1.9 .7-1.9v1.9M56.6 64.9h.8a.51 .51 0 0 0 .5-.5 .51 .51 0 0 0-.5-.6h-.8v2M56.7 75.7v1.9l-1.2-1.9v1.9M57.8 75.8a.96 .96 0 0 1 1.2 .6 .96 .96 0 0 1-.6 1.2 1.01 1.01 0 0 1-1-.7 1.01 1.01 0 0 1 .4-1.1z"/>
<path d="M58.5 68.3a.74 .74 0 0 0-1.3 .2l.2 .2 .8 .3a.47 .47 0 0 1 .3 .4 .47 .47 0 0 1-.2 .4 .87 .87 0 0 1-1.1-.1M58.7 64.1a.71 .71 0 0 1 .8-.2 .71 .71 0 0 1 .5 .7 .85 .85 0 0 1-.2 .9 .85 .85 0 0 1-.9 .2 1.23 1.23 0 0 1-.2-1.6zM59 72.4l-.1-.2-.2 .1-.3 .7a.68 .68 0 0 1-.5 .5 .68 .68 0 0 1-.7-.4v-.3l.8-.5a.4 .4 0 0 0 .2-.4 .4 .4 0 0 0-.3-.3l-.2 .1a.73 .73 0 0 0 .2 .9l.6 .8 .4 .1 .1-.2M59.5 75.7h1.3M60.1 75.7v1.9M60.8 68h1.3M61.3 71.6h1.3M61.5 68v1.9M61.8 64.1a.73 .73 0 0 0-.7-.3 .73 .73 0 0 0-.6 .5l.2 .3 .9 .3 .2 .6a.86 .86 0 0 1-1.3 0M61.9 71.6v1.9M62.8 68.1a.96 .96 0 0 1 1.2 .7 .96 .96 0 0 1-.6 1.1 1.01 1.01 0 0 1-1-.7 1.01 1.01 0 0 1 .4-1.1zM62.9 76.6h.7"/>
<path d="M63.7 64.1a.71 .71 0 0 0-.7-.3 .71 .71 0 0 0-.6 .5l.2 .3 .9 .3a.47 .47 0 0 1 0 .8 .89 .89 0 0 1-1.1-.2M64 71.6h-.9l-.1 .8a.67 .67 0 0 1 1 0 .67 .67 0 0 1-.1 1 .67 .67 0 0 1-1-.3M64.1 75.7h-1.2v1.9h1.2M64.2 63.8v2M64.6 75.7l1.3 1.9M64.9 64.8h.9a.5 .5 0 0 0 .4-.6l-.4-.4h-.9v2h.9a.5 .5 0 0 0 .5-.5 .5 .5 0 0 0-.5-.5M65.9 71.9a.54 .54 0 0 0-.6-.3 .54 .54 0 0 0-.4 .4 1.12 1.12 0 0 0 .4 1.5 .6 .6 0 0 0 .7-.5 .6 .6 0 0 0-.6-.7 .6 .6 0 0 0-.6 .6M65.9 75.7l-1.3 1.9M66.6 71.6h1.3l-.9 1.9M66.9 63.8v2h1.1M67.1 68v1.5a.5 .5 0 0 1-.5 .4 .53 .53 0 0 1-.4-.6M67.7 68.9h.7"/>
<path d="M67.8 76.1a.71 .71 0 0 0-.8-.4 .71 .71 0 0 0-.5 .7 .83 .83 0 0 0 .1 1 .83 .83 0 0 0 1 .1l.2-.3M68.4 76.6h.7M68.4 71.6h1.3l-.9 1.9M68.4 64.8h.8M68.9 68h-1.2v1.9h1.2M69.4 68h.7a1.03 1.03 0 0 1 .7 1 1.03 1.03 0 0 1-.7 .9h-.7zM69.6 75.7h-1.2v1.9h1.2M69.6 63.8h-1.2v2h1.2M70.1 76.6h.8M70.3 72.7h1.6M71.1 71.9v1.6M71.3 75.7h-1.2v1.9h1.2"/>
<path d="M71.4 68.9h.7M71.9 75.7h.6a1.03 1.03 0 0 1 .7 1 1.03 1.03 0 0 1-.7 .9h-.6zM71.9 63.8v2M72.6 68h-1.2v1.9h1.2M72.7 72l.4-.4v1.9M73.9 63.8v2l-1.2-2v2M74.2 73.3l-.1 .1 .1 .1 .1-.1M74.5 68.5a.71 .71 0 0 0-.8-.5 .71 .71 0 0 0-.6 .7 .83 .83 0 0 0 .2 1 .83 .83 0 0 0 .9 .1l.3-.3M75.8 75.8a.63 .63 0 0 1 .9 .3 1.27 1.27 0 0 1-.4 1.5h-.2a1.24 1.24 0 0 1-.3-1.8zM76.4 65.8l.7-2 .8 2M76.7 65.1h.9M76.8 69.9v-1.9l.7 1.9 .7-1.9v1.9"/>
<path d="M77.5 77.4l-.1 .1 .1 .1 .1-.1M78.3 76.1l.4-.4v1.9M79.3 68.1a.96 .96 0 0 1 1.2 .7 .96 .96 0 0 1-.6 1.1 1.01 1.01 0 0 1-1-.7 1.01 1.01 0 0 1 .4-1.1zM80 75.8a.63 .63 0 0 1 .9 .3 .99 .99 0 0 1-.6 1.5 1.24 1.24 0 0 1-.3-1.8zM81.1 68.5l.1-.3a.63 .63 0 0 1 .9 0 .57 .57 0 0 1-.2 .8l-.9 .9h1.3M81.5 64.1a.73 .73 0 0 0-.7-.3 .73 .73 0 0 0-.6 .5l.2 .3 .9 .3 .2 .6a.86 .86 0 0 1-1.3 0M82 63.8l.7 1 .8-1M82.7 64.8v1M82.9 68.5l.1-.3a.63 .63 0 0 1 .9 0 .61 .61 0 0 1-.2 .8l-.9 .9h1.3M83.3 76.7l.5-.4 .5 .1v1.2M83.3 76.3v1.3M83.8 65.8v-2l.8 2 .7-2v2"/>
<path d="M84.3 76.7l.5-.4 .5 .1 .1 1.2M84.9 68.1a.63 .63 0 0 1 1 .3 1.27 1.27 0 0 1-.5 1.5h-.2a1.24 1.24 0 0 1-.3-1.8zM86 65.8v-2l.8 2 .7-2v2M86.1 76.7l.4-.4 .5 .1 .1 1.2M86.1 76.3v1.3M87.1 76.7l.5-.4 .4 .1 .1 1.2M88.3 64.8h.7M88.3 68.9h.7M88.9 77.4v.2l.1-.1M89.4 63.8h-1.1v2h1.1M89.4 68h-1.1v1.9h1.1M90 68l1.3 1.9"/>
<path d="M90.6 63.8v2M91.3 68l-1.3 1.9M91.6 64.8h.9a.5 .5 0 0 0 .4-.6l-.4-.4h-.9v2M92.3 64.8l.6 1M93.2 68.5a.71 .71 0 0 0-.8-.5 .71 .71 0 0 0-.6 .7 .83 .83 0 0 0 .2 1 .83 .83 0 0 0 .9 .1l.3-.3M93.6 63.8v2M93.8 68.9h.7M94.9 68h-1.1v1.9h1.1M95.5 69h.8a.5 .5 0 0 0 .5-.5 .5 .5 0 0 0-.5-.5h-.8v1.9M95.7 64.3a.71 .71 0 0 0-.8-.5 .71 .71 0 0 0-.6 .8 .84 .84 0 0 0 .2 .9 .84 .84 0 0 0 .9 .2l.3-.4M96.2 65.8l.8-2 .7 2M96.5 65.1h.9"/>
<path d="M97.4 68h1.3M98.1 68v1.9M98.2 63.8v2h1.1M100.8 68h1.3M101.5 68v1.9M101.5 64.8h.8M102.5 68.9h1.2M102.5 68v1.9M102.7 63.8h-1.2v2M103.2 65.8l.7-2 .8 2M103.5 65.1h.9M103.7 68v1.9"/>
<path d="M104.5 68.9h.7M105.7 68h-1.2v1.9h1.2M106.5 64.1a.73 .73 0 0 0-.7-.3 .73 .73 0 0 0-.6 .5l.2 .3 .9 .3 .2 .6a.86 .86 0 0 1-1.3 0M107 64.8h1.3M107 63.8v2M108 68.9h.7M108.3 63.8v2M109.1 63.8v2M109.2 68h-1.2v1.9h1.2M109.7 68l1.3 1.9M110 64.1a.7 .7 0 0 1 .8-.2 .7 .7 0 0 1 .5 .7 .84 .84 0 0 1-.2 .9 .84 .84 0 0 1-.9 .2 1.2 1.2 0 0 1-.2-1.6zM111 68l-1.3 1.9"/>
<path d="M111.5 69l1.1-.1a.5 .5 0 0 0 .2-.5 .5 .5 0 0 0-.4-.4h-.9v1.9M113.1 63.8v2l-1.3-2v2M113.7 68.3a.71 .71 0 0 1 .8-.3 .71 .71 0 0 1 .4 .7 .84 .84 0 0 1-.1 1 .84 .84 0 0 1-1 .1 1.15 1.15 0 0 1-.1-1.5zM113.9 65.6l-.1 .1h.2M116.8 68.3a.72 .72 0 0 0-.7-.3 .72 .72 0 0 0-.6 .5l.2 .2 .7 .3a.48 .48 0 0 1 .2 .8 .85 .85 0 0 1-1.1-.1M117.3 68.9h.8M118.5 68h-1.2v1.9h1.2M119.1 68h.6a1.03 1.03 0 0 1 .7 1 1.03 1.03 0 0 1-.7 .9h-.6zM122.7 69h.9a.5 .5 0 0 0 .4-.5 .5 .5 0 0 0-.4-.5h-.9v1.9M124.7 69.9l.7-1.9 .7 1.9M124.9 69.3h.9M126.7 68h.6a1.03 1.03 0 0 1 .7 1 1.03 1.03 0 0 1-.7 .9h-.6z"/>
<path d="M130.4 68h.6a1.03 1.03 0 0 1 .7 1 1.03 1.03 0 0 1-.7 .9h-.6zM132.3 68v1.9M133 69.9v-1.9l.7 1.9 .8-1.9v1.9M135.2 68.9h.7M136.4 68h-1.2v1.9h1.2M138.2 68v1.9l-1.2-1.9v1.9M140.3 68.3a.74 .74 0 0 0-1.3 .2l.3 .3 .8 .3 .2 .6a.86 .86 0 0 1-1.3 0M140.8 68v1.9M141.7 68.3a.71 .71 0 0 1 .8-.3 .71 .71 0 0 1 .5 .7 .84 .84 0 0 1-.2 1 .84 .84 0 0 1-.9 .1 1.15 1.15 0 0 1-.2-1.5zM144.8 68v1.9l-1.2-1.9v1.9M146.9 68.3a.74 .74 0 0 0-1.3 .2l.3 .3 .8 .3 .2 .6a.86 .86 0 0 1-1.3 0M149.5 68.1a.96 .96 0 0 1 1.2 .7 .96 .96 0 0 1-.6 1.1 1.01 1.01 0 0 1-1-.7 1.01 1.01 0 0 1 .4-1.1z"/>
<path d="M151.2 68.9h.7M152.4 68h-1.2v1.9M22.4 81.7l.5-.3v1.9M22.4 91.1l.5-.4v1.9M22.4 99.4l.5-.4v2M24 91.2l.3-.5h.4l.3 .2a.61 .61 0 0 1-.2 .8l-.9 .9h1.3M24.1 99h1l-.6 .8a.64 .64 0 0 1 .6 .9 .64 .64 0 0 1-1 .2l-.2-.3M24.2 81.4a.63 .63 0 0 1 .9 .3 .97 .97 0 0 1-.7 1.6 1.03 1.03 0 0 1-.4-1.6zM25.8 83.1l-.1 .1h.2M25.8 92.4l-.1 .1h.2M28.2 95.8v-1.9l.6 1.3 .7-1.3v1.9M28.4 83.3v-1.9l.7 1.9 .8-1.9v1.9"/>
<path d="M28.4 92.6v-1.9l.6 1.3 .7-1.3v1.9M30.1 93.9v1.6l.3 .3h.7l.3-.3v-1.6M30.3 92.6v-.6l.7-1.3 .6 1.3v.6M30.3 92h1.3M30.4 99v2h1.1M30.6 83.3l.7-1.9 .8 1.9M30.8 82.6h1M31.9 99v2h1.1M32.2 90.7h1.3M32.6 82.3l1.1-.1 .2-.3-.1-.4-.4-.1h-.8v1.9M32.9 90.7v1.9M33.2 82.3l.7 1"/>
<path d="M33.3 94.2l-.3-.3h-.6l-.3 .3 1.2 1.3-.3 .3h-.6l-.3-.3M34 93.9h1.2M34.1 91.7h.7M34.5 81.4v1.9M34.6 93.9v1.9M35 82.2l.8 1.1M35.2 99h.7a1.03 1.03 0 0 1 .7 1 1.03 1.03 0 0 1-.7 1h-.7zM35.4 90.7h-1.3v1.9h1.3M35.8 81.4l-1.3 1.2M36.1 91.7h.9l.4-.4v-.3l-.4-.3h-.9v1.9M36.4 91.7l1 .9M36.5 81.4v1.9"/>
<path d="M37.2 99v2M37.8 93.9h1l.3 .3v.3l-.3 .4M38 90.7h.7M38 92.6h.7M38.1 94.9h.7l.3 .3v.3l-.3 .3h-1M38.1 93.9v1.9M38.3 90.7v1.9M38.5 81.4v1.9l-1.3-1.9v1.9M39.3 92.6v-.6l.6-1.3 .7 1.3v.6M39.3 92h1.3M39.8 94.9h.6M40.1 99.9h.8"/>
<path d="M40.6 81.8a.71 .71 0 0 0-.8-.5 .71 .71 0 0 0-.6 .8 .79 .79 0 0 0 .2 1 .79 .79 0 0 0 1.1-.1l.1-.5h-.5M41 93.9h-1.2v1.9h1.2M41.2 90.7v1.9h1.3M41.3 99h-1.2v2h1.2M42.9 81.4v1.9M43.1 99v2l-1.2-2v2M43.6 94.9h.6M44.9 93.9h-1.3v1.9h1.3M44.9 81.6a.73 .73 0 0 0-.7-.3 .73 .73 0 0 0-.6 .5l.2 .3 .7 .3a.46 .46 0 0 1 .4 .3 .46 .46 0 0 1-.2 .5 .9 .9 0 0 1-1.1-.2M45.1 92.6v-1.9l.6 1.3 .6-1.3v1.9M45.2 99.3a.73 .73 0 0 0-.7-.3 .73 .73 0 0 0-.6 .5l.2 .3 .7 .2a.46 .46 0 0 1 .4 .4 .46 .46 0 0 1-.2 .5 .9 .9 0 0 1-1.1-.2M45.5 94.5v1l.4 .3h.3l.6-.6"/>
<path d="M45.7 99v2M46.6 99.3a.8 .8 0 0 1 1.1-.1 .8 .8 0 0 1 .2 1 .73 .73 0 0 1-.7 .8 .73 .73 0 0 1-.8-.8zM46.8 94.5v1.3M47 90.7v1.6l.3 .3h.6l.4-.3v-1.6M47.2 82.3h.7M48.4 81.4h-1.2v1.9M49 81.6a.71 .71 0 0 1 .8-.2 .71 .71 0 0 1 .5 .7v.4a.74 .74 0 0 1-.7 .8 .74 .74 0 0 1-.8-.8zM49.4 94.9h.9l.4-.4v-.3l-.4-.3h-.9v1.9M49.7 94.9l1 .9M49.7 99v2l-1.2-2v2M50.2 91l-.3-.3h-.7l-.3 .3 1.3 1.3-.3 .3h-.7l-.3-.3M50.8 82.3l1.2-.1 .1-.3-.1-.4-.3-.1h-.9v1.9"/>
<path d="M50.8 90.7h1.3M51.3 93.9h1.3v1.9h-1.3zM51.5 82.3l.6 1M51.5 90.7v1.9M51.8 99.3a.73 .73 0 0 0-.7-.3 .73 .73 0 0 0-.6 .5l.2 .3 .7 .2a.46 .46 0 0 1 .4 .4 .46 .46 0 0 1-.2 .5 .9 .9 0 0 1-1.1-.2M53.2 94.9h1.3M53.2 93.9v1.9M54.5 82.4h.8a.51 .51 0 0 0 .5-.5 .51 .51 0 0 0-.5-.5h-.8v1.9M54.5 93.9v1.9M54.7 90.7h1l.3 .3v.3l-.3 .4M55 90.7v1.9M55 91.7h.7l.3 .3v.3l-.3 .3h-1"/>
<path d="M56.4 94.2l-.3-.3h-.6l-.4 .3 1.3 1.3-.3 .3h-.6l-.4-.3M56.4 83.3l.8-1.9 .7 1.9M56.6 91.7h.7M56.7 82.6h.9M57.9 90.7h-1.3v1.9h1.3M59.8 81.8a.71 .71 0 0 0-.8-.5 .71 .71 0 0 0-.6 .8v.4a.71 .71 0 0 0 .6 .8 .71 .71 0 0 0 .8-.5M59.9 99v2h1.1M60.3 94.2l-.3-.3h-.7l-.3 .3v1.3l.3 .3h.7l.3-.3M60.4 81.4v1.9M60.8 82.2l.9 1.1M60.9 93.9h1.3v1.9h-1.3zM61.5 99l.7 .9 .8-.9"/>
<path d="M61.7 81.4l-1.3 1.2M61.8 91l-.4-.3h-.6l-.3 .3v1.3l.3 .3h.6l.4-.3M62.2 99.9v1.1M62.3 83.3l.7-1.9 .8 1.9M62.4 90.7h1.3v1.9h-1.3zM62.6 82.6h.9M62.9 95.8v-1.9l.6 1.3 .6-1.3v1.9M64.3 92.6v-1.9l.7 1.3 .6-1.3v1.9M64.8 94.9h1l.3-.4v-.3l-.3-.3h-1v1.9M65.1 99h1.2M65.7 81.8a.71 .71 0 0 0-.8-.5 .71 .71 0 0 0-.6 .8 .79 .79 0 0 0 .3 1 .79 .79 0 0 0 1-.1l.1-.5h-.5M65.7 99v2"/>
<path d="M66.3 91.7h.9l.3-.4v-.3l-.3-.3h-.9v1.9M66.3 82.3h.7M66.7 93.9v1.9h1.3M66.9 99.3a.71 .71 0 0 1 .8-.3 .71 .71 0 0 1 .5 .8v.4a.74 .74 0 0 1-.8 .8 .74 .74 0 0 1-.7-.8zM67.4 81.4h-1.1v1.9h1.1M68.2 90.7v1.9h1.3M68.6 93.9h.7M68.6 95.8h.7M69 93.9v1.9M69.9 95.8v-.6l.7-1.3 .6 1.3v.6M69.9 95.2h1.3M69.9 81.6a.71 .71 0 0 1 .8-.2 .71 .71 0 0 1 .5 .7v.4a.74 .74 0 0 1-.7 .8 .74 .74 0 0 1-.8-.8z"/>
<path d="M70.1 90.7h.6M70.1 92.6h.6M70.4 90.7v1.9M70.5 99.9h1.1a.44 .44 0 0 0 0-.8l-1.1-.1v2h.8a.51 .51 0 0 0 .5-.6 .51 .51 0 0 0-.5-.5M71.4 92.6v-.6l.6-1.3 .7 1.3v.6M71.4 92h1.3M71.8 82.3l1.1-.1 .1-.3-.1-.4-.3-.1h-.8v1.9M72.4 82.3l.6 1M72.8 99.1a.89 .89 0 0 1 1 .3 .89 .89 0 0 1 0 1.1 .71 .71 0 0 1-.8 .5 .71 .71 0 0 1-.6-.8 1.19 1.19 0 0 1 .4-1.1zM73.1 93.9v1.9l-1.3-1.9v1.9M73.7 81.4v1.9M73.8 93.9h1.3"/>
<path d="M74.4 82.3h.7M74.4 93.9v1.9M74.4 99h1.3M74.6 90.7v1.9l-1.3-1.9v1.9M75.1 99v2M75.2 90.7h1.3M75.6 81.4h-1.2v1.9h1.2M75.9 90.7v1.9M76.1 99.9h1.3M76.1 99v2M77.4 99v2M77.4 81.4v1.9l-1.2-1.9v1.9"/>
<path d="M77.6 93.9l.7 1.9 .3-.9 .3 .9 .7-1.9M78.2 81.4h1.3M78.8 81.4v1.9M79.1 90.7l.6 1.9 .4-.9 .3 .9 .6-1.9M79.8 83.3l.8-1.9 .7 1.9M79.8 99v2h1.1M80.1 82.6h.9M80.2 93.9h.6M80.2 95.8h.6M80.5 93.9v1.9M81.4 99.9h.7M81.5 93.9h1.3"/>
<path d="M81.7 90.7h.6M81.7 92.6h.6M81.8 81.4h1.3M82 90.7v1.9M82.1 93.9v1.9M82.5 81.4v1.9M82.6 99h-1.2v2h1.2M82.9 90.7h1.3M83.4 94.9h1.3M83.4 93.9v1.9M83.5 81.4v1.9M83.6 90.7v1.9"/>
<path d="M84.6 81.4a.89 .89 0 0 1 1 .3 .89 .89 0 0 1 0 1.1 .71 .71 0 0 1-.8 .5 .71 .71 0 0 1-.6-.8 1.19 1.19 0 0 1 .4-1.1zM84.7 93.9v1.9M84.9 91.7h1.3M84.9 90.7v1.9M85.1 99h.7a1.03 1.03 0 0 1 .7 1 1.03 1.03 0 0 1-.7 1h-.7zM85.3 93.9h1.3v1.9h-1.3zM86.2 90.7v1.9M87.1 99.9h.7M87.3 93.9v1.6l.3 .3h.6l.3-.3v-1.6M87.5 81.4v1.9l-1.3-1.9v1.9M88.3 99h-1.2v2h1.2M88.7 92.6v-1.9l.7 1.3 .6-1.3v1.9"/>
<path d="M88.8 99h.7a1.03 1.03 0 0 1 .6 1 1.03 1.03 0 0 1-.6 1h-.7zM89.2 93.9h1.3M89.8 93.9v1.9M90 82.3l1.1-.1a.44 .44 0 0 0 0-.8h-1.1v1.9M90.6 92.6v-.6l.7-1.3 .6 1.3v.6M90.6 82.3l.7 1M90.6 92h1.3M91.9 82.3h.8M92.6 90.7l1.3 1.9M93 94.9h.7M93.1 81.4h-1.2v1.9h1.2M93.1 98.7a1.98 1.98 0 0 0 0 2.9"/>
<path d="M93.7 82.3h.7M93.9 90.7l-1.3 1.9M94.3 93.9h-1.3v1.9h1.3M94.5 90.7h.7M94.5 92.6h.7M94.8 90.7v1.9M94.9 81.4h-1.2v1.9M95 93.9l1.3 1.9M95.3 82.3h.8M95.8 92.6v-1.9l.6 1.3 .7-1.3v1.9M96.1 98.7a1.94 1.94 0 0 1 0 2.9M96.3 93.9l-1.3 1.9"/>
<path d="M96.5 81.4h-1.2v1.9h1.2M96.9 94.9h.6M97.1 82.3l1.1-.1 .1-.3v-.4l-.4-.1h-.8v1.9M97.7 82.3l.6 1M98.2 93.9h-1.3v1.9h1.3M98.8 95.8v-1.9l.6 1.3 .7-1.3v1.9M99 82.3h.7M100.2 81.4h-1.2v1.9h1.2M100.7 94.9h1l.3-.4v-.3l-.3-.3h-1v1.9M100.9 91l-.3-.3h-.6l-.4 .3 1.3 1.3-.3 .3h-.6l-.4-.3M101.6 91.7h.9l.4-.4v-.3l-.4-.3h-.9v1.9M102 81.4v1.9l-1.3-1.9v1.9"/>
<path d="M102.5 99v2l-1.3-2v2M102.7 93.9h1.3M103.2 99h.7a1.02 1.02 0 0 1 .6 1 1.02 1.02 0 0 1-.6 1h-.7zM103.3 93.9v1.9M103.5 91.7h.6M104.1 81.8a.71 .71 0 0 0-.8-.5 .71 .71 0 0 0-.5 .8v.4a.71 .71 0 0 0 .5 .8 .71 .71 0 0 0 .8-.5M104.6 93.9h.6M104.6 95.8h.6M104.7 82.3h.7M104.8 90.7h-1.3v1.9h1.3M104.9 93.9v1.9M105.9 93.9h1.3v1.9h-1.3z"/>
<path d="M105.9 81.4h-1.2v1.9h1.2M106.7 91l-.3-.3h-.7l-.3 .3v1.3l.3 .3h.7l.3-.3M107.3 90.7h.7M107.3 92.6h.7M107.7 90.7v1.9M108.5 81.4a.89 .89 0 0 1 1.1 .3 .89 .89 0 0 1-.1 1.1 .71 .71 0 0 1-.8 .5 .71 .71 0 0 1-.5-.8 1.19 1.19 0 0 1 .3-1.1zM108.6 91.7h.7M108.8 99.9a.62 .62 0 0 1 .9-.1 .62 .62 0 0 1 0 1 .62 .62 0 0 1-.9-.1M108.8 99v2M109.1 93.9v1.9l-1.3-1.9v1.9M109.9 90.7h-1.3v1.9M110.6 90.7h.6"/>
<path d="M110.6 92.6h.6M110.6 99.9h.7M110.9 90.7v1.9M111.5 81.4v1.9l-1.3-1.9v1.9M111.7 95.8v-.6l.6-1.3 .6 1.3v.6M111.7 95.2h1.2M111.7 99h-1.1v2M112.2 81.4v1.9h1.1M112.2 99.9h1.1l.2-.3-.1-.4-.4-.2h-.8v2M112.8 99.9l.7 1.1M113.1 91l-.3-.3h-.7l-.3 .3v1.3l.3 .3h.7l.3-.3M113.8 81.4l.7 .9 .7-.9"/>
<path d="M113.8 92.6v-.6l.6-1.3 .6 1.3v.6M113.8 92h1.2M114.1 99.9h.8M114.5 82.3v1M114.9 93.9v1.9l-1.3-1.9v1.9M115.3 99h-1.2v2h1.2M115.5 93.9h1l.3 .3v1.3l-.3 .3h-1M115.7 83.1l-.1 .1h.2M115.7 90.7h1.3M115.8 93.9v1.9M115.9 99.9h.7M116.3 90.7v1.9"/>
<path d="M117.1 99h-1.2v2h1.2M117.6 90.7h.7M117.6 92.6h.7M117.9 90.7v1.9M118.9 90.7h1.3v1.9h-1.3zM119.4 94.9h.9l.3-.4v-.3l-.3-.3h-.9v1.9M120 98.7a1.98 1.98 0 0 0 0 2.9M121.3 93.9h.9l.4 .3v.3l-.4 .4M121.5 99.3v1.7M121.6 93.9v1.9M121.6 94.9h.6l.4 .3v.3l-.4 .3h-.9M122.1 90.7v1.9l-1.3-1.9v1.9"/>
<path d="M123 98.7a1.98 1.98 0 0 1 0 2.9M123.2 94.9h1.3M124.7 91l.3-.3v1.9M124.7 92.6h.6M125.1 94.9h.7M126.3 90.7h.3l.3 .3v1.3l-.3 .3h-.3l-.3-.3v-1.3zM126.4 93.9h-1.3v1.9M127.1 94.9h.9l.3-.4v-.3l-.3-.3h-.9v1.9M127.4 94.9l.9 .9M127.6 91.7h1.2M128 99v2M128.4 99.9l.9 1.1"/>
<path d="M129 94.9h.6M129.3 99l-1.3 1.3M129.5 91l.3-.3h.3l.4 .3v1.3l-.4 .3h-.3l-.3-.3zM130.3 93.9h-1.3v1.9h1.3M130.9 94.9h.7M131.1 91l.3-.3v1.9M131.1 92.6h.6M131.3 99.5a.71 .71 0 0 0-.8-.5 .71 .71 0 0 0-.6 .8 .8 .8 0 0 0 .2 1 .8 .8 0 0 0 1.1-.1l.1-.5h-.5M132.2 93.9h-1.3v1.9h1.3M132.4 91l.3-.3h.6l.4 .3v.3l-.4 .4h-.3M132.8 95.5v.3M133.3 91.7l.4 .3v.3l-.4 .3h-.6l-.3-.3"/>
<path d="M134.3 91l.3-.3v1.9M134.3 92.6h.6M135.9 99.5a.71 .71 0 0 0-.8-.5 .71 .71 0 0 0-.6 .8 .79 .79 0 0 0 .2 1 .79 .79 0 0 0 1.1-.1l.1-.2M136.6 99.3a.8 .8 0 0 1 1-.1 .8 .8 0 0 1 .3 1 .73 .73 0 0 1-.7 .8 .73 .73 0 0 1-.8-.8zM137.5 91.7h.7M138.4 99h.7a1.02 1.02 0 0 1 .7 1 1.02 1.02 0 0 1-.7 1h-.7zM138.8 90.7h-1.3v1.9M139.5 90.7h1.2v1.9h-1.2zM140.4 99.9h.7M141.4 91.7h.9l.3-.4v-.3l-.3-.3h-.9v1.9M141.5 99h-1.1v2h1.1M141.7 91.7l.9 .9"/>
<path d="M143.4 99.3a.73 .73 0 0 0-.7-.3 .73 .73 0 0 0-.6 .5l.2 .3 .7 .2a.46 .46 0 0 1 .4 .4 .46 .46 0 0 1-.2 .5 .9 .9 0 0 1-1.1-.2M146.5 91l-.3-.3h-.7l-.3 .3 1.3 1.3-.3 .3h-.7l-.3-.3M147.1 90.7v1.6l.4 .3h.6l.3-.3v-1.6M149.1 90.7h.9l.4 .3v.3l-.4 .4M149.4 91.7h.6l.4 .3v.3l-.4 .3h-.9M149.4 90.7v1.9M152.3 91l-.3-.3h-.7l-.3 .3 1.3 1.3-.3 .3h-.7l-.3-.3M152.9 90.7h1.3M153.6 90.7v1.9M154.8 92.6v-.6l.7-1.3 .6 1.3v.6M154.8 92h1.3M158.1 90.7v1.9l-1.3-1.9v1.9"/>
<path d="M160 91l-.3-.3h-.7l-.3 .3v1.3l.3 .3h.7l.3-.3M160.6 91.7h.7M161.9 90.7h-1.3v1.9h1.3M165.8 91l-.4-.3h-.6l-.3 .3v1.3l.3 .3h.6l.4-.3M166.4 90.7h1.3v1.9h-1.3zM169.6 90.7v1.9l-1.3-1.9v1.9M170.3 90.7h1.2M170.9 90.7v1.9M172.2 91.7h.6M173.5 90.7h-1.3v1.9h1.3M175.4 90.7v1.9l-1.3-1.9v1.9M176 90.7h1.3"/>
<path d="M176.7 90.7v1.9M178.3 92.3v.3l-.3 .3M25.8 100.8l-.1 .1h.2M28.4 101l.7-2 .8 2M28.6 100.3h1M37.9 101v-2l.8 2 .7-2v2M54 101l.8-2 .7 2M54.3 100.3h1M56.1 100h.8a.51 .51 0 0 0 .5-.5 .51 .51 0 0 0-.5-.5h-.8v2M58 100h.8a.51 .51 0 0 0 .5-.5 .51 .51 0 0 0-.5-.5h-.8v2M83.1 101l.8-2 .7 2M83.4 100.3h.9"/>
<path d="M93.8 100.1h1.6M99.2 101l.7-2 .8 2M99.4 100.3h1M106.9 100l1.1-.1a.5 .5 0 0 0 .2-.5 .5 .5 0 0 0-.5-.4h-.8v2M120.6 100.1h1.7M126.1 100h.8a.51 .51 0 0 0 .5-.5 .51 .51 0 0 0-.5-.5h-.8v2M131.9 100.8l-.1 .1h.2M144 100.8l-.1 .1h.2M268.7 170.2h-81.9v35.3M186.8 186.7h81.9M186.8 197.4h81.9M187.9 191.5l1.3-.1a.62 .62 0 0 0 .2-.6 .62 .62 0 0 0-.5-.5h-1v2.3"/>
<path d="M187.9 187.6h1M188.1 193.9h1.2l-.6 .9a.73 .73 0 0 1 .7 .8 .73 .73 0 0 1-.9 .6l-.4-.1-.2-.3M188.4 187.6v1.5M189.2 187.6v1.5M189.7 187.6h1M190.2 192.6l.9-2.3 .8 2.3M190.2 194.5l.1-.4a.76 .76 0 0 1 1-.1 .53 .53 0 0 1 .1 .8l-1.3 1.4h1.5M190.2 187.6v1.5M190.5 191.9h1.1M191 187.6v1.5h.8M192.2 188.3h.5M192.5 196.1l-.1 .1-.1-.1 .1-.1 .1 .1-.2 .6"/>
<path d="M193.1 187.6h-.9v1.5h.9M193.6 188.1v.1zM193.6 188.9v.2zM194.2 190.9a.84 .84 0 0 0-.9-.6 .84 .84 0 0 0-.7 .9 1 1 0 0 0 .2 1.1 1 1 0 0 0 1.1 .2l.3-.4M194.9 190.3v2.3M195.4 191.3l1 1.3M196.4 190.3l-1.5 1.6M197.1 195.5h-1.7l1.1-1.6v2.3M197.2 192.6l.9-2.3 .9 2.3M197.5 191.9h1.1M199.3 195.5h-1.7l1.1-1.6v2.3M200 196.1l-.1 .1-.1-.1 .1-.1 .1 .1-.2 .6"/>
<path d="M201.2 190.9a.84 .84 0 0 0-.9-.6 .84 .84 0 0 0-.7 .9 1 1 0 0 0 .2 1.1 1 1 0 0 0 1.1 .2l.3-.4v-.3h-.5M201.9 191.4h.9M203.3 190.3h-1.4v2.3h1.4M204.6 195.5h-1.6l1.1-1.6v2.3M205.4 194a.46 .46 0 0 0 .2 .8 .93 .93 0 0 1 1.1 1 .8 .8 0 0 1-.9 .4 .8 .8 0 0 1-.6-.7 1.06 1.06 0 0 1 1.1-.7 .46 .46 0 0 0 .2-.8l-.3-.1zM206.5 190.4a1.06 1.06 0 0 1 1.2 .4 1.06 1.06 0 0 1 0 1.3 .85 .85 0 0 1-1 .5 .85 .85 0 0 1-.7-.8 1.51 1.51 0 0 1 .5-1.4zM207.6 196.1l-.1 .1-.1-.1 .1-.1 .1 .1-.2 .6M208.5 190.3v1.7a.77 .77 0 0 0 .7 .7 .77 .77 0 0 0 .8-.7v-1.7M210.9 190.3h1.5M211.6 190.3v2.3M211.8 193.9h-1l-.2 1a.82 .82 0 0 1 1.3 0 .82 .82 0 0 1-.2 1.2 .82 .82 0 0 1-1.2-.3M212.8 190.3v2.3h1.4"/>
<path d="M213.4 197.4v8.1M214 194.3a.65 .65 0 0 0-.6-.4 .65 .65 0 0 0-.6 .5 1.7 1.7 0 0 0 .2 1.7 .71 .71 0 0 0 1.1-.3 .71 .71 0 0 0-.5-1 .71 .71 0 0 0-.9 .7M214.1 198.3a.83 .83 0 0 1 .9 .4 .83 .83 0 0 1-.2 1.1h-.7zM214.7 190.3v2.3M214.9 193.9v2.3h1.3M215.7 198.5a.54 .54 0 0 1 .6-.2 .54 .54 0 0 1 .3 .6v.3a.55 .55 0 0 1-.5 .6 .55 .55 0 0 1-.6-.6zM217.1 190.3v2.3l-1.5-2.3v2.3M218 191.4h.8M218.1 198.7a.53 .53 0 0 0-.6-.4 .53 .53 0 0 0-.4 .6v.3a.53 .53 0 0 0 .4 .6 .53 .53 0 0 0 .6-.3M218.5 198.3v1.1a.49 .49 0 0 0 .5 .4 .49 .49 0 0 0 .5-.4v-1.1M218.8 193.9h1.6M219.4 190.3h-1.4v2.3h1.4"/>
<path d="M219.6 193.9v2.3M220.3 192.5l-.1 .1-.1-.1 .1-.1a.43 .43 0 0 1-.1 .7M220.8 193.9v2.3M220.8 195h1.5M222.3 193.9v2.3M223.2 193.9v2.3M225.6 193.9v2.3l-1.5-2.3v2.3M228.8 194.3a.85 .85 0 0 1 1-.3 .85 .85 0 0 1 .5 .8 1 1 0 0 1-.2 1.1 1 1 0 0 1-1.1 .2 1.46 1.46 0 0 1-.2-1.8zM229.6 195.8l.6 .7M231 195h.9M232.4 193.9h-1.4v2.3M234.5 193.9v2.3l-1.6-2.3v2.3"/>
<path d="M235.6 196.1l-.1 .1-.1-.1 .1-.1 .1 .1-.2 .6M238.5 193.9h1.6l-1.1 2.3M240.7 194.7l1.2 1.5M241.9 194.7l-1.2 1.5M242.6 193.9h1.5l-1.1 2.3M244.8 194.7l1.2 1.5M246 194.7l-1.2 1.5M246.9 194a.77 .77 0 0 1 1.1 .4 1.96 1.96 0 0 1-.2 1.7 .77 .77 0 0 1-1.1-.3 1.96 1.96 0 0 1 .2-1.8zM248.9 196l-.1 .1 .1 .1 .1-.1M249.9 193.9h1.5l-1.1 2.3M251.1 197.4v8.1M251.9 199h.8l.2-.3-.1-.3-.3-.1h-.6v1.5"/>
<path d="M252.4 199l.5 .8M253.4 199h.5M253.4 193.9h-1.1l-.1 1a.82 .82 0 0 1 1.2 0 .82 .82 0 0 1-.1 1.2 .82 .82 0 0 1-1.2-.3M254.3 198.3h-.9v1.5h.9M254.3 195.1l.5-.4 .6 .1 .1 1.4M254.3 194.7v1.5M254.7 198.3l.5 1.5 .6-1.5M255.5 195.1l.5-.4 .6 .1 .1 1.4M256.1 199.7v.1h.1M257.6 195.1l.5-.4 .5 .1 .1 1.4M257.6 194.7v1.5M258.7 195.1l.6-.4 .5 .1 .2 1.4"/>
<path d="M259.9 197.4v8.1M262.1 197.9h1.2l-.7 .9a.79 .79 0 0 1 .9 1 .79 .79 0 0 1-1.1 .6l-.3-.1-.3-.4M266.5 198.6l-5.4 5.3M196.2 202.4h.9l-.9 1.5h.9M197.5 202.4v1.5M197.5 203.1h.9M198.4 202.4v1.5M199 203.1h.5M199.8 202.4h-.8v1.5h.8M201.1 202.4v1.5l-.9-1.5v1.5M202.9 202.4v1.5h.8M204 202.4v1.5"/>
<path d="M254.6 200.9l1 1.4 1.1-1.4M255.6 202.3v1.6M265.1 201.4h1.2l-.7 .9a.8 .8 0 0 1 .9 1 .8 .8 0 0 1-1.1 .6l-.3-.1-.3-.4"/>
</g>
<!-- layer: 2 -->
<path d="M23.5 36.6l2.4 4.8h-4.8zM23.5 49.2l2.4 4.7h-4.8zM23.8 78.4l2.6 5.4h-5.3z" fill="none" stroke="#000" stroke-width=".25"/>
<!-- layer: 0 -->
<g fill="#000" stroke="#000" stroke-width=".2">
<path d="M9.9 10.2l1 1 258.3-1zM10.9 11.2l258.3-1-1 1z"/>
<path d="M268.2 11.2l1 194.8v-195.8zM268.2 11.2l1 194.8-1-1zM9.9 206h259.3l-1-1zM9.9 206l1-1h257.3zM9.9 10.2v195.8l1-1zM9.9 10.2l1 1v193.8zM9.9 10.2l1 1z"/>
<path d="M213.1 176l1.5 2.5v-2.5zM213.1 176l1.5 2.5h-1.5z"/>
<path d="M213.1 178.5l1.5 2.6v-2.6zM213.1 178.5l1.5 2.6h-1.5z"/>
<path d="M213.1 174.7l7.3 1.3v-1.3zM213.1 174.7l7.3 1.3h-7.3z"/>
<path d="M214.6 176l5.8 2.5v-2.5zM214.6 176l5.8 2.5h-1.1z"/>
<path d="M219.3 178.5l1.1 2.6v-2.6zM214.6 181.1l4.7-2.6 1.1 2.6z"/>
<path d="M213.1 181.1l7.3 .9v-.9zM213.1 181.1l7.3 .9h-7.3z"/>
</g>
<path d="M213.1 174.7h7.3v7.3h-7.3zM214.6 176l4.7 2.5-4.7 2.6z" fill="none" stroke="#000" stroke-width=".2"/>
<use href="#words"/>
</svg>
